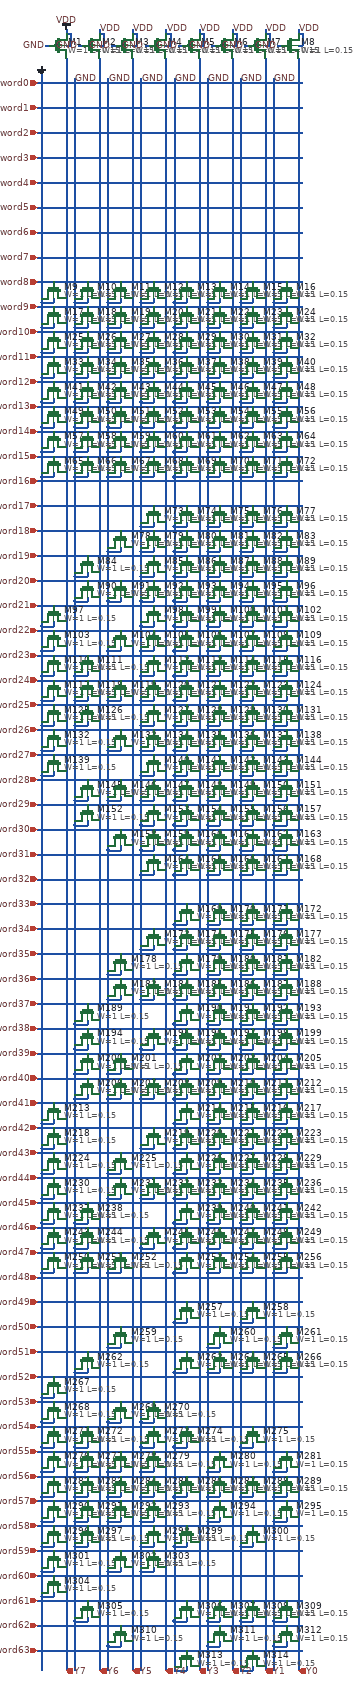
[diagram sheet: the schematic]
v {xschem version=3.4.5 file_version=1.2
}
G {}
K {}
V {}
S {}
E {}
N 10 -30 10 0 {
lab=GND}
N 20 -80 30 -80 {
lab=GND}
N 70 -120 70 -110 {
lab=VDD}
N 70 -80 80 -80 {
lab=VDD}
N 80 -110 80 -80 {
lab=VDD}
N 70 -110 80 -110 {
lab=VDD}
N 150 -80 160 -80 {
lab=VDD}
N 160 -110 160 -80 {
lab=VDD}
N 150 -110 160 -110 {
lab=VDD}
N 150 -120 150 -110 {
lab=VDD}
N 230 -120 230 -110 {
lab=VDD}
N 230 -110 240 -110 {
lab=VDD}
N 240 -110 240 -80 {
lab=VDD}
N 230 -80 240 -80 {
lab=VDD}
N 310 -120 310 -110 {
lab=VDD}
N 310 -110 320 -110 {
lab=VDD}
N 320 -110 320 -80 {
lab=VDD}
N 310 -80 320 -80 {
lab=VDD}
N 390 -120 390 -110 {
lab=VDD}
N 390 -110 400 -110 {
lab=VDD}
N 400 -110 400 -80 {
lab=VDD}
N 390 -80 400 -80 {
lab=VDD}
N 470 -80 480 -80 {
lab=VDD}
N 480 -110 480 -80 {
lab=VDD}
N 470 -110 480 -110 {
lab=VDD}
N 470 -120 470 -110 {
lab=VDD}
N 550 -80 560 -80 {
lab=VDD}
N 560 -110 560 -80 {
lab=VDD}
N 550 -110 560 -110 {
lab=VDD}
N 550 -120 550 -110 {
lab=VDD}
N 630 -80 640 -80 {
lab=VDD}
N 640 -110 640 -80 {
lab=VDD}
N 630 -110 640 -110 {
lab=VDD}
N 630 -120 630 -110 {
lab=VDD}
N 70 -50 70 0 {
lab=Y7}
N 150 -50 150 0 {
lab=Y6}
N 230 -50 230 0 {
lab=Y5}
N 310 -50 310 0 {
lab=Y4}
N 390 -50 390 0 {
lab=Y3}
N 470 -50 470 0 {
lab=Y2}
N 550 -50 550 0 {
lab=Y1}
N 630 -50 630 0 {
lab=Y0}
N 100 -80 110 -80 {
lab=GND}
N 180 -80 190 -80 {
lab=GND}
N 260 -80 270 -80 {
lab=GND}
N 340 -80 350 -80 {
lab=GND}
N 420 -80 430 -80 {
lab=GND}
N 500 -80 510 -80 {
lab=GND}
N 580 -80 590 -80 {
lab=GND}
N 0 10 40 10 {
lab=word0}
N 40 10 80 10 {
lab=word0}
N 10 0 10 50 {
lab=GND}
N 10 50 10 60 {
lab=GND}
N 70 0 70 50 {
lab=Y0}
N 70 50 70 60 {
lab=Y0}
N 80 10 120 10 {
lab=word0}
N 120 10 160 10 {
lab=word0}
N 90 0 90 50 {
lab=GND}
N 90 50 90 60 {
lab=GND}
N 150 0 150 50 {
lab=Y1}
N 150 50 150 60 {
lab=Y1}
N 160 10 200 10 {
lab=word0}
N 200 10 240 10 {
lab=word0}
N 170 0 170 50 {
lab=GND}
N 170 50 170 60 {
lab=GND}
N 230 0 230 50 {
lab=Y2}
N 230 50 230 60 {
lab=Y2}
N 240 10 280 10 {
lab=word0}
N 280 10 320 10 {
lab=word0}
N 250 0 250 50 {
lab=GND}
N 250 50 250 60 {
lab=GND}
N 310 0 310 50 {
lab=Y3}
N 310 50 310 60 {
lab=Y3}
N 320 10 360 10 {
lab=word0}
N 360 10 400 10 {
lab=word0}
N 330 0 330 50 {
lab=GND}
N 330 50 330 60 {
lab=GND}
N 390 0 390 50 {
lab=Y4}
N 390 50 390 60 {
lab=Y4}
N 400 10 440 10 {
lab=word0}
N 440 10 480 10 {
lab=word0}
N 410 0 410 50 {
lab=GND}
N 410 50 410 60 {
lab=GND}
N 470 0 470 50 {
lab=Y5}
N 470 50 470 60 {
lab=Y5}
N 480 10 520 10 {
lab=word0}
N 520 10 560 10 {
lab=word0}
N 490 0 490 50 {
lab=GND}
N 490 50 490 60 {
lab=GND}
N 550 0 550 50 {
lab=Y6}
N 550 50 550 60 {
lab=Y6}
N 560 10 600 10 {
lab=word0}
N 600 10 640 10 {
lab=word0}
N 570 0 570 50 {
lab=GND}
N 570 50 570 60 {
lab=GND}
N 630 0 630 50 {
lab=Y7}
N 630 50 630 60 {
lab=Y7}
N 0 70 40 70 {
lab=word1}
N 40 70 80 70 {
lab=word1}
N 10 60 10 110 {
lab=GND}
N 10 110 10 120 {
lab=GND}
N 70 60 70 110 {
lab=Y0}
N 70 110 70 120 {
lab=Y0}
N 80 70 120 70 {
lab=word1}
N 120 70 160 70 {
lab=word1}
N 90 60 90 110 {
lab=GND}
N 90 110 90 120 {
lab=GND}
N 150 60 150 110 {
lab=Y1}
N 150 110 150 120 {
lab=Y1}
N 160 70 200 70 {
lab=word1}
N 200 70 240 70 {
lab=word1}
N 170 60 170 110 {
lab=GND}
N 170 110 170 120 {
lab=GND}
N 230 60 230 110 {
lab=Y2}
N 230 110 230 120 {
lab=Y2}
N 240 70 280 70 {
lab=word1}
N 280 70 320 70 {
lab=word1}
N 250 60 250 110 {
lab=GND}
N 250 110 250 120 {
lab=GND}
N 310 60 310 110 {
lab=Y3}
N 310 110 310 120 {
lab=Y3}
N 320 70 360 70 {
lab=word1}
N 360 70 400 70 {
lab=word1}
N 330 60 330 110 {
lab=GND}
N 330 110 330 120 {
lab=GND}
N 390 60 390 110 {
lab=Y4}
N 390 110 390 120 {
lab=Y4}
N 400 70 440 70 {
lab=word1}
N 440 70 480 70 {
lab=word1}
N 410 60 410 110 {
lab=GND}
N 410 110 410 120 {
lab=GND}
N 470 60 470 110 {
lab=Y5}
N 470 110 470 120 {
lab=Y5}
N 480 70 520 70 {
lab=word1}
N 520 70 560 70 {
lab=word1}
N 490 60 490 110 {
lab=GND}
N 490 110 490 120 {
lab=GND}
N 550 60 550 110 {
lab=Y6}
N 550 110 550 120 {
lab=Y6}
N 560 70 600 70 {
lab=word1}
N 600 70 640 70 {
lab=word1}
N 570 60 570 110 {
lab=GND}
N 570 110 570 120 {
lab=GND}
N 630 60 630 110 {
lab=Y7}
N 630 110 630 120 {
lab=Y7}
N 0 130 40 130 {
lab=word2}
N 40 130 80 130 {
lab=word2}
N 10 120 10 170 {
lab=GND}
N 10 170 10 180 {
lab=GND}
N 70 120 70 170 {
lab=Y0}
N 70 170 70 180 {
lab=Y0}
N 80 130 120 130 {
lab=word2}
N 120 130 160 130 {
lab=word2}
N 90 120 90 170 {
lab=GND}
N 90 170 90 180 {
lab=GND}
N 150 120 150 170 {
lab=Y1}
N 150 170 150 180 {
lab=Y1}
N 160 130 200 130 {
lab=word2}
N 200 130 240 130 {
lab=word2}
N 170 120 170 170 {
lab=GND}
N 170 170 170 180 {
lab=GND}
N 230 120 230 170 {
lab=Y2}
N 230 170 230 180 {
lab=Y2}
N 240 130 280 130 {
lab=word2}
N 280 130 320 130 {
lab=word2}
N 250 120 250 170 {
lab=GND}
N 250 170 250 180 {
lab=GND}
N 310 120 310 170 {
lab=Y3}
N 310 170 310 180 {
lab=Y3}
N 320 130 360 130 {
lab=word2}
N 360 130 400 130 {
lab=word2}
N 330 120 330 170 {
lab=GND}
N 330 170 330 180 {
lab=GND}
N 390 120 390 170 {
lab=Y4}
N 390 170 390 180 {
lab=Y4}
N 400 130 440 130 {
lab=word2}
N 440 130 480 130 {
lab=word2}
N 410 120 410 170 {
lab=GND}
N 410 170 410 180 {
lab=GND}
N 470 120 470 170 {
lab=Y5}
N 470 170 470 180 {
lab=Y5}
N 480 130 520 130 {
lab=word2}
N 520 130 560 130 {
lab=word2}
N 490 120 490 170 {
lab=GND}
N 490 170 490 180 {
lab=GND}
N 550 120 550 170 {
lab=Y6}
N 550 170 550 180 {
lab=Y6}
N 560 130 600 130 {
lab=word2}
N 600 130 640 130 {
lab=word2}
N 570 120 570 170 {
lab=GND}
N 570 170 570 180 {
lab=GND}
N 630 120 630 170 {
lab=Y7}
N 630 170 630 180 {
lab=Y7}
N 0 190 40 190 {
lab=word3}
N 40 190 80 190 {
lab=word3}
N 10 180 10 230 {
lab=GND}
N 10 230 10 240 {
lab=GND}
N 70 180 70 230 {
lab=Y0}
N 70 230 70 240 {
lab=Y0}
N 80 190 120 190 {
lab=word3}
N 120 190 160 190 {
lab=word3}
N 90 180 90 230 {
lab=GND}
N 90 230 90 240 {
lab=GND}
N 150 180 150 230 {
lab=Y1}
N 150 230 150 240 {
lab=Y1}
N 160 190 200 190 {
lab=word3}
N 200 190 240 190 {
lab=word3}
N 170 180 170 230 {
lab=GND}
N 170 230 170 240 {
lab=GND}
N 230 180 230 230 {
lab=Y2}
N 230 230 230 240 {
lab=Y2}
N 240 190 280 190 {
lab=word3}
N 280 190 320 190 {
lab=word3}
N 250 180 250 230 {
lab=GND}
N 250 230 250 240 {
lab=GND}
N 310 180 310 230 {
lab=Y3}
N 310 230 310 240 {
lab=Y3}
N 320 190 360 190 {
lab=word3}
N 360 190 400 190 {
lab=word3}
N 330 180 330 230 {
lab=GND}
N 330 230 330 240 {
lab=GND}
N 390 180 390 230 {
lab=Y4}
N 390 230 390 240 {
lab=Y4}
N 400 190 440 190 {
lab=word3}
N 440 190 480 190 {
lab=word3}
N 410 180 410 230 {
lab=GND}
N 410 230 410 240 {
lab=GND}
N 470 180 470 230 {
lab=Y5}
N 470 230 470 240 {
lab=Y5}
N 480 190 520 190 {
lab=word3}
N 520 190 560 190 {
lab=word3}
N 490 180 490 230 {
lab=GND}
N 490 230 490 240 {
lab=GND}
N 550 180 550 230 {
lab=Y6}
N 550 230 550 240 {
lab=Y6}
N 560 190 600 190 {
lab=word3}
N 600 190 640 190 {
lab=word3}
N 570 180 570 230 {
lab=GND}
N 570 230 570 240 {
lab=GND}
N 630 180 630 230 {
lab=Y7}
N 630 230 630 240 {
lab=Y7}
N 0 250 40 250 {
lab=word4}
N 40 250 80 250 {
lab=word4}
N 10 240 10 290 {
lab=GND}
N 10 290 10 300 {
lab=GND}
N 70 240 70 290 {
lab=Y0}
N 70 290 70 300 {
lab=Y0}
N 80 250 120 250 {
lab=word4}
N 120 250 160 250 {
lab=word4}
N 90 240 90 290 {
lab=GND}
N 90 290 90 300 {
lab=GND}
N 150 240 150 290 {
lab=Y1}
N 150 290 150 300 {
lab=Y1}
N 160 250 200 250 {
lab=word4}
N 200 250 240 250 {
lab=word4}
N 170 240 170 290 {
lab=GND}
N 170 290 170 300 {
lab=GND}
N 230 240 230 290 {
lab=Y2}
N 230 290 230 300 {
lab=Y2}
N 240 250 280 250 {
lab=word4}
N 280 250 320 250 {
lab=word4}
N 250 240 250 290 {
lab=GND}
N 250 290 250 300 {
lab=GND}
N 310 240 310 290 {
lab=Y3}
N 310 290 310 300 {
lab=Y3}
N 320 250 360 250 {
lab=word4}
N 360 250 400 250 {
lab=word4}
N 330 240 330 290 {
lab=GND}
N 330 290 330 300 {
lab=GND}
N 390 240 390 290 {
lab=Y4}
N 390 290 390 300 {
lab=Y4}
N 400 250 440 250 {
lab=word4}
N 440 250 480 250 {
lab=word4}
N 410 240 410 290 {
lab=GND}
N 410 290 410 300 {
lab=GND}
N 470 240 470 290 {
lab=Y5}
N 470 290 470 300 {
lab=Y5}
N 480 250 520 250 {
lab=word4}
N 520 250 560 250 {
lab=word4}
N 490 240 490 290 {
lab=GND}
N 490 290 490 300 {
lab=GND}
N 550 240 550 290 {
lab=Y6}
N 550 290 550 300 {
lab=Y6}
N 560 250 600 250 {
lab=word4}
N 600 250 640 250 {
lab=word4}
N 570 240 570 290 {
lab=GND}
N 570 290 570 300 {
lab=GND}
N 630 240 630 290 {
lab=Y7}
N 630 290 630 300 {
lab=Y7}
N 0 310 40 310 {
lab=word5}
N 40 310 80 310 {
lab=word5}
N 10 300 10 350 {
lab=GND}
N 10 350 10 360 {
lab=GND}
N 70 300 70 350 {
lab=Y0}
N 70 350 70 360 {
lab=Y0}
N 80 310 120 310 {
lab=word5}
N 120 310 160 310 {
lab=word5}
N 90 300 90 350 {
lab=GND}
N 90 350 90 360 {
lab=GND}
N 150 300 150 350 {
lab=Y1}
N 150 350 150 360 {
lab=Y1}
N 160 310 200 310 {
lab=word5}
N 200 310 240 310 {
lab=word5}
N 170 300 170 350 {
lab=GND}
N 170 350 170 360 {
lab=GND}
N 230 300 230 350 {
lab=Y2}
N 230 350 230 360 {
lab=Y2}
N 240 310 280 310 {
lab=word5}
N 280 310 320 310 {
lab=word5}
N 250 300 250 350 {
lab=GND}
N 250 350 250 360 {
lab=GND}
N 310 300 310 350 {
lab=Y3}
N 310 350 310 360 {
lab=Y3}
N 320 310 360 310 {
lab=word5}
N 360 310 400 310 {
lab=word5}
N 330 300 330 350 {
lab=GND}
N 330 350 330 360 {
lab=GND}
N 390 300 390 350 {
lab=Y4}
N 390 350 390 360 {
lab=Y4}
N 400 310 440 310 {
lab=word5}
N 440 310 480 310 {
lab=word5}
N 410 300 410 350 {
lab=GND}
N 410 350 410 360 {
lab=GND}
N 470 300 470 350 {
lab=Y5}
N 470 350 470 360 {
lab=Y5}
N 480 310 520 310 {
lab=word5}
N 520 310 560 310 {
lab=word5}
N 490 300 490 350 {
lab=GND}
N 490 350 490 360 {
lab=GND}
N 550 300 550 350 {
lab=Y6}
N 550 350 550 360 {
lab=Y6}
N 560 310 600 310 {
lab=word5}
N 600 310 640 310 {
lab=word5}
N 570 300 570 350 {
lab=GND}
N 570 350 570 360 {
lab=GND}
N 630 300 630 350 {
lab=Y7}
N 630 350 630 360 {
lab=Y7}
N 0 370 40 370 {
lab=word6}
N 40 370 80 370 {
lab=word6}
N 10 360 10 410 {
lab=GND}
N 10 410 10 420 {
lab=GND}
N 70 360 70 410 {
lab=Y0}
N 70 410 70 420 {
lab=Y0}
N 80 370 120 370 {
lab=word6}
N 120 370 160 370 {
lab=word6}
N 90 360 90 410 {
lab=GND}
N 90 410 90 420 {
lab=GND}
N 150 360 150 410 {
lab=Y1}
N 150 410 150 420 {
lab=Y1}
N 160 370 200 370 {
lab=word6}
N 200 370 240 370 {
lab=word6}
N 170 360 170 410 {
lab=GND}
N 170 410 170 420 {
lab=GND}
N 230 360 230 410 {
lab=Y2}
N 230 410 230 420 {
lab=Y2}
N 240 370 280 370 {
lab=word6}
N 280 370 320 370 {
lab=word6}
N 250 360 250 410 {
lab=GND}
N 250 410 250 420 {
lab=GND}
N 310 360 310 410 {
lab=Y3}
N 310 410 310 420 {
lab=Y3}
N 320 370 360 370 {
lab=word6}
N 360 370 400 370 {
lab=word6}
N 330 360 330 410 {
lab=GND}
N 330 410 330 420 {
lab=GND}
N 390 360 390 410 {
lab=Y4}
N 390 410 390 420 {
lab=Y4}
N 400 370 440 370 {
lab=word6}
N 440 370 480 370 {
lab=word6}
N 410 360 410 410 {
lab=GND}
N 410 410 410 420 {
lab=GND}
N 470 360 470 410 {
lab=Y5}
N 470 410 470 420 {
lab=Y5}
N 480 370 520 370 {
lab=word6}
N 520 370 560 370 {
lab=word6}
N 490 360 490 410 {
lab=GND}
N 490 410 490 420 {
lab=GND}
N 550 360 550 410 {
lab=Y6}
N 550 410 550 420 {
lab=Y6}
N 560 370 600 370 {
lab=word6}
N 600 370 640 370 {
lab=word6}
N 570 360 570 410 {
lab=GND}
N 570 410 570 420 {
lab=GND}
N 630 360 630 410 {
lab=Y7}
N 630 410 630 420 {
lab=Y7}
N 0 430 40 430 {
lab=word7}
N 40 430 80 430 {
lab=word7}
N 10 420 10 470 {
lab=GND}
N 10 470 10 480 {
lab=GND}
N 70 420 70 470 {
lab=Y0}
N 70 470 70 480 {
lab=Y0}
N 80 430 120 430 {
lab=word7}
N 120 430 160 430 {
lab=word7}
N 90 420 90 470 {
lab=GND}
N 90 470 90 480 {
lab=GND}
N 150 420 150 470 {
lab=Y1}
N 150 470 150 480 {
lab=Y1}
N 160 430 200 430 {
lab=word7}
N 200 430 240 430 {
lab=word7}
N 170 420 170 470 {
lab=GND}
N 170 470 170 480 {
lab=GND}
N 230 420 230 470 {
lab=Y2}
N 230 470 230 480 {
lab=Y2}
N 240 430 280 430 {
lab=word7}
N 280 430 320 430 {
lab=word7}
N 250 420 250 470 {
lab=GND}
N 250 470 250 480 {
lab=GND}
N 310 420 310 470 {
lab=Y3}
N 310 470 310 480 {
lab=Y3}
N 320 430 360 430 {
lab=word7}
N 360 430 400 430 {
lab=word7}
N 330 420 330 470 {
lab=GND}
N 330 470 330 480 {
lab=GND}
N 390 420 390 470 {
lab=Y4}
N 390 470 390 480 {
lab=Y4}
N 400 430 440 430 {
lab=word7}
N 440 430 480 430 {
lab=word7}
N 410 420 410 470 {
lab=GND}
N 410 470 410 480 {
lab=GND}
N 470 420 470 470 {
lab=Y5}
N 470 470 470 480 {
lab=Y5}
N 480 430 520 430 {
lab=word7}
N 520 430 560 430 {
lab=word7}
N 490 420 490 470 {
lab=GND}
N 490 470 490 480 {
lab=GND}
N 550 420 550 470 {
lab=Y6}
N 550 470 550 480 {
lab=Y6}
N 560 430 600 430 {
lab=word7}
N 600 430 640 430 {
lab=word7}
N 570 420 570 470 {
lab=GND}
N 570 470 570 480 {
lab=GND}
N 630 420 630 470 {
lab=Y7}
N 630 470 630 480 {
lab=Y7}
N 10 540 40 540 {
lab=GND}
N 40 530 40 540 {
lab=GND}
N 0 490 40 490 {
lab=word8}
N 40 490 80 490 {
lab=word8}
N 10 480 10 530 {
lab=GND}
N 10 530 10 540 {
lab=GND}
N 70 480 70 530 {
lab=Y0}
N 70 530 70 540 {
lab=Y0}
N 90 540 120 540 {
lab=GND}
N 120 530 120 540 {
lab=GND}
N 80 490 120 490 {
lab=word8}
N 120 490 160 490 {
lab=word8}
N 90 480 90 530 {
lab=GND}
N 90 530 90 540 {
lab=GND}
N 150 480 150 530 {
lab=Y1}
N 150 530 150 540 {
lab=Y1}
N 170 540 200 540 {
lab=GND}
N 200 530 200 540 {
lab=GND}
N 160 490 200 490 {
lab=word8}
N 200 490 240 490 {
lab=word8}
N 170 480 170 530 {
lab=GND}
N 170 530 170 540 {
lab=GND}
N 230 480 230 530 {
lab=Y2}
N 230 530 230 540 {
lab=Y2}
N 250 540 280 540 {
lab=GND}
N 280 530 280 540 {
lab=GND}
N 240 490 280 490 {
lab=word8}
N 280 490 320 490 {
lab=word8}
N 250 480 250 530 {
lab=GND}
N 250 530 250 540 {
lab=GND}
N 310 480 310 530 {
lab=Y3}
N 310 530 310 540 {
lab=Y3}
N 330 540 360 540 {
lab=GND}
N 360 530 360 540 {
lab=GND}
N 320 490 360 490 {
lab=word8}
N 360 490 400 490 {
lab=word8}
N 330 480 330 530 {
lab=GND}
N 330 530 330 540 {
lab=GND}
N 390 480 390 530 {
lab=Y4}
N 390 530 390 540 {
lab=Y4}
N 410 540 440 540 {
lab=GND}
N 440 530 440 540 {
lab=GND}
N 400 490 440 490 {
lab=word8}
N 440 490 480 490 {
lab=word8}
N 410 480 410 530 {
lab=GND}
N 410 530 410 540 {
lab=GND}
N 470 480 470 530 {
lab=Y5}
N 470 530 470 540 {
lab=Y5}
N 490 540 520 540 {
lab=GND}
N 520 530 520 540 {
lab=GND}
N 480 490 520 490 {
lab=word8}
N 520 490 560 490 {
lab=word8}
N 490 480 490 530 {
lab=GND}
N 490 530 490 540 {
lab=GND}
N 550 480 550 530 {
lab=Y6}
N 550 530 550 540 {
lab=Y6}
N 570 540 600 540 {
lab=GND}
N 600 530 600 540 {
lab=GND}
N 560 490 600 490 {
lab=word8}
N 600 490 640 490 {
lab=word8}
N 570 480 570 530 {
lab=GND}
N 570 530 570 540 {
lab=GND}
N 630 480 630 530 {
lab=Y7}
N 630 530 630 540 {
lab=Y7}
N 10 600 40 600 {
lab=GND}
N 40 590 40 600 {
lab=GND}
N 0 550 40 550 {
lab=word9}
N 40 550 80 550 {
lab=word9}
N 10 540 10 590 {
lab=GND}
N 10 590 10 600 {
lab=GND}
N 70 540 70 590 {
lab=Y0}
N 70 590 70 600 {
lab=Y0}
N 90 600 120 600 {
lab=GND}
N 120 590 120 600 {
lab=GND}
N 80 550 120 550 {
lab=word9}
N 120 550 160 550 {
lab=word9}
N 90 540 90 590 {
lab=GND}
N 90 590 90 600 {
lab=GND}
N 150 540 150 590 {
lab=Y1}
N 150 590 150 600 {
lab=Y1}
N 170 600 200 600 {
lab=GND}
N 200 590 200 600 {
lab=GND}
N 160 550 200 550 {
lab=word9}
N 200 550 240 550 {
lab=word9}
N 170 540 170 590 {
lab=GND}
N 170 590 170 600 {
lab=GND}
N 230 540 230 590 {
lab=Y2}
N 230 590 230 600 {
lab=Y2}
N 250 600 280 600 {
lab=GND}
N 280 590 280 600 {
lab=GND}
N 240 550 280 550 {
lab=word9}
N 280 550 320 550 {
lab=word9}
N 250 540 250 590 {
lab=GND}
N 250 590 250 600 {
lab=GND}
N 310 540 310 590 {
lab=Y3}
N 310 590 310 600 {
lab=Y3}
N 330 600 360 600 {
lab=GND}
N 360 590 360 600 {
lab=GND}
N 320 550 360 550 {
lab=word9}
N 360 550 400 550 {
lab=word9}
N 330 540 330 590 {
lab=GND}
N 330 590 330 600 {
lab=GND}
N 390 540 390 590 {
lab=Y4}
N 390 590 390 600 {
lab=Y4}
N 410 600 440 600 {
lab=GND}
N 440 590 440 600 {
lab=GND}
N 400 550 440 550 {
lab=word9}
N 440 550 480 550 {
lab=word9}
N 410 540 410 590 {
lab=GND}
N 410 590 410 600 {
lab=GND}
N 470 540 470 590 {
lab=Y5}
N 470 590 470 600 {
lab=Y5}
N 490 600 520 600 {
lab=GND}
N 520 590 520 600 {
lab=GND}
N 480 550 520 550 {
lab=word9}
N 520 550 560 550 {
lab=word9}
N 490 540 490 590 {
lab=GND}
N 490 590 490 600 {
lab=GND}
N 550 540 550 590 {
lab=Y6}
N 550 590 550 600 {
lab=Y6}
N 570 600 600 600 {
lab=GND}
N 600 590 600 600 {
lab=GND}
N 560 550 600 550 {
lab=word9}
N 600 550 640 550 {
lab=word9}
N 570 540 570 590 {
lab=GND}
N 570 590 570 600 {
lab=GND}
N 630 540 630 590 {
lab=Y7}
N 630 590 630 600 {
lab=Y7}
N 10 660 40 660 {
lab=GND}
N 40 650 40 660 {
lab=GND}
N 0 610 40 610 {
lab=word10}
N 40 610 80 610 {
lab=word10}
N 10 600 10 650 {
lab=GND}
N 10 650 10 660 {
lab=GND}
N 70 600 70 650 {
lab=Y0}
N 70 650 70 660 {
lab=Y0}
N 90 660 120 660 {
lab=GND}
N 120 650 120 660 {
lab=GND}
N 80 610 120 610 {
lab=word10}
N 120 610 160 610 {
lab=word10}
N 90 600 90 650 {
lab=GND}
N 90 650 90 660 {
lab=GND}
N 150 600 150 650 {
lab=Y1}
N 150 650 150 660 {
lab=Y1}
N 170 660 200 660 {
lab=GND}
N 200 650 200 660 {
lab=GND}
N 160 610 200 610 {
lab=word10}
N 200 610 240 610 {
lab=word10}
N 170 600 170 650 {
lab=GND}
N 170 650 170 660 {
lab=GND}
N 230 600 230 650 {
lab=Y2}
N 230 650 230 660 {
lab=Y2}
N 250 660 280 660 {
lab=GND}
N 280 650 280 660 {
lab=GND}
N 240 610 280 610 {
lab=word10}
N 280 610 320 610 {
lab=word10}
N 250 600 250 650 {
lab=GND}
N 250 650 250 660 {
lab=GND}
N 310 600 310 650 {
lab=Y3}
N 310 650 310 660 {
lab=Y3}
N 330 660 360 660 {
lab=GND}
N 360 650 360 660 {
lab=GND}
N 320 610 360 610 {
lab=word10}
N 360 610 400 610 {
lab=word10}
N 330 600 330 650 {
lab=GND}
N 330 650 330 660 {
lab=GND}
N 390 600 390 650 {
lab=Y4}
N 390 650 390 660 {
lab=Y4}
N 410 660 440 660 {
lab=GND}
N 440 650 440 660 {
lab=GND}
N 400 610 440 610 {
lab=word10}
N 440 610 480 610 {
lab=word10}
N 410 600 410 650 {
lab=GND}
N 410 650 410 660 {
lab=GND}
N 470 600 470 650 {
lab=Y5}
N 470 650 470 660 {
lab=Y5}
N 490 660 520 660 {
lab=GND}
N 520 650 520 660 {
lab=GND}
N 480 610 520 610 {
lab=word10}
N 520 610 560 610 {
lab=word10}
N 490 600 490 650 {
lab=GND}
N 490 650 490 660 {
lab=GND}
N 550 600 550 650 {
lab=Y6}
N 550 650 550 660 {
lab=Y6}
N 570 660 600 660 {
lab=GND}
N 600 650 600 660 {
lab=GND}
N 560 610 600 610 {
lab=word10}
N 600 610 640 610 {
lab=word10}
N 570 600 570 650 {
lab=GND}
N 570 650 570 660 {
lab=GND}
N 630 600 630 650 {
lab=Y7}
N 630 650 630 660 {
lab=Y7}
N 10 720 40 720 {
lab=GND}
N 40 710 40 720 {
lab=GND}
N 0 670 40 670 {
lab=word11}
N 40 670 80 670 {
lab=word11}
N 10 660 10 710 {
lab=GND}
N 10 710 10 720 {
lab=GND}
N 70 660 70 710 {
lab=Y0}
N 70 710 70 720 {
lab=Y0}
N 90 720 120 720 {
lab=GND}
N 120 710 120 720 {
lab=GND}
N 80 670 120 670 {
lab=word11}
N 120 670 160 670 {
lab=word11}
N 90 660 90 710 {
lab=GND}
N 90 710 90 720 {
lab=GND}
N 150 660 150 710 {
lab=Y1}
N 150 710 150 720 {
lab=Y1}
N 170 720 200 720 {
lab=GND}
N 200 710 200 720 {
lab=GND}
N 160 670 200 670 {
lab=word11}
N 200 670 240 670 {
lab=word11}
N 170 660 170 710 {
lab=GND}
N 170 710 170 720 {
lab=GND}
N 230 660 230 710 {
lab=Y2}
N 230 710 230 720 {
lab=Y2}
N 250 720 280 720 {
lab=GND}
N 280 710 280 720 {
lab=GND}
N 240 670 280 670 {
lab=word11}
N 280 670 320 670 {
lab=word11}
N 250 660 250 710 {
lab=GND}
N 250 710 250 720 {
lab=GND}
N 310 660 310 710 {
lab=Y3}
N 310 710 310 720 {
lab=Y3}
N 330 720 360 720 {
lab=GND}
N 360 710 360 720 {
lab=GND}
N 320 670 360 670 {
lab=word11}
N 360 670 400 670 {
lab=word11}
N 330 660 330 710 {
lab=GND}
N 330 710 330 720 {
lab=GND}
N 390 660 390 710 {
lab=Y4}
N 390 710 390 720 {
lab=Y4}
N 410 720 440 720 {
lab=GND}
N 440 710 440 720 {
lab=GND}
N 400 670 440 670 {
lab=word11}
N 440 670 480 670 {
lab=word11}
N 410 660 410 710 {
lab=GND}
N 410 710 410 720 {
lab=GND}
N 470 660 470 710 {
lab=Y5}
N 470 710 470 720 {
lab=Y5}
N 490 720 520 720 {
lab=GND}
N 520 710 520 720 {
lab=GND}
N 480 670 520 670 {
lab=word11}
N 520 670 560 670 {
lab=word11}
N 490 660 490 710 {
lab=GND}
N 490 710 490 720 {
lab=GND}
N 550 660 550 710 {
lab=Y6}
N 550 710 550 720 {
lab=Y6}
N 570 720 600 720 {
lab=GND}
N 600 710 600 720 {
lab=GND}
N 560 670 600 670 {
lab=word11}
N 600 670 640 670 {
lab=word11}
N 570 660 570 710 {
lab=GND}
N 570 710 570 720 {
lab=GND}
N 630 660 630 710 {
lab=Y7}
N 630 710 630 720 {
lab=Y7}
N 10 780 40 780 {
lab=GND}
N 40 770 40 780 {
lab=GND}
N 0 730 40 730 {
lab=word12}
N 40 730 80 730 {
lab=word12}
N 10 720 10 770 {
lab=GND}
N 10 770 10 780 {
lab=GND}
N 70 720 70 770 {
lab=Y0}
N 70 770 70 780 {
lab=Y0}
N 90 780 120 780 {
lab=GND}
N 120 770 120 780 {
lab=GND}
N 80 730 120 730 {
lab=word12}
N 120 730 160 730 {
lab=word12}
N 90 720 90 770 {
lab=GND}
N 90 770 90 780 {
lab=GND}
N 150 720 150 770 {
lab=Y1}
N 150 770 150 780 {
lab=Y1}
N 170 780 200 780 {
lab=GND}
N 200 770 200 780 {
lab=GND}
N 160 730 200 730 {
lab=word12}
N 200 730 240 730 {
lab=word12}
N 170 720 170 770 {
lab=GND}
N 170 770 170 780 {
lab=GND}
N 230 720 230 770 {
lab=Y2}
N 230 770 230 780 {
lab=Y2}
N 250 780 280 780 {
lab=GND}
N 280 770 280 780 {
lab=GND}
N 240 730 280 730 {
lab=word12}
N 280 730 320 730 {
lab=word12}
N 250 720 250 770 {
lab=GND}
N 250 770 250 780 {
lab=GND}
N 310 720 310 770 {
lab=Y3}
N 310 770 310 780 {
lab=Y3}
N 330 780 360 780 {
lab=GND}
N 360 770 360 780 {
lab=GND}
N 320 730 360 730 {
lab=word12}
N 360 730 400 730 {
lab=word12}
N 330 720 330 770 {
lab=GND}
N 330 770 330 780 {
lab=GND}
N 390 720 390 770 {
lab=Y4}
N 390 770 390 780 {
lab=Y4}
N 410 780 440 780 {
lab=GND}
N 440 770 440 780 {
lab=GND}
N 400 730 440 730 {
lab=word12}
N 440 730 480 730 {
lab=word12}
N 410 720 410 770 {
lab=GND}
N 410 770 410 780 {
lab=GND}
N 470 720 470 770 {
lab=Y5}
N 470 770 470 780 {
lab=Y5}
N 490 780 520 780 {
lab=GND}
N 520 770 520 780 {
lab=GND}
N 480 730 520 730 {
lab=word12}
N 520 730 560 730 {
lab=word12}
N 490 720 490 770 {
lab=GND}
N 490 770 490 780 {
lab=GND}
N 550 720 550 770 {
lab=Y6}
N 550 770 550 780 {
lab=Y6}
N 570 780 600 780 {
lab=GND}
N 600 770 600 780 {
lab=GND}
N 560 730 600 730 {
lab=word12}
N 600 730 640 730 {
lab=word12}
N 570 720 570 770 {
lab=GND}
N 570 770 570 780 {
lab=GND}
N 630 720 630 770 {
lab=Y7}
N 630 770 630 780 {
lab=Y7}
N 10 840 40 840 {
lab=GND}
N 40 830 40 840 {
lab=GND}
N 0 790 40 790 {
lab=word13}
N 40 790 80 790 {
lab=word13}
N 10 780 10 830 {
lab=GND}
N 10 830 10 840 {
lab=GND}
N 70 780 70 830 {
lab=Y0}
N 70 830 70 840 {
lab=Y0}
N 90 840 120 840 {
lab=GND}
N 120 830 120 840 {
lab=GND}
N 80 790 120 790 {
lab=word13}
N 120 790 160 790 {
lab=word13}
N 90 780 90 830 {
lab=GND}
N 90 830 90 840 {
lab=GND}
N 150 780 150 830 {
lab=Y1}
N 150 830 150 840 {
lab=Y1}
N 170 840 200 840 {
lab=GND}
N 200 830 200 840 {
lab=GND}
N 160 790 200 790 {
lab=word13}
N 200 790 240 790 {
lab=word13}
N 170 780 170 830 {
lab=GND}
N 170 830 170 840 {
lab=GND}
N 230 780 230 830 {
lab=Y2}
N 230 830 230 840 {
lab=Y2}
N 250 840 280 840 {
lab=GND}
N 280 830 280 840 {
lab=GND}
N 240 790 280 790 {
lab=word13}
N 280 790 320 790 {
lab=word13}
N 250 780 250 830 {
lab=GND}
N 250 830 250 840 {
lab=GND}
N 310 780 310 830 {
lab=Y3}
N 310 830 310 840 {
lab=Y3}
N 330 840 360 840 {
lab=GND}
N 360 830 360 840 {
lab=GND}
N 320 790 360 790 {
lab=word13}
N 360 790 400 790 {
lab=word13}
N 330 780 330 830 {
lab=GND}
N 330 830 330 840 {
lab=GND}
N 390 780 390 830 {
lab=Y4}
N 390 830 390 840 {
lab=Y4}
N 410 840 440 840 {
lab=GND}
N 440 830 440 840 {
lab=GND}
N 400 790 440 790 {
lab=word13}
N 440 790 480 790 {
lab=word13}
N 410 780 410 830 {
lab=GND}
N 410 830 410 840 {
lab=GND}
N 470 780 470 830 {
lab=Y5}
N 470 830 470 840 {
lab=Y5}
N 490 840 520 840 {
lab=GND}
N 520 830 520 840 {
lab=GND}
N 480 790 520 790 {
lab=word13}
N 520 790 560 790 {
lab=word13}
N 490 780 490 830 {
lab=GND}
N 490 830 490 840 {
lab=GND}
N 550 780 550 830 {
lab=Y6}
N 550 830 550 840 {
lab=Y6}
N 570 840 600 840 {
lab=GND}
N 600 830 600 840 {
lab=GND}
N 560 790 600 790 {
lab=word13}
N 600 790 640 790 {
lab=word13}
N 570 780 570 830 {
lab=GND}
N 570 830 570 840 {
lab=GND}
N 630 780 630 830 {
lab=Y7}
N 630 830 630 840 {
lab=Y7}
N 10 900 40 900 {
lab=GND}
N 40 890 40 900 {
lab=GND}
N 0 850 40 850 {
lab=word14}
N 40 850 80 850 {
lab=word14}
N 10 840 10 890 {
lab=GND}
N 10 890 10 900 {
lab=GND}
N 70 840 70 890 {
lab=Y0}
N 70 890 70 900 {
lab=Y0}
N 90 900 120 900 {
lab=GND}
N 120 890 120 900 {
lab=GND}
N 80 850 120 850 {
lab=word14}
N 120 850 160 850 {
lab=word14}
N 90 840 90 890 {
lab=GND}
N 90 890 90 900 {
lab=GND}
N 150 840 150 890 {
lab=Y1}
N 150 890 150 900 {
lab=Y1}
N 170 900 200 900 {
lab=GND}
N 200 890 200 900 {
lab=GND}
N 160 850 200 850 {
lab=word14}
N 200 850 240 850 {
lab=word14}
N 170 840 170 890 {
lab=GND}
N 170 890 170 900 {
lab=GND}
N 230 840 230 890 {
lab=Y2}
N 230 890 230 900 {
lab=Y2}
N 250 900 280 900 {
lab=GND}
N 280 890 280 900 {
lab=GND}
N 240 850 280 850 {
lab=word14}
N 280 850 320 850 {
lab=word14}
N 250 840 250 890 {
lab=GND}
N 250 890 250 900 {
lab=GND}
N 310 840 310 890 {
lab=Y3}
N 310 890 310 900 {
lab=Y3}
N 330 900 360 900 {
lab=GND}
N 360 890 360 900 {
lab=GND}
N 320 850 360 850 {
lab=word14}
N 360 850 400 850 {
lab=word14}
N 330 840 330 890 {
lab=GND}
N 330 890 330 900 {
lab=GND}
N 390 840 390 890 {
lab=Y4}
N 390 890 390 900 {
lab=Y4}
N 410 900 440 900 {
lab=GND}
N 440 890 440 900 {
lab=GND}
N 400 850 440 850 {
lab=word14}
N 440 850 480 850 {
lab=word14}
N 410 840 410 890 {
lab=GND}
N 410 890 410 900 {
lab=GND}
N 470 840 470 890 {
lab=Y5}
N 470 890 470 900 {
lab=Y5}
N 490 900 520 900 {
lab=GND}
N 520 890 520 900 {
lab=GND}
N 480 850 520 850 {
lab=word14}
N 520 850 560 850 {
lab=word14}
N 490 840 490 890 {
lab=GND}
N 490 890 490 900 {
lab=GND}
N 550 840 550 890 {
lab=Y6}
N 550 890 550 900 {
lab=Y6}
N 570 900 600 900 {
lab=GND}
N 600 890 600 900 {
lab=GND}
N 560 850 600 850 {
lab=word14}
N 600 850 640 850 {
lab=word14}
N 570 840 570 890 {
lab=GND}
N 570 890 570 900 {
lab=GND}
N 630 840 630 890 {
lab=Y7}
N 630 890 630 900 {
lab=Y7}
N 10 960 40 960 {
lab=GND}
N 40 950 40 960 {
lab=GND}
N 0 910 40 910 {
lab=word15}
N 40 910 80 910 {
lab=word15}
N 10 900 10 950 {
lab=GND}
N 10 950 10 960 {
lab=GND}
N 70 900 70 950 {
lab=Y0}
N 70 950 70 960 {
lab=Y0}
N 90 960 120 960 {
lab=GND}
N 120 950 120 960 {
lab=GND}
N 80 910 120 910 {
lab=word15}
N 120 910 160 910 {
lab=word15}
N 90 900 90 950 {
lab=GND}
N 90 950 90 960 {
lab=GND}
N 150 900 150 950 {
lab=Y1}
N 150 950 150 960 {
lab=Y1}
N 170 960 200 960 {
lab=GND}
N 200 950 200 960 {
lab=GND}
N 160 910 200 910 {
lab=word15}
N 200 910 240 910 {
lab=word15}
N 170 900 170 950 {
lab=GND}
N 170 950 170 960 {
lab=GND}
N 230 900 230 950 {
lab=Y2}
N 230 950 230 960 {
lab=Y2}
N 250 960 280 960 {
lab=GND}
N 280 950 280 960 {
lab=GND}
N 240 910 280 910 {
lab=word15}
N 280 910 320 910 {
lab=word15}
N 250 900 250 950 {
lab=GND}
N 250 950 250 960 {
lab=GND}
N 310 900 310 950 {
lab=Y3}
N 310 950 310 960 {
lab=Y3}
N 330 960 360 960 {
lab=GND}
N 360 950 360 960 {
lab=GND}
N 320 910 360 910 {
lab=word15}
N 360 910 400 910 {
lab=word15}
N 330 900 330 950 {
lab=GND}
N 330 950 330 960 {
lab=GND}
N 390 900 390 950 {
lab=Y4}
N 390 950 390 960 {
lab=Y4}
N 410 960 440 960 {
lab=GND}
N 440 950 440 960 {
lab=GND}
N 400 910 440 910 {
lab=word15}
N 440 910 480 910 {
lab=word15}
N 410 900 410 950 {
lab=GND}
N 410 950 410 960 {
lab=GND}
N 470 900 470 950 {
lab=Y5}
N 470 950 470 960 {
lab=Y5}
N 490 960 520 960 {
lab=GND}
N 520 950 520 960 {
lab=GND}
N 480 910 520 910 {
lab=word15}
N 520 910 560 910 {
lab=word15}
N 490 900 490 950 {
lab=GND}
N 490 950 490 960 {
lab=GND}
N 550 900 550 950 {
lab=Y6}
N 550 950 550 960 {
lab=Y6}
N 570 960 600 960 {
lab=GND}
N 600 950 600 960 {
lab=GND}
N 560 910 600 910 {
lab=word15}
N 600 910 640 910 {
lab=word15}
N 570 900 570 950 {
lab=GND}
N 570 950 570 960 {
lab=GND}
N 630 900 630 950 {
lab=Y7}
N 630 950 630 960 {
lab=Y7}
N 0 970 40 970 {
lab=word16}
N 40 970 80 970 {
lab=word16}
N 10 960 10 1010 {
lab=GND}
N 10 1010 10 1020 {
lab=GND}
N 70 960 70 1010 {
lab=Y0}
N 70 1010 70 1020 {
lab=Y0}
N 80 970 120 970 {
lab=word16}
N 120 970 160 970 {
lab=word16}
N 90 960 90 1010 {
lab=GND}
N 90 1010 90 1020 {
lab=GND}
N 150 960 150 1010 {
lab=Y1}
N 150 1010 150 1020 {
lab=Y1}
N 160 970 200 970 {
lab=word16}
N 200 970 240 970 {
lab=word16}
N 170 960 170 1010 {
lab=GND}
N 170 1010 170 1020 {
lab=GND}
N 230 960 230 1010 {
lab=Y2}
N 230 1010 230 1020 {
lab=Y2}
N 240 970 280 970 {
lab=word16}
N 280 970 320 970 {
lab=word16}
N 250 960 250 1010 {
lab=GND}
N 250 1010 250 1020 {
lab=GND}
N 310 960 310 1010 {
lab=Y3}
N 310 1010 310 1020 {
lab=Y3}
N 320 970 360 970 {
lab=word16}
N 360 970 400 970 {
lab=word16}
N 330 960 330 1010 {
lab=GND}
N 330 1010 330 1020 {
lab=GND}
N 390 960 390 1010 {
lab=Y4}
N 390 1010 390 1020 {
lab=Y4}
N 400 970 440 970 {
lab=word16}
N 440 970 480 970 {
lab=word16}
N 410 960 410 1010 {
lab=GND}
N 410 1010 410 1020 {
lab=GND}
N 470 960 470 1010 {
lab=Y5}
N 470 1010 470 1020 {
lab=Y5}
N 480 970 520 970 {
lab=word16}
N 520 970 560 970 {
lab=word16}
N 490 960 490 1010 {
lab=GND}
N 490 1010 490 1020 {
lab=GND}
N 550 960 550 1010 {
lab=Y6}
N 550 1010 550 1020 {
lab=Y6}
N 560 970 600 970 {
lab=word16}
N 600 970 640 970 {
lab=word16}
N 570 960 570 1010 {
lab=GND}
N 570 1010 570 1020 {
lab=GND}
N 630 960 630 1010 {
lab=Y7}
N 630 1010 630 1020 {
lab=Y7}
N 0 1030 40 1030 {
lab=word17}
N 40 1030 80 1030 {
lab=word17}
N 10 1020 10 1070 {
lab=GND}
N 10 1070 10 1080 {
lab=GND}
N 70 1020 70 1070 {
lab=Y0}
N 70 1070 70 1080 {
lab=Y0}
N 80 1030 120 1030 {
lab=word17}
N 120 1030 160 1030 {
lab=word17}
N 90 1020 90 1070 {
lab=GND}
N 90 1070 90 1080 {
lab=GND}
N 150 1020 150 1070 {
lab=Y1}
N 150 1070 150 1080 {
lab=Y1}
N 160 1030 200 1030 {
lab=word17}
N 200 1030 240 1030 {
lab=word17}
N 170 1020 170 1070 {
lab=GND}
N 170 1070 170 1080 {
lab=GND}
N 230 1020 230 1070 {
lab=Y2}
N 230 1070 230 1080 {
lab=Y2}
N 250 1080 280 1080 {
lab=GND}
N 280 1070 280 1080 {
lab=GND}
N 240 1030 280 1030 {
lab=word17}
N 280 1030 320 1030 {
lab=word17}
N 250 1020 250 1070 {
lab=GND}
N 250 1070 250 1080 {
lab=GND}
N 310 1020 310 1070 {
lab=Y3}
N 310 1070 310 1080 {
lab=Y3}
N 330 1080 360 1080 {
lab=GND}
N 360 1070 360 1080 {
lab=GND}
N 320 1030 360 1030 {
lab=word17}
N 360 1030 400 1030 {
lab=word17}
N 330 1020 330 1070 {
lab=GND}
N 330 1070 330 1080 {
lab=GND}
N 390 1020 390 1070 {
lab=Y4}
N 390 1070 390 1080 {
lab=Y4}
N 410 1080 440 1080 {
lab=GND}
N 440 1070 440 1080 {
lab=GND}
N 400 1030 440 1030 {
lab=word17}
N 440 1030 480 1030 {
lab=word17}
N 410 1020 410 1070 {
lab=GND}
N 410 1070 410 1080 {
lab=GND}
N 470 1020 470 1070 {
lab=Y5}
N 470 1070 470 1080 {
lab=Y5}
N 490 1080 520 1080 {
lab=GND}
N 520 1070 520 1080 {
lab=GND}
N 480 1030 520 1030 {
lab=word17}
N 520 1030 560 1030 {
lab=word17}
N 490 1020 490 1070 {
lab=GND}
N 490 1070 490 1080 {
lab=GND}
N 550 1020 550 1070 {
lab=Y6}
N 550 1070 550 1080 {
lab=Y6}
N 570 1080 600 1080 {
lab=GND}
N 600 1070 600 1080 {
lab=GND}
N 560 1030 600 1030 {
lab=word17}
N 600 1030 640 1030 {
lab=word17}
N 570 1020 570 1070 {
lab=GND}
N 570 1070 570 1080 {
lab=GND}
N 630 1020 630 1070 {
lab=Y7}
N 630 1070 630 1080 {
lab=Y7}
N 0 1090 40 1090 {
lab=word18}
N 40 1090 80 1090 {
lab=word18}
N 10 1080 10 1130 {
lab=GND}
N 10 1130 10 1140 {
lab=GND}
N 70 1080 70 1130 {
lab=Y0}
N 70 1130 70 1140 {
lab=Y0}
N 80 1090 120 1090 {
lab=word18}
N 120 1090 160 1090 {
lab=word18}
N 90 1080 90 1130 {
lab=GND}
N 90 1130 90 1140 {
lab=GND}
N 150 1080 150 1130 {
lab=Y1}
N 150 1130 150 1140 {
lab=Y1}
N 170 1140 200 1140 {
lab=GND}
N 200 1130 200 1140 {
lab=GND}
N 160 1090 200 1090 {
lab=word18}
N 200 1090 240 1090 {
lab=word18}
N 170 1080 170 1130 {
lab=GND}
N 170 1130 170 1140 {
lab=GND}
N 230 1080 230 1130 {
lab=Y2}
N 230 1130 230 1140 {
lab=Y2}
N 250 1140 280 1140 {
lab=GND}
N 280 1130 280 1140 {
lab=GND}
N 240 1090 280 1090 {
lab=word18}
N 280 1090 320 1090 {
lab=word18}
N 250 1080 250 1130 {
lab=GND}
N 250 1130 250 1140 {
lab=GND}
N 310 1080 310 1130 {
lab=Y3}
N 310 1130 310 1140 {
lab=Y3}
N 330 1140 360 1140 {
lab=GND}
N 360 1130 360 1140 {
lab=GND}
N 320 1090 360 1090 {
lab=word18}
N 360 1090 400 1090 {
lab=word18}
N 330 1080 330 1130 {
lab=GND}
N 330 1130 330 1140 {
lab=GND}
N 390 1080 390 1130 {
lab=Y4}
N 390 1130 390 1140 {
lab=Y4}
N 410 1140 440 1140 {
lab=GND}
N 440 1130 440 1140 {
lab=GND}
N 400 1090 440 1090 {
lab=word18}
N 440 1090 480 1090 {
lab=word18}
N 410 1080 410 1130 {
lab=GND}
N 410 1130 410 1140 {
lab=GND}
N 470 1080 470 1130 {
lab=Y5}
N 470 1130 470 1140 {
lab=Y5}
N 490 1140 520 1140 {
lab=GND}
N 520 1130 520 1140 {
lab=GND}
N 480 1090 520 1090 {
lab=word18}
N 520 1090 560 1090 {
lab=word18}
N 490 1080 490 1130 {
lab=GND}
N 490 1130 490 1140 {
lab=GND}
N 550 1080 550 1130 {
lab=Y6}
N 550 1130 550 1140 {
lab=Y6}
N 570 1140 600 1140 {
lab=GND}
N 600 1130 600 1140 {
lab=GND}
N 560 1090 600 1090 {
lab=word18}
N 600 1090 640 1090 {
lab=word18}
N 570 1080 570 1130 {
lab=GND}
N 570 1130 570 1140 {
lab=GND}
N 630 1080 630 1130 {
lab=Y7}
N 630 1130 630 1140 {
lab=Y7}
N 0 1150 40 1150 {
lab=word19}
N 40 1150 80 1150 {
lab=word19}
N 10 1140 10 1190 {
lab=GND}
N 10 1190 10 1200 {
lab=GND}
N 70 1140 70 1190 {
lab=Y0}
N 70 1190 70 1200 {
lab=Y0}
N 90 1200 120 1200 {
lab=GND}
N 120 1190 120 1200 {
lab=GND}
N 80 1150 120 1150 {
lab=word19}
N 120 1150 160 1150 {
lab=word19}
N 90 1140 90 1190 {
lab=GND}
N 90 1190 90 1200 {
lab=GND}
N 150 1140 150 1190 {
lab=Y1}
N 150 1190 150 1200 {
lab=Y1}
N 160 1150 200 1150 {
lab=word19}
N 200 1150 240 1150 {
lab=word19}
N 170 1140 170 1190 {
lab=GND}
N 170 1190 170 1200 {
lab=GND}
N 230 1140 230 1190 {
lab=Y2}
N 230 1190 230 1200 {
lab=Y2}
N 250 1200 280 1200 {
lab=GND}
N 280 1190 280 1200 {
lab=GND}
N 240 1150 280 1150 {
lab=word19}
N 280 1150 320 1150 {
lab=word19}
N 250 1140 250 1190 {
lab=GND}
N 250 1190 250 1200 {
lab=GND}
N 310 1140 310 1190 {
lab=Y3}
N 310 1190 310 1200 {
lab=Y3}
N 330 1200 360 1200 {
lab=GND}
N 360 1190 360 1200 {
lab=GND}
N 320 1150 360 1150 {
lab=word19}
N 360 1150 400 1150 {
lab=word19}
N 330 1140 330 1190 {
lab=GND}
N 330 1190 330 1200 {
lab=GND}
N 390 1140 390 1190 {
lab=Y4}
N 390 1190 390 1200 {
lab=Y4}
N 410 1200 440 1200 {
lab=GND}
N 440 1190 440 1200 {
lab=GND}
N 400 1150 440 1150 {
lab=word19}
N 440 1150 480 1150 {
lab=word19}
N 410 1140 410 1190 {
lab=GND}
N 410 1190 410 1200 {
lab=GND}
N 470 1140 470 1190 {
lab=Y5}
N 470 1190 470 1200 {
lab=Y5}
N 490 1200 520 1200 {
lab=GND}
N 520 1190 520 1200 {
lab=GND}
N 480 1150 520 1150 {
lab=word19}
N 520 1150 560 1150 {
lab=word19}
N 490 1140 490 1190 {
lab=GND}
N 490 1190 490 1200 {
lab=GND}
N 550 1140 550 1190 {
lab=Y6}
N 550 1190 550 1200 {
lab=Y6}
N 570 1200 600 1200 {
lab=GND}
N 600 1190 600 1200 {
lab=GND}
N 560 1150 600 1150 {
lab=word19}
N 600 1150 640 1150 {
lab=word19}
N 570 1140 570 1190 {
lab=GND}
N 570 1190 570 1200 {
lab=GND}
N 630 1140 630 1190 {
lab=Y7}
N 630 1190 630 1200 {
lab=Y7}
N 0 1210 40 1210 {
lab=word20}
N 40 1210 80 1210 {
lab=word20}
N 10 1200 10 1250 {
lab=GND}
N 10 1250 10 1260 {
lab=GND}
N 70 1200 70 1250 {
lab=Y0}
N 70 1250 70 1260 {
lab=Y0}
N 90 1260 120 1260 {
lab=GND}
N 120 1250 120 1260 {
lab=GND}
N 80 1210 120 1210 {
lab=word20}
N 120 1210 160 1210 {
lab=word20}
N 90 1200 90 1250 {
lab=GND}
N 90 1250 90 1260 {
lab=GND}
N 150 1200 150 1250 {
lab=Y1}
N 150 1250 150 1260 {
lab=Y1}
N 170 1260 200 1260 {
lab=GND}
N 200 1250 200 1260 {
lab=GND}
N 160 1210 200 1210 {
lab=word20}
N 200 1210 240 1210 {
lab=word20}
N 170 1200 170 1250 {
lab=GND}
N 170 1250 170 1260 {
lab=GND}
N 230 1200 230 1250 {
lab=Y2}
N 230 1250 230 1260 {
lab=Y2}
N 250 1260 280 1260 {
lab=GND}
N 280 1250 280 1260 {
lab=GND}
N 240 1210 280 1210 {
lab=word20}
N 280 1210 320 1210 {
lab=word20}
N 250 1200 250 1250 {
lab=GND}
N 250 1250 250 1260 {
lab=GND}
N 310 1200 310 1250 {
lab=Y3}
N 310 1250 310 1260 {
lab=Y3}
N 330 1260 360 1260 {
lab=GND}
N 360 1250 360 1260 {
lab=GND}
N 320 1210 360 1210 {
lab=word20}
N 360 1210 400 1210 {
lab=word20}
N 330 1200 330 1250 {
lab=GND}
N 330 1250 330 1260 {
lab=GND}
N 390 1200 390 1250 {
lab=Y4}
N 390 1250 390 1260 {
lab=Y4}
N 410 1260 440 1260 {
lab=GND}
N 440 1250 440 1260 {
lab=GND}
N 400 1210 440 1210 {
lab=word20}
N 440 1210 480 1210 {
lab=word20}
N 410 1200 410 1250 {
lab=GND}
N 410 1250 410 1260 {
lab=GND}
N 470 1200 470 1250 {
lab=Y5}
N 470 1250 470 1260 {
lab=Y5}
N 490 1260 520 1260 {
lab=GND}
N 520 1250 520 1260 {
lab=GND}
N 480 1210 520 1210 {
lab=word20}
N 520 1210 560 1210 {
lab=word20}
N 490 1200 490 1250 {
lab=GND}
N 490 1250 490 1260 {
lab=GND}
N 550 1200 550 1250 {
lab=Y6}
N 550 1250 550 1260 {
lab=Y6}
N 570 1260 600 1260 {
lab=GND}
N 600 1250 600 1260 {
lab=GND}
N 560 1210 600 1210 {
lab=word20}
N 600 1210 640 1210 {
lab=word20}
N 570 1200 570 1250 {
lab=GND}
N 570 1250 570 1260 {
lab=GND}
N 630 1200 630 1250 {
lab=Y7}
N 630 1250 630 1260 {
lab=Y7}
N 10 1320 40 1320 {
lab=GND}
N 40 1310 40 1320 {
lab=GND}
N 0 1270 40 1270 {
lab=word21}
N 40 1270 80 1270 {
lab=word21}
N 10 1260 10 1310 {
lab=GND}
N 10 1310 10 1320 {
lab=GND}
N 70 1260 70 1310 {
lab=Y0}
N 70 1310 70 1320 {
lab=Y0}
N 80 1270 120 1270 {
lab=word21}
N 120 1270 160 1270 {
lab=word21}
N 90 1260 90 1310 {
lab=GND}
N 90 1310 90 1320 {
lab=GND}
N 150 1260 150 1310 {
lab=Y1}
N 150 1310 150 1320 {
lab=Y1}
N 160 1270 200 1270 {
lab=word21}
N 200 1270 240 1270 {
lab=word21}
N 170 1260 170 1310 {
lab=GND}
N 170 1310 170 1320 {
lab=GND}
N 230 1260 230 1310 {
lab=Y2}
N 230 1310 230 1320 {
lab=Y2}
N 250 1320 280 1320 {
lab=GND}
N 280 1310 280 1320 {
lab=GND}
N 240 1270 280 1270 {
lab=word21}
N 280 1270 320 1270 {
lab=word21}
N 250 1260 250 1310 {
lab=GND}
N 250 1310 250 1320 {
lab=GND}
N 310 1260 310 1310 {
lab=Y3}
N 310 1310 310 1320 {
lab=Y3}
N 330 1320 360 1320 {
lab=GND}
N 360 1310 360 1320 {
lab=GND}
N 320 1270 360 1270 {
lab=word21}
N 360 1270 400 1270 {
lab=word21}
N 330 1260 330 1310 {
lab=GND}
N 330 1310 330 1320 {
lab=GND}
N 390 1260 390 1310 {
lab=Y4}
N 390 1310 390 1320 {
lab=Y4}
N 410 1320 440 1320 {
lab=GND}
N 440 1310 440 1320 {
lab=GND}
N 400 1270 440 1270 {
lab=word21}
N 440 1270 480 1270 {
lab=word21}
N 410 1260 410 1310 {
lab=GND}
N 410 1310 410 1320 {
lab=GND}
N 470 1260 470 1310 {
lab=Y5}
N 470 1310 470 1320 {
lab=Y5}
N 490 1320 520 1320 {
lab=GND}
N 520 1310 520 1320 {
lab=GND}
N 480 1270 520 1270 {
lab=word21}
N 520 1270 560 1270 {
lab=word21}
N 490 1260 490 1310 {
lab=GND}
N 490 1310 490 1320 {
lab=GND}
N 550 1260 550 1310 {
lab=Y6}
N 550 1310 550 1320 {
lab=Y6}
N 570 1320 600 1320 {
lab=GND}
N 600 1310 600 1320 {
lab=GND}
N 560 1270 600 1270 {
lab=word21}
N 600 1270 640 1270 {
lab=word21}
N 570 1260 570 1310 {
lab=GND}
N 570 1310 570 1320 {
lab=GND}
N 630 1260 630 1310 {
lab=Y7}
N 630 1310 630 1320 {
lab=Y7}
N 10 1380 40 1380 {
lab=GND}
N 40 1370 40 1380 {
lab=GND}
N 0 1330 40 1330 {
lab=word22}
N 40 1330 80 1330 {
lab=word22}
N 10 1320 10 1370 {
lab=GND}
N 10 1370 10 1380 {
lab=GND}
N 70 1320 70 1370 {
lab=Y0}
N 70 1370 70 1380 {
lab=Y0}
N 80 1330 120 1330 {
lab=word22}
N 120 1330 160 1330 {
lab=word22}
N 90 1320 90 1370 {
lab=GND}
N 90 1370 90 1380 {
lab=GND}
N 150 1320 150 1370 {
lab=Y1}
N 150 1370 150 1380 {
lab=Y1}
N 170 1380 200 1380 {
lab=GND}
N 200 1370 200 1380 {
lab=GND}
N 160 1330 200 1330 {
lab=word22}
N 200 1330 240 1330 {
lab=word22}
N 170 1320 170 1370 {
lab=GND}
N 170 1370 170 1380 {
lab=GND}
N 230 1320 230 1370 {
lab=Y2}
N 230 1370 230 1380 {
lab=Y2}
N 250 1380 280 1380 {
lab=GND}
N 280 1370 280 1380 {
lab=GND}
N 240 1330 280 1330 {
lab=word22}
N 280 1330 320 1330 {
lab=word22}
N 250 1320 250 1370 {
lab=GND}
N 250 1370 250 1380 {
lab=GND}
N 310 1320 310 1370 {
lab=Y3}
N 310 1370 310 1380 {
lab=Y3}
N 330 1380 360 1380 {
lab=GND}
N 360 1370 360 1380 {
lab=GND}
N 320 1330 360 1330 {
lab=word22}
N 360 1330 400 1330 {
lab=word22}
N 330 1320 330 1370 {
lab=GND}
N 330 1370 330 1380 {
lab=GND}
N 390 1320 390 1370 {
lab=Y4}
N 390 1370 390 1380 {
lab=Y4}
N 410 1380 440 1380 {
lab=GND}
N 440 1370 440 1380 {
lab=GND}
N 400 1330 440 1330 {
lab=word22}
N 440 1330 480 1330 {
lab=word22}
N 410 1320 410 1370 {
lab=GND}
N 410 1370 410 1380 {
lab=GND}
N 470 1320 470 1370 {
lab=Y5}
N 470 1370 470 1380 {
lab=Y5}
N 490 1380 520 1380 {
lab=GND}
N 520 1370 520 1380 {
lab=GND}
N 480 1330 520 1330 {
lab=word22}
N 520 1330 560 1330 {
lab=word22}
N 490 1320 490 1370 {
lab=GND}
N 490 1370 490 1380 {
lab=GND}
N 550 1320 550 1370 {
lab=Y6}
N 550 1370 550 1380 {
lab=Y6}
N 570 1380 600 1380 {
lab=GND}
N 600 1370 600 1380 {
lab=GND}
N 560 1330 600 1330 {
lab=word22}
N 600 1330 640 1330 {
lab=word22}
N 570 1320 570 1370 {
lab=GND}
N 570 1370 570 1380 {
lab=GND}
N 630 1320 630 1370 {
lab=Y7}
N 630 1370 630 1380 {
lab=Y7}
N 10 1440 40 1440 {
lab=GND}
N 40 1430 40 1440 {
lab=GND}
N 0 1390 40 1390 {
lab=word23}
N 40 1390 80 1390 {
lab=word23}
N 10 1380 10 1430 {
lab=GND}
N 10 1430 10 1440 {
lab=GND}
N 70 1380 70 1430 {
lab=Y0}
N 70 1430 70 1440 {
lab=Y0}
N 90 1440 120 1440 {
lab=GND}
N 120 1430 120 1440 {
lab=GND}
N 80 1390 120 1390 {
lab=word23}
N 120 1390 160 1390 {
lab=word23}
N 90 1380 90 1430 {
lab=GND}
N 90 1430 90 1440 {
lab=GND}
N 150 1380 150 1430 {
lab=Y1}
N 150 1430 150 1440 {
lab=Y1}
N 160 1390 200 1390 {
lab=word23}
N 200 1390 240 1390 {
lab=word23}
N 170 1380 170 1430 {
lab=GND}
N 170 1430 170 1440 {
lab=GND}
N 230 1380 230 1430 {
lab=Y2}
N 230 1430 230 1440 {
lab=Y2}
N 250 1440 280 1440 {
lab=GND}
N 280 1430 280 1440 {
lab=GND}
N 240 1390 280 1390 {
lab=word23}
N 280 1390 320 1390 {
lab=word23}
N 250 1380 250 1430 {
lab=GND}
N 250 1430 250 1440 {
lab=GND}
N 310 1380 310 1430 {
lab=Y3}
N 310 1430 310 1440 {
lab=Y3}
N 330 1440 360 1440 {
lab=GND}
N 360 1430 360 1440 {
lab=GND}
N 320 1390 360 1390 {
lab=word23}
N 360 1390 400 1390 {
lab=word23}
N 330 1380 330 1430 {
lab=GND}
N 330 1430 330 1440 {
lab=GND}
N 390 1380 390 1430 {
lab=Y4}
N 390 1430 390 1440 {
lab=Y4}
N 410 1440 440 1440 {
lab=GND}
N 440 1430 440 1440 {
lab=GND}
N 400 1390 440 1390 {
lab=word23}
N 440 1390 480 1390 {
lab=word23}
N 410 1380 410 1430 {
lab=GND}
N 410 1430 410 1440 {
lab=GND}
N 470 1380 470 1430 {
lab=Y5}
N 470 1430 470 1440 {
lab=Y5}
N 490 1440 520 1440 {
lab=GND}
N 520 1430 520 1440 {
lab=GND}
N 480 1390 520 1390 {
lab=word23}
N 520 1390 560 1390 {
lab=word23}
N 490 1380 490 1430 {
lab=GND}
N 490 1430 490 1440 {
lab=GND}
N 550 1380 550 1430 {
lab=Y6}
N 550 1430 550 1440 {
lab=Y6}
N 570 1440 600 1440 {
lab=GND}
N 600 1430 600 1440 {
lab=GND}
N 560 1390 600 1390 {
lab=word23}
N 600 1390 640 1390 {
lab=word23}
N 570 1380 570 1430 {
lab=GND}
N 570 1430 570 1440 {
lab=GND}
N 630 1380 630 1430 {
lab=Y7}
N 630 1430 630 1440 {
lab=Y7}
N 10 1500 40 1500 {
lab=GND}
N 40 1490 40 1500 {
lab=GND}
N 0 1450 40 1450 {
lab=word24}
N 40 1450 80 1450 {
lab=word24}
N 10 1440 10 1490 {
lab=GND}
N 10 1490 10 1500 {
lab=GND}
N 70 1440 70 1490 {
lab=Y0}
N 70 1490 70 1500 {
lab=Y0}
N 90 1500 120 1500 {
lab=GND}
N 120 1490 120 1500 {
lab=GND}
N 80 1450 120 1450 {
lab=word24}
N 120 1450 160 1450 {
lab=word24}
N 90 1440 90 1490 {
lab=GND}
N 90 1490 90 1500 {
lab=GND}
N 150 1440 150 1490 {
lab=Y1}
N 150 1490 150 1500 {
lab=Y1}
N 170 1500 200 1500 {
lab=GND}
N 200 1490 200 1500 {
lab=GND}
N 160 1450 200 1450 {
lab=word24}
N 200 1450 240 1450 {
lab=word24}
N 170 1440 170 1490 {
lab=GND}
N 170 1490 170 1500 {
lab=GND}
N 230 1440 230 1490 {
lab=Y2}
N 230 1490 230 1500 {
lab=Y2}
N 250 1500 280 1500 {
lab=GND}
N 280 1490 280 1500 {
lab=GND}
N 240 1450 280 1450 {
lab=word24}
N 280 1450 320 1450 {
lab=word24}
N 250 1440 250 1490 {
lab=GND}
N 250 1490 250 1500 {
lab=GND}
N 310 1440 310 1490 {
lab=Y3}
N 310 1490 310 1500 {
lab=Y3}
N 330 1500 360 1500 {
lab=GND}
N 360 1490 360 1500 {
lab=GND}
N 320 1450 360 1450 {
lab=word24}
N 360 1450 400 1450 {
lab=word24}
N 330 1440 330 1490 {
lab=GND}
N 330 1490 330 1500 {
lab=GND}
N 390 1440 390 1490 {
lab=Y4}
N 390 1490 390 1500 {
lab=Y4}
N 410 1500 440 1500 {
lab=GND}
N 440 1490 440 1500 {
lab=GND}
N 400 1450 440 1450 {
lab=word24}
N 440 1450 480 1450 {
lab=word24}
N 410 1440 410 1490 {
lab=GND}
N 410 1490 410 1500 {
lab=GND}
N 470 1440 470 1490 {
lab=Y5}
N 470 1490 470 1500 {
lab=Y5}
N 490 1500 520 1500 {
lab=GND}
N 520 1490 520 1500 {
lab=GND}
N 480 1450 520 1450 {
lab=word24}
N 520 1450 560 1450 {
lab=word24}
N 490 1440 490 1490 {
lab=GND}
N 490 1490 490 1500 {
lab=GND}
N 550 1440 550 1490 {
lab=Y6}
N 550 1490 550 1500 {
lab=Y6}
N 570 1500 600 1500 {
lab=GND}
N 600 1490 600 1500 {
lab=GND}
N 560 1450 600 1450 {
lab=word24}
N 600 1450 640 1450 {
lab=word24}
N 570 1440 570 1490 {
lab=GND}
N 570 1490 570 1500 {
lab=GND}
N 630 1440 630 1490 {
lab=Y7}
N 630 1490 630 1500 {
lab=Y7}
N 10 1560 40 1560 {
lab=GND}
N 40 1550 40 1560 {
lab=GND}
N 0 1510 40 1510 {
lab=word25}
N 40 1510 80 1510 {
lab=word25}
N 10 1500 10 1550 {
lab=GND}
N 10 1550 10 1560 {
lab=GND}
N 70 1500 70 1550 {
lab=Y0}
N 70 1550 70 1560 {
lab=Y0}
N 90 1560 120 1560 {
lab=GND}
N 120 1550 120 1560 {
lab=GND}
N 80 1510 120 1510 {
lab=word25}
N 120 1510 160 1510 {
lab=word25}
N 90 1500 90 1550 {
lab=GND}
N 90 1550 90 1560 {
lab=GND}
N 150 1500 150 1550 {
lab=Y1}
N 150 1550 150 1560 {
lab=Y1}
N 160 1510 200 1510 {
lab=word25}
N 200 1510 240 1510 {
lab=word25}
N 170 1500 170 1550 {
lab=GND}
N 170 1550 170 1560 {
lab=GND}
N 230 1500 230 1550 {
lab=Y2}
N 230 1550 230 1560 {
lab=Y2}
N 250 1560 280 1560 {
lab=GND}
N 280 1550 280 1560 {
lab=GND}
N 240 1510 280 1510 {
lab=word25}
N 280 1510 320 1510 {
lab=word25}
N 250 1500 250 1550 {
lab=GND}
N 250 1550 250 1560 {
lab=GND}
N 310 1500 310 1550 {
lab=Y3}
N 310 1550 310 1560 {
lab=Y3}
N 330 1560 360 1560 {
lab=GND}
N 360 1550 360 1560 {
lab=GND}
N 320 1510 360 1510 {
lab=word25}
N 360 1510 400 1510 {
lab=word25}
N 330 1500 330 1550 {
lab=GND}
N 330 1550 330 1560 {
lab=GND}
N 390 1500 390 1550 {
lab=Y4}
N 390 1550 390 1560 {
lab=Y4}
N 410 1560 440 1560 {
lab=GND}
N 440 1550 440 1560 {
lab=GND}
N 400 1510 440 1510 {
lab=word25}
N 440 1510 480 1510 {
lab=word25}
N 410 1500 410 1550 {
lab=GND}
N 410 1550 410 1560 {
lab=GND}
N 470 1500 470 1550 {
lab=Y5}
N 470 1550 470 1560 {
lab=Y5}
N 490 1560 520 1560 {
lab=GND}
N 520 1550 520 1560 {
lab=GND}
N 480 1510 520 1510 {
lab=word25}
N 520 1510 560 1510 {
lab=word25}
N 490 1500 490 1550 {
lab=GND}
N 490 1550 490 1560 {
lab=GND}
N 550 1500 550 1550 {
lab=Y6}
N 550 1550 550 1560 {
lab=Y6}
N 570 1560 600 1560 {
lab=GND}
N 600 1550 600 1560 {
lab=GND}
N 560 1510 600 1510 {
lab=word25}
N 600 1510 640 1510 {
lab=word25}
N 570 1500 570 1550 {
lab=GND}
N 570 1550 570 1560 {
lab=GND}
N 630 1500 630 1550 {
lab=Y7}
N 630 1550 630 1560 {
lab=Y7}
N 10 1620 40 1620 {
lab=GND}
N 40 1610 40 1620 {
lab=GND}
N 0 1570 40 1570 {
lab=word26}
N 40 1570 80 1570 {
lab=word26}
N 10 1560 10 1610 {
lab=GND}
N 10 1610 10 1620 {
lab=GND}
N 70 1560 70 1610 {
lab=Y0}
N 70 1610 70 1620 {
lab=Y0}
N 80 1570 120 1570 {
lab=word26}
N 120 1570 160 1570 {
lab=word26}
N 90 1560 90 1610 {
lab=GND}
N 90 1610 90 1620 {
lab=GND}
N 150 1560 150 1610 {
lab=Y1}
N 150 1610 150 1620 {
lab=Y1}
N 170 1620 200 1620 {
lab=GND}
N 200 1610 200 1620 {
lab=GND}
N 160 1570 200 1570 {
lab=word26}
N 200 1570 240 1570 {
lab=word26}
N 170 1560 170 1610 {
lab=GND}
N 170 1610 170 1620 {
lab=GND}
N 230 1560 230 1610 {
lab=Y2}
N 230 1610 230 1620 {
lab=Y2}
N 250 1620 280 1620 {
lab=GND}
N 280 1610 280 1620 {
lab=GND}
N 240 1570 280 1570 {
lab=word26}
N 280 1570 320 1570 {
lab=word26}
N 250 1560 250 1610 {
lab=GND}
N 250 1610 250 1620 {
lab=GND}
N 310 1560 310 1610 {
lab=Y3}
N 310 1610 310 1620 {
lab=Y3}
N 330 1620 360 1620 {
lab=GND}
N 360 1610 360 1620 {
lab=GND}
N 320 1570 360 1570 {
lab=word26}
N 360 1570 400 1570 {
lab=word26}
N 330 1560 330 1610 {
lab=GND}
N 330 1610 330 1620 {
lab=GND}
N 390 1560 390 1610 {
lab=Y4}
N 390 1610 390 1620 {
lab=Y4}
N 410 1620 440 1620 {
lab=GND}
N 440 1610 440 1620 {
lab=GND}
N 400 1570 440 1570 {
lab=word26}
N 440 1570 480 1570 {
lab=word26}
N 410 1560 410 1610 {
lab=GND}
N 410 1610 410 1620 {
lab=GND}
N 470 1560 470 1610 {
lab=Y5}
N 470 1610 470 1620 {
lab=Y5}
N 490 1620 520 1620 {
lab=GND}
N 520 1610 520 1620 {
lab=GND}
N 480 1570 520 1570 {
lab=word26}
N 520 1570 560 1570 {
lab=word26}
N 490 1560 490 1610 {
lab=GND}
N 490 1610 490 1620 {
lab=GND}
N 550 1560 550 1610 {
lab=Y6}
N 550 1610 550 1620 {
lab=Y6}
N 570 1620 600 1620 {
lab=GND}
N 600 1610 600 1620 {
lab=GND}
N 560 1570 600 1570 {
lab=word26}
N 600 1570 640 1570 {
lab=word26}
N 570 1560 570 1610 {
lab=GND}
N 570 1610 570 1620 {
lab=GND}
N 630 1560 630 1610 {
lab=Y7}
N 630 1610 630 1620 {
lab=Y7}
N 10 1680 40 1680 {
lab=GND}
N 40 1670 40 1680 {
lab=GND}
N 0 1630 40 1630 {
lab=word27}
N 40 1630 80 1630 {
lab=word27}
N 10 1620 10 1670 {
lab=GND}
N 10 1670 10 1680 {
lab=GND}
N 70 1620 70 1670 {
lab=Y0}
N 70 1670 70 1680 {
lab=Y0}
N 80 1630 120 1630 {
lab=word27}
N 120 1630 160 1630 {
lab=word27}
N 90 1620 90 1670 {
lab=GND}
N 90 1670 90 1680 {
lab=GND}
N 150 1620 150 1670 {
lab=Y1}
N 150 1670 150 1680 {
lab=Y1}
N 160 1630 200 1630 {
lab=word27}
N 200 1630 240 1630 {
lab=word27}
N 170 1620 170 1670 {
lab=GND}
N 170 1670 170 1680 {
lab=GND}
N 230 1620 230 1670 {
lab=Y2}
N 230 1670 230 1680 {
lab=Y2}
N 250 1680 280 1680 {
lab=GND}
N 280 1670 280 1680 {
lab=GND}
N 240 1630 280 1630 {
lab=word27}
N 280 1630 320 1630 {
lab=word27}
N 250 1620 250 1670 {
lab=GND}
N 250 1670 250 1680 {
lab=GND}
N 310 1620 310 1670 {
lab=Y3}
N 310 1670 310 1680 {
lab=Y3}
N 330 1680 360 1680 {
lab=GND}
N 360 1670 360 1680 {
lab=GND}
N 320 1630 360 1630 {
lab=word27}
N 360 1630 400 1630 {
lab=word27}
N 330 1620 330 1670 {
lab=GND}
N 330 1670 330 1680 {
lab=GND}
N 390 1620 390 1670 {
lab=Y4}
N 390 1670 390 1680 {
lab=Y4}
N 410 1680 440 1680 {
lab=GND}
N 440 1670 440 1680 {
lab=GND}
N 400 1630 440 1630 {
lab=word27}
N 440 1630 480 1630 {
lab=word27}
N 410 1620 410 1670 {
lab=GND}
N 410 1670 410 1680 {
lab=GND}
N 470 1620 470 1670 {
lab=Y5}
N 470 1670 470 1680 {
lab=Y5}
N 490 1680 520 1680 {
lab=GND}
N 520 1670 520 1680 {
lab=GND}
N 480 1630 520 1630 {
lab=word27}
N 520 1630 560 1630 {
lab=word27}
N 490 1620 490 1670 {
lab=GND}
N 490 1670 490 1680 {
lab=GND}
N 550 1620 550 1670 {
lab=Y6}
N 550 1670 550 1680 {
lab=Y6}
N 570 1680 600 1680 {
lab=GND}
N 600 1670 600 1680 {
lab=GND}
N 560 1630 600 1630 {
lab=word27}
N 600 1630 640 1630 {
lab=word27}
N 570 1620 570 1670 {
lab=GND}
N 570 1670 570 1680 {
lab=GND}
N 630 1620 630 1670 {
lab=Y7}
N 630 1670 630 1680 {
lab=Y7}
N 0 1690 40 1690 {
lab=word28}
N 40 1690 80 1690 {
lab=word28}
N 10 1680 10 1730 {
lab=GND}
N 10 1730 10 1740 {
lab=GND}
N 70 1680 70 1730 {
lab=Y0}
N 70 1730 70 1740 {
lab=Y0}
N 90 1740 120 1740 {
lab=GND}
N 120 1730 120 1740 {
lab=GND}
N 80 1690 120 1690 {
lab=word28}
N 120 1690 160 1690 {
lab=word28}
N 90 1680 90 1730 {
lab=GND}
N 90 1730 90 1740 {
lab=GND}
N 150 1680 150 1730 {
lab=Y1}
N 150 1730 150 1740 {
lab=Y1}
N 170 1740 200 1740 {
lab=GND}
N 200 1730 200 1740 {
lab=GND}
N 160 1690 200 1690 {
lab=word28}
N 200 1690 240 1690 {
lab=word28}
N 170 1680 170 1730 {
lab=GND}
N 170 1730 170 1740 {
lab=GND}
N 230 1680 230 1730 {
lab=Y2}
N 230 1730 230 1740 {
lab=Y2}
N 250 1740 280 1740 {
lab=GND}
N 280 1730 280 1740 {
lab=GND}
N 240 1690 280 1690 {
lab=word28}
N 280 1690 320 1690 {
lab=word28}
N 250 1680 250 1730 {
lab=GND}
N 250 1730 250 1740 {
lab=GND}
N 310 1680 310 1730 {
lab=Y3}
N 310 1730 310 1740 {
lab=Y3}
N 330 1740 360 1740 {
lab=GND}
N 360 1730 360 1740 {
lab=GND}
N 320 1690 360 1690 {
lab=word28}
N 360 1690 400 1690 {
lab=word28}
N 330 1680 330 1730 {
lab=GND}
N 330 1730 330 1740 {
lab=GND}
N 390 1680 390 1730 {
lab=Y4}
N 390 1730 390 1740 {
lab=Y4}
N 410 1740 440 1740 {
lab=GND}
N 440 1730 440 1740 {
lab=GND}
N 400 1690 440 1690 {
lab=word28}
N 440 1690 480 1690 {
lab=word28}
N 410 1680 410 1730 {
lab=GND}
N 410 1730 410 1740 {
lab=GND}
N 470 1680 470 1730 {
lab=Y5}
N 470 1730 470 1740 {
lab=Y5}
N 490 1740 520 1740 {
lab=GND}
N 520 1730 520 1740 {
lab=GND}
N 480 1690 520 1690 {
lab=word28}
N 520 1690 560 1690 {
lab=word28}
N 490 1680 490 1730 {
lab=GND}
N 490 1730 490 1740 {
lab=GND}
N 550 1680 550 1730 {
lab=Y6}
N 550 1730 550 1740 {
lab=Y6}
N 570 1740 600 1740 {
lab=GND}
N 600 1730 600 1740 {
lab=GND}
N 560 1690 600 1690 {
lab=word28}
N 600 1690 640 1690 {
lab=word28}
N 570 1680 570 1730 {
lab=GND}
N 570 1730 570 1740 {
lab=GND}
N 630 1680 630 1730 {
lab=Y7}
N 630 1730 630 1740 {
lab=Y7}
N 0 1750 40 1750 {
lab=word29}
N 40 1750 80 1750 {
lab=word29}
N 10 1740 10 1790 {
lab=GND}
N 10 1790 10 1800 {
lab=GND}
N 70 1740 70 1790 {
lab=Y0}
N 70 1790 70 1800 {
lab=Y0}
N 90 1800 120 1800 {
lab=GND}
N 120 1790 120 1800 {
lab=GND}
N 80 1750 120 1750 {
lab=word29}
N 120 1750 160 1750 {
lab=word29}
N 90 1740 90 1790 {
lab=GND}
N 90 1790 90 1800 {
lab=GND}
N 150 1740 150 1790 {
lab=Y1}
N 150 1790 150 1800 {
lab=Y1}
N 160 1750 200 1750 {
lab=word29}
N 200 1750 240 1750 {
lab=word29}
N 170 1740 170 1790 {
lab=GND}
N 170 1790 170 1800 {
lab=GND}
N 230 1740 230 1790 {
lab=Y2}
N 230 1790 230 1800 {
lab=Y2}
N 250 1800 280 1800 {
lab=GND}
N 280 1790 280 1800 {
lab=GND}
N 240 1750 280 1750 {
lab=word29}
N 280 1750 320 1750 {
lab=word29}
N 250 1740 250 1790 {
lab=GND}
N 250 1790 250 1800 {
lab=GND}
N 310 1740 310 1790 {
lab=Y3}
N 310 1790 310 1800 {
lab=Y3}
N 330 1800 360 1800 {
lab=GND}
N 360 1790 360 1800 {
lab=GND}
N 320 1750 360 1750 {
lab=word29}
N 360 1750 400 1750 {
lab=word29}
N 330 1740 330 1790 {
lab=GND}
N 330 1790 330 1800 {
lab=GND}
N 390 1740 390 1790 {
lab=Y4}
N 390 1790 390 1800 {
lab=Y4}
N 410 1800 440 1800 {
lab=GND}
N 440 1790 440 1800 {
lab=GND}
N 400 1750 440 1750 {
lab=word29}
N 440 1750 480 1750 {
lab=word29}
N 410 1740 410 1790 {
lab=GND}
N 410 1790 410 1800 {
lab=GND}
N 470 1740 470 1790 {
lab=Y5}
N 470 1790 470 1800 {
lab=Y5}
N 490 1800 520 1800 {
lab=GND}
N 520 1790 520 1800 {
lab=GND}
N 480 1750 520 1750 {
lab=word29}
N 520 1750 560 1750 {
lab=word29}
N 490 1740 490 1790 {
lab=GND}
N 490 1790 490 1800 {
lab=GND}
N 550 1740 550 1790 {
lab=Y6}
N 550 1790 550 1800 {
lab=Y6}
N 570 1800 600 1800 {
lab=GND}
N 600 1790 600 1800 {
lab=GND}
N 560 1750 600 1750 {
lab=word29}
N 600 1750 640 1750 {
lab=word29}
N 570 1740 570 1790 {
lab=GND}
N 570 1790 570 1800 {
lab=GND}
N 630 1740 630 1790 {
lab=Y7}
N 630 1790 630 1800 {
lab=Y7}
N 0 1810 40 1810 {
lab=word30}
N 40 1810 80 1810 {
lab=word30}
N 10 1800 10 1850 {
lab=GND}
N 10 1850 10 1860 {
lab=GND}
N 70 1800 70 1850 {
lab=Y0}
N 70 1850 70 1860 {
lab=Y0}
N 80 1810 120 1810 {
lab=word30}
N 120 1810 160 1810 {
lab=word30}
N 90 1800 90 1850 {
lab=GND}
N 90 1850 90 1860 {
lab=GND}
N 150 1800 150 1850 {
lab=Y1}
N 150 1850 150 1860 {
lab=Y1}
N 170 1860 200 1860 {
lab=GND}
N 200 1850 200 1860 {
lab=GND}
N 160 1810 200 1810 {
lab=word30}
N 200 1810 240 1810 {
lab=word30}
N 170 1800 170 1850 {
lab=GND}
N 170 1850 170 1860 {
lab=GND}
N 230 1800 230 1850 {
lab=Y2}
N 230 1850 230 1860 {
lab=Y2}
N 250 1860 280 1860 {
lab=GND}
N 280 1850 280 1860 {
lab=GND}
N 240 1810 280 1810 {
lab=word30}
N 280 1810 320 1810 {
lab=word30}
N 250 1800 250 1850 {
lab=GND}
N 250 1850 250 1860 {
lab=GND}
N 310 1800 310 1850 {
lab=Y3}
N 310 1850 310 1860 {
lab=Y3}
N 330 1860 360 1860 {
lab=GND}
N 360 1850 360 1860 {
lab=GND}
N 320 1810 360 1810 {
lab=word30}
N 360 1810 400 1810 {
lab=word30}
N 330 1800 330 1850 {
lab=GND}
N 330 1850 330 1860 {
lab=GND}
N 390 1800 390 1850 {
lab=Y4}
N 390 1850 390 1860 {
lab=Y4}
N 410 1860 440 1860 {
lab=GND}
N 440 1850 440 1860 {
lab=GND}
N 400 1810 440 1810 {
lab=word30}
N 440 1810 480 1810 {
lab=word30}
N 410 1800 410 1850 {
lab=GND}
N 410 1850 410 1860 {
lab=GND}
N 470 1800 470 1850 {
lab=Y5}
N 470 1850 470 1860 {
lab=Y5}
N 490 1860 520 1860 {
lab=GND}
N 520 1850 520 1860 {
lab=GND}
N 480 1810 520 1810 {
lab=word30}
N 520 1810 560 1810 {
lab=word30}
N 490 1800 490 1850 {
lab=GND}
N 490 1850 490 1860 {
lab=GND}
N 550 1800 550 1850 {
lab=Y6}
N 550 1850 550 1860 {
lab=Y6}
N 570 1860 600 1860 {
lab=GND}
N 600 1850 600 1860 {
lab=GND}
N 560 1810 600 1810 {
lab=word30}
N 600 1810 640 1810 {
lab=word30}
N 570 1800 570 1850 {
lab=GND}
N 570 1850 570 1860 {
lab=GND}
N 630 1800 630 1850 {
lab=Y7}
N 630 1850 630 1860 {
lab=Y7}
N 0 1870 40 1870 {
lab=word31}
N 40 1870 80 1870 {
lab=word31}
N 10 1860 10 1910 {
lab=GND}
N 10 1910 10 1920 {
lab=GND}
N 70 1860 70 1910 {
lab=Y0}
N 70 1910 70 1920 {
lab=Y0}
N 80 1870 120 1870 {
lab=word31}
N 120 1870 160 1870 {
lab=word31}
N 90 1860 90 1910 {
lab=GND}
N 90 1910 90 1920 {
lab=GND}
N 150 1860 150 1910 {
lab=Y1}
N 150 1910 150 1920 {
lab=Y1}
N 160 1870 200 1870 {
lab=word31}
N 200 1870 240 1870 {
lab=word31}
N 170 1860 170 1910 {
lab=GND}
N 170 1910 170 1920 {
lab=GND}
N 230 1860 230 1910 {
lab=Y2}
N 230 1910 230 1920 {
lab=Y2}
N 250 1920 280 1920 {
lab=GND}
N 280 1910 280 1920 {
lab=GND}
N 240 1870 280 1870 {
lab=word31}
N 280 1870 320 1870 {
lab=word31}
N 250 1860 250 1910 {
lab=GND}
N 250 1910 250 1920 {
lab=GND}
N 310 1860 310 1910 {
lab=Y3}
N 310 1910 310 1920 {
lab=Y3}
N 330 1920 360 1920 {
lab=GND}
N 360 1910 360 1920 {
lab=GND}
N 320 1870 360 1870 {
lab=word31}
N 360 1870 400 1870 {
lab=word31}
N 330 1860 330 1910 {
lab=GND}
N 330 1910 330 1920 {
lab=GND}
N 390 1860 390 1910 {
lab=Y4}
N 390 1910 390 1920 {
lab=Y4}
N 410 1920 440 1920 {
lab=GND}
N 440 1910 440 1920 {
lab=GND}
N 400 1870 440 1870 {
lab=word31}
N 440 1870 480 1870 {
lab=word31}
N 410 1860 410 1910 {
lab=GND}
N 410 1910 410 1920 {
lab=GND}
N 470 1860 470 1910 {
lab=Y5}
N 470 1910 470 1920 {
lab=Y5}
N 490 1920 520 1920 {
lab=GND}
N 520 1910 520 1920 {
lab=GND}
N 480 1870 520 1870 {
lab=word31}
N 520 1870 560 1870 {
lab=word31}
N 490 1860 490 1910 {
lab=GND}
N 490 1910 490 1920 {
lab=GND}
N 550 1860 550 1910 {
lab=Y6}
N 550 1910 550 1920 {
lab=Y6}
N 570 1920 600 1920 {
lab=GND}
N 600 1910 600 1920 {
lab=GND}
N 560 1870 600 1870 {
lab=word31}
N 600 1870 640 1870 {
lab=word31}
N 570 1860 570 1910 {
lab=GND}
N 570 1910 570 1920 {
lab=GND}
N 630 1860 630 1910 {
lab=Y7}
N 630 1910 630 1920 {
lab=Y7}
N 0 1930 40 1930 {
lab=word32}
N 40 1930 80 1930 {
lab=word32}
N 10 1920 10 1970 {
lab=GND}
N 10 1970 10 1980 {
lab=GND}
N 70 1920 70 1970 {
lab=Y0}
N 70 1970 70 1980 {
lab=Y0}
N 80 1930 120 1930 {
lab=word32}
N 120 1930 160 1930 {
lab=word32}
N 90 1920 90 1970 {
lab=GND}
N 90 1970 90 1980 {
lab=GND}
N 150 1920 150 1970 {
lab=Y1}
N 150 1970 150 1980 {
lab=Y1}
N 160 1930 200 1930 {
lab=word32}
N 200 1930 240 1930 {
lab=word32}
N 170 1920 170 1970 {
lab=GND}
N 170 1970 170 1980 {
lab=GND}
N 230 1920 230 1970 {
lab=Y2}
N 230 1970 230 1980 {
lab=Y2}
N 240 1930 280 1930 {
lab=word32}
N 280 1930 320 1930 {
lab=word32}
N 250 1920 250 1970 {
lab=GND}
N 250 1970 250 1980 {
lab=GND}
N 310 1920 310 1970 {
lab=Y3}
N 310 1970 310 1980 {
lab=Y3}
N 320 1930 360 1930 {
lab=word32}
N 360 1930 400 1930 {
lab=word32}
N 330 1920 330 1970 {
lab=GND}
N 330 1970 330 1980 {
lab=GND}
N 390 1920 390 1970 {
lab=Y4}
N 390 1970 390 1980 {
lab=Y4}
N 400 1930 440 1930 {
lab=word32}
N 440 1930 480 1930 {
lab=word32}
N 410 1920 410 1970 {
lab=GND}
N 410 1970 410 1980 {
lab=GND}
N 470 1920 470 1970 {
lab=Y5}
N 470 1970 470 1980 {
lab=Y5}
N 480 1930 520 1930 {
lab=word32}
N 520 1930 560 1930 {
lab=word32}
N 490 1920 490 1970 {
lab=GND}
N 490 1970 490 1980 {
lab=GND}
N 550 1920 550 1970 {
lab=Y6}
N 550 1970 550 1980 {
lab=Y6}
N 560 1930 600 1930 {
lab=word32}
N 600 1930 640 1930 {
lab=word32}
N 570 1920 570 1970 {
lab=GND}
N 570 1970 570 1980 {
lab=GND}
N 630 1920 630 1970 {
lab=Y7}
N 630 1970 630 1980 {
lab=Y7}
N 0 1990 40 1990 {
lab=word33}
N 40 1990 80 1990 {
lab=word33}
N 10 1980 10 2030 {
lab=GND}
N 10 2030 10 2040 {
lab=GND}
N 70 1980 70 2030 {
lab=Y0}
N 70 2030 70 2040 {
lab=Y0}
N 80 1990 120 1990 {
lab=word33}
N 120 1990 160 1990 {
lab=word33}
N 90 1980 90 2030 {
lab=GND}
N 90 2030 90 2040 {
lab=GND}
N 150 1980 150 2030 {
lab=Y1}
N 150 2030 150 2040 {
lab=Y1}
N 160 1990 200 1990 {
lab=word33}
N 200 1990 240 1990 {
lab=word33}
N 170 1980 170 2030 {
lab=GND}
N 170 2030 170 2040 {
lab=GND}
N 230 1980 230 2030 {
lab=Y2}
N 230 2030 230 2040 {
lab=Y2}
N 240 1990 280 1990 {
lab=word33}
N 280 1990 320 1990 {
lab=word33}
N 250 1980 250 2030 {
lab=GND}
N 250 2030 250 2040 {
lab=GND}
N 310 1980 310 2030 {
lab=Y3}
N 310 2030 310 2040 {
lab=Y3}
N 330 2040 360 2040 {
lab=GND}
N 360 2030 360 2040 {
lab=GND}
N 320 1990 360 1990 {
lab=word33}
N 360 1990 400 1990 {
lab=word33}
N 330 1980 330 2030 {
lab=GND}
N 330 2030 330 2040 {
lab=GND}
N 390 1980 390 2030 {
lab=Y4}
N 390 2030 390 2040 {
lab=Y4}
N 410 2040 440 2040 {
lab=GND}
N 440 2030 440 2040 {
lab=GND}
N 400 1990 440 1990 {
lab=word33}
N 440 1990 480 1990 {
lab=word33}
N 410 1980 410 2030 {
lab=GND}
N 410 2030 410 2040 {
lab=GND}
N 470 1980 470 2030 {
lab=Y5}
N 470 2030 470 2040 {
lab=Y5}
N 490 2040 520 2040 {
lab=GND}
N 520 2030 520 2040 {
lab=GND}
N 480 1990 520 1990 {
lab=word33}
N 520 1990 560 1990 {
lab=word33}
N 490 1980 490 2030 {
lab=GND}
N 490 2030 490 2040 {
lab=GND}
N 550 1980 550 2030 {
lab=Y6}
N 550 2030 550 2040 {
lab=Y6}
N 570 2040 600 2040 {
lab=GND}
N 600 2030 600 2040 {
lab=GND}
N 560 1990 600 1990 {
lab=word33}
N 600 1990 640 1990 {
lab=word33}
N 570 1980 570 2030 {
lab=GND}
N 570 2030 570 2040 {
lab=GND}
N 630 1980 630 2030 {
lab=Y7}
N 630 2030 630 2040 {
lab=Y7}
N 0 2050 40 2050 {
lab=word34}
N 40 2050 80 2050 {
lab=word34}
N 10 2040 10 2090 {
lab=GND}
N 10 2090 10 2100 {
lab=GND}
N 70 2040 70 2090 {
lab=Y0}
N 70 2090 70 2100 {
lab=Y0}
N 80 2050 120 2050 {
lab=word34}
N 120 2050 160 2050 {
lab=word34}
N 90 2040 90 2090 {
lab=GND}
N 90 2090 90 2100 {
lab=GND}
N 150 2040 150 2090 {
lab=Y1}
N 150 2090 150 2100 {
lab=Y1}
N 160 2050 200 2050 {
lab=word34}
N 200 2050 240 2050 {
lab=word34}
N 170 2040 170 2090 {
lab=GND}
N 170 2090 170 2100 {
lab=GND}
N 230 2040 230 2090 {
lab=Y2}
N 230 2090 230 2100 {
lab=Y2}
N 250 2100 280 2100 {
lab=GND}
N 280 2090 280 2100 {
lab=GND}
N 240 2050 280 2050 {
lab=word34}
N 280 2050 320 2050 {
lab=word34}
N 250 2040 250 2090 {
lab=GND}
N 250 2090 250 2100 {
lab=GND}
N 310 2040 310 2090 {
lab=Y3}
N 310 2090 310 2100 {
lab=Y3}
N 330 2100 360 2100 {
lab=GND}
N 360 2090 360 2100 {
lab=GND}
N 320 2050 360 2050 {
lab=word34}
N 360 2050 400 2050 {
lab=word34}
N 330 2040 330 2090 {
lab=GND}
N 330 2090 330 2100 {
lab=GND}
N 390 2040 390 2090 {
lab=Y4}
N 390 2090 390 2100 {
lab=Y4}
N 410 2100 440 2100 {
lab=GND}
N 440 2090 440 2100 {
lab=GND}
N 400 2050 440 2050 {
lab=word34}
N 440 2050 480 2050 {
lab=word34}
N 410 2040 410 2090 {
lab=GND}
N 410 2090 410 2100 {
lab=GND}
N 470 2040 470 2090 {
lab=Y5}
N 470 2090 470 2100 {
lab=Y5}
N 490 2100 520 2100 {
lab=GND}
N 520 2090 520 2100 {
lab=GND}
N 480 2050 520 2050 {
lab=word34}
N 520 2050 560 2050 {
lab=word34}
N 490 2040 490 2090 {
lab=GND}
N 490 2090 490 2100 {
lab=GND}
N 550 2040 550 2090 {
lab=Y6}
N 550 2090 550 2100 {
lab=Y6}
N 570 2100 600 2100 {
lab=GND}
N 600 2090 600 2100 {
lab=GND}
N 560 2050 600 2050 {
lab=word34}
N 600 2050 640 2050 {
lab=word34}
N 570 2040 570 2090 {
lab=GND}
N 570 2090 570 2100 {
lab=GND}
N 630 2040 630 2090 {
lab=Y7}
N 630 2090 630 2100 {
lab=Y7}
N 0 2110 40 2110 {
lab=word35}
N 40 2110 80 2110 {
lab=word35}
N 10 2100 10 2150 {
lab=GND}
N 10 2150 10 2160 {
lab=GND}
N 70 2100 70 2150 {
lab=Y0}
N 70 2150 70 2160 {
lab=Y0}
N 80 2110 120 2110 {
lab=word35}
N 120 2110 160 2110 {
lab=word35}
N 90 2100 90 2150 {
lab=GND}
N 90 2150 90 2160 {
lab=GND}
N 150 2100 150 2150 {
lab=Y1}
N 150 2150 150 2160 {
lab=Y1}
N 170 2160 200 2160 {
lab=GND}
N 200 2150 200 2160 {
lab=GND}
N 160 2110 200 2110 {
lab=word35}
N 200 2110 240 2110 {
lab=word35}
N 170 2100 170 2150 {
lab=GND}
N 170 2150 170 2160 {
lab=GND}
N 230 2100 230 2150 {
lab=Y2}
N 230 2150 230 2160 {
lab=Y2}
N 240 2110 280 2110 {
lab=word35}
N 280 2110 320 2110 {
lab=word35}
N 250 2100 250 2150 {
lab=GND}
N 250 2150 250 2160 {
lab=GND}
N 310 2100 310 2150 {
lab=Y3}
N 310 2150 310 2160 {
lab=Y3}
N 330 2160 360 2160 {
lab=GND}
N 360 2150 360 2160 {
lab=GND}
N 320 2110 360 2110 {
lab=word35}
N 360 2110 400 2110 {
lab=word35}
N 330 2100 330 2150 {
lab=GND}
N 330 2150 330 2160 {
lab=GND}
N 390 2100 390 2150 {
lab=Y4}
N 390 2150 390 2160 {
lab=Y4}
N 410 2160 440 2160 {
lab=GND}
N 440 2150 440 2160 {
lab=GND}
N 400 2110 440 2110 {
lab=word35}
N 440 2110 480 2110 {
lab=word35}
N 410 2100 410 2150 {
lab=GND}
N 410 2150 410 2160 {
lab=GND}
N 470 2100 470 2150 {
lab=Y5}
N 470 2150 470 2160 {
lab=Y5}
N 490 2160 520 2160 {
lab=GND}
N 520 2150 520 2160 {
lab=GND}
N 480 2110 520 2110 {
lab=word35}
N 520 2110 560 2110 {
lab=word35}
N 490 2100 490 2150 {
lab=GND}
N 490 2150 490 2160 {
lab=GND}
N 550 2100 550 2150 {
lab=Y6}
N 550 2150 550 2160 {
lab=Y6}
N 570 2160 600 2160 {
lab=GND}
N 600 2150 600 2160 {
lab=GND}
N 560 2110 600 2110 {
lab=word35}
N 600 2110 640 2110 {
lab=word35}
N 570 2100 570 2150 {
lab=GND}
N 570 2150 570 2160 {
lab=GND}
N 630 2100 630 2150 {
lab=Y7}
N 630 2150 630 2160 {
lab=Y7}
N 0 2170 40 2170 {
lab=word36}
N 40 2170 80 2170 {
lab=word36}
N 10 2160 10 2210 {
lab=GND}
N 10 2210 10 2220 {
lab=GND}
N 70 2160 70 2210 {
lab=Y0}
N 70 2210 70 2220 {
lab=Y0}
N 80 2170 120 2170 {
lab=word36}
N 120 2170 160 2170 {
lab=word36}
N 90 2160 90 2210 {
lab=GND}
N 90 2210 90 2220 {
lab=GND}
N 150 2160 150 2210 {
lab=Y1}
N 150 2210 150 2220 {
lab=Y1}
N 170 2220 200 2220 {
lab=GND}
N 200 2210 200 2220 {
lab=GND}
N 160 2170 200 2170 {
lab=word36}
N 200 2170 240 2170 {
lab=word36}
N 170 2160 170 2210 {
lab=GND}
N 170 2210 170 2220 {
lab=GND}
N 230 2160 230 2210 {
lab=Y2}
N 230 2210 230 2220 {
lab=Y2}
N 250 2220 280 2220 {
lab=GND}
N 280 2210 280 2220 {
lab=GND}
N 240 2170 280 2170 {
lab=word36}
N 280 2170 320 2170 {
lab=word36}
N 250 2160 250 2210 {
lab=GND}
N 250 2210 250 2220 {
lab=GND}
N 310 2160 310 2210 {
lab=Y3}
N 310 2210 310 2220 {
lab=Y3}
N 330 2220 360 2220 {
lab=GND}
N 360 2210 360 2220 {
lab=GND}
N 320 2170 360 2170 {
lab=word36}
N 360 2170 400 2170 {
lab=word36}
N 330 2160 330 2210 {
lab=GND}
N 330 2210 330 2220 {
lab=GND}
N 390 2160 390 2210 {
lab=Y4}
N 390 2210 390 2220 {
lab=Y4}
N 410 2220 440 2220 {
lab=GND}
N 440 2210 440 2220 {
lab=GND}
N 400 2170 440 2170 {
lab=word36}
N 440 2170 480 2170 {
lab=word36}
N 410 2160 410 2210 {
lab=GND}
N 410 2210 410 2220 {
lab=GND}
N 470 2160 470 2210 {
lab=Y5}
N 470 2210 470 2220 {
lab=Y5}
N 490 2220 520 2220 {
lab=GND}
N 520 2210 520 2220 {
lab=GND}
N 480 2170 520 2170 {
lab=word36}
N 520 2170 560 2170 {
lab=word36}
N 490 2160 490 2210 {
lab=GND}
N 490 2210 490 2220 {
lab=GND}
N 550 2160 550 2210 {
lab=Y6}
N 550 2210 550 2220 {
lab=Y6}
N 570 2220 600 2220 {
lab=GND}
N 600 2210 600 2220 {
lab=GND}
N 560 2170 600 2170 {
lab=word36}
N 600 2170 640 2170 {
lab=word36}
N 570 2160 570 2210 {
lab=GND}
N 570 2210 570 2220 {
lab=GND}
N 630 2160 630 2210 {
lab=Y7}
N 630 2210 630 2220 {
lab=Y7}
N 0 2230 40 2230 {
lab=word37}
N 40 2230 80 2230 {
lab=word37}
N 10 2220 10 2270 {
lab=GND}
N 10 2270 10 2280 {
lab=GND}
N 70 2220 70 2270 {
lab=Y0}
N 70 2270 70 2280 {
lab=Y0}
N 90 2280 120 2280 {
lab=GND}
N 120 2270 120 2280 {
lab=GND}
N 80 2230 120 2230 {
lab=word37}
N 120 2230 160 2230 {
lab=word37}
N 90 2220 90 2270 {
lab=GND}
N 90 2270 90 2280 {
lab=GND}
N 150 2220 150 2270 {
lab=Y1}
N 150 2270 150 2280 {
lab=Y1}
N 160 2230 200 2230 {
lab=word37}
N 200 2230 240 2230 {
lab=word37}
N 170 2220 170 2270 {
lab=GND}
N 170 2270 170 2280 {
lab=GND}
N 230 2220 230 2270 {
lab=Y2}
N 230 2270 230 2280 {
lab=Y2}
N 240 2230 280 2230 {
lab=word37}
N 280 2230 320 2230 {
lab=word37}
N 250 2220 250 2270 {
lab=GND}
N 250 2270 250 2280 {
lab=GND}
N 310 2220 310 2270 {
lab=Y3}
N 310 2270 310 2280 {
lab=Y3}
N 330 2280 360 2280 {
lab=GND}
N 360 2270 360 2280 {
lab=GND}
N 320 2230 360 2230 {
lab=word37}
N 360 2230 400 2230 {
lab=word37}
N 330 2220 330 2270 {
lab=GND}
N 330 2270 330 2280 {
lab=GND}
N 390 2220 390 2270 {
lab=Y4}
N 390 2270 390 2280 {
lab=Y4}
N 410 2280 440 2280 {
lab=GND}
N 440 2270 440 2280 {
lab=GND}
N 400 2230 440 2230 {
lab=word37}
N 440 2230 480 2230 {
lab=word37}
N 410 2220 410 2270 {
lab=GND}
N 410 2270 410 2280 {
lab=GND}
N 470 2220 470 2270 {
lab=Y5}
N 470 2270 470 2280 {
lab=Y5}
N 490 2280 520 2280 {
lab=GND}
N 520 2270 520 2280 {
lab=GND}
N 480 2230 520 2230 {
lab=word37}
N 520 2230 560 2230 {
lab=word37}
N 490 2220 490 2270 {
lab=GND}
N 490 2270 490 2280 {
lab=GND}
N 550 2220 550 2270 {
lab=Y6}
N 550 2270 550 2280 {
lab=Y6}
N 570 2280 600 2280 {
lab=GND}
N 600 2270 600 2280 {
lab=GND}
N 560 2230 600 2230 {
lab=word37}
N 600 2230 640 2230 {
lab=word37}
N 570 2220 570 2270 {
lab=GND}
N 570 2270 570 2280 {
lab=GND}
N 630 2220 630 2270 {
lab=Y7}
N 630 2270 630 2280 {
lab=Y7}
N 0 2290 40 2290 {
lab=word38}
N 40 2290 80 2290 {
lab=word38}
N 10 2280 10 2330 {
lab=GND}
N 10 2330 10 2340 {
lab=GND}
N 70 2280 70 2330 {
lab=Y0}
N 70 2330 70 2340 {
lab=Y0}
N 90 2340 120 2340 {
lab=GND}
N 120 2330 120 2340 {
lab=GND}
N 80 2290 120 2290 {
lab=word38}
N 120 2290 160 2290 {
lab=word38}
N 90 2280 90 2330 {
lab=GND}
N 90 2330 90 2340 {
lab=GND}
N 150 2280 150 2330 {
lab=Y1}
N 150 2330 150 2340 {
lab=Y1}
N 160 2290 200 2290 {
lab=word38}
N 200 2290 240 2290 {
lab=word38}
N 170 2280 170 2330 {
lab=GND}
N 170 2330 170 2340 {
lab=GND}
N 230 2280 230 2330 {
lab=Y2}
N 230 2330 230 2340 {
lab=Y2}
N 250 2340 280 2340 {
lab=GND}
N 280 2330 280 2340 {
lab=GND}
N 240 2290 280 2290 {
lab=word38}
N 280 2290 320 2290 {
lab=word38}
N 250 2280 250 2330 {
lab=GND}
N 250 2330 250 2340 {
lab=GND}
N 310 2280 310 2330 {
lab=Y3}
N 310 2330 310 2340 {
lab=Y3}
N 330 2340 360 2340 {
lab=GND}
N 360 2330 360 2340 {
lab=GND}
N 320 2290 360 2290 {
lab=word38}
N 360 2290 400 2290 {
lab=word38}
N 330 2280 330 2330 {
lab=GND}
N 330 2330 330 2340 {
lab=GND}
N 390 2280 390 2330 {
lab=Y4}
N 390 2330 390 2340 {
lab=Y4}
N 410 2340 440 2340 {
lab=GND}
N 440 2330 440 2340 {
lab=GND}
N 400 2290 440 2290 {
lab=word38}
N 440 2290 480 2290 {
lab=word38}
N 410 2280 410 2330 {
lab=GND}
N 410 2330 410 2340 {
lab=GND}
N 470 2280 470 2330 {
lab=Y5}
N 470 2330 470 2340 {
lab=Y5}
N 490 2340 520 2340 {
lab=GND}
N 520 2330 520 2340 {
lab=GND}
N 480 2290 520 2290 {
lab=word38}
N 520 2290 560 2290 {
lab=word38}
N 490 2280 490 2330 {
lab=GND}
N 490 2330 490 2340 {
lab=GND}
N 550 2280 550 2330 {
lab=Y6}
N 550 2330 550 2340 {
lab=Y6}
N 570 2340 600 2340 {
lab=GND}
N 600 2330 600 2340 {
lab=GND}
N 560 2290 600 2290 {
lab=word38}
N 600 2290 640 2290 {
lab=word38}
N 570 2280 570 2330 {
lab=GND}
N 570 2330 570 2340 {
lab=GND}
N 630 2280 630 2330 {
lab=Y7}
N 630 2330 630 2340 {
lab=Y7}
N 0 2350 40 2350 {
lab=word39}
N 40 2350 80 2350 {
lab=word39}
N 10 2340 10 2390 {
lab=GND}
N 10 2390 10 2400 {
lab=GND}
N 70 2340 70 2390 {
lab=Y0}
N 70 2390 70 2400 {
lab=Y0}
N 90 2400 120 2400 {
lab=GND}
N 120 2390 120 2400 {
lab=GND}
N 80 2350 120 2350 {
lab=word39}
N 120 2350 160 2350 {
lab=word39}
N 90 2340 90 2390 {
lab=GND}
N 90 2390 90 2400 {
lab=GND}
N 150 2340 150 2390 {
lab=Y1}
N 150 2390 150 2400 {
lab=Y1}
N 170 2400 200 2400 {
lab=GND}
N 200 2390 200 2400 {
lab=GND}
N 160 2350 200 2350 {
lab=word39}
N 200 2350 240 2350 {
lab=word39}
N 170 2340 170 2390 {
lab=GND}
N 170 2390 170 2400 {
lab=GND}
N 230 2340 230 2390 {
lab=Y2}
N 230 2390 230 2400 {
lab=Y2}
N 240 2350 280 2350 {
lab=word39}
N 280 2350 320 2350 {
lab=word39}
N 250 2340 250 2390 {
lab=GND}
N 250 2390 250 2400 {
lab=GND}
N 310 2340 310 2390 {
lab=Y3}
N 310 2390 310 2400 {
lab=Y3}
N 330 2400 360 2400 {
lab=GND}
N 360 2390 360 2400 {
lab=GND}
N 320 2350 360 2350 {
lab=word39}
N 360 2350 400 2350 {
lab=word39}
N 330 2340 330 2390 {
lab=GND}
N 330 2390 330 2400 {
lab=GND}
N 390 2340 390 2390 {
lab=Y4}
N 390 2390 390 2400 {
lab=Y4}
N 410 2400 440 2400 {
lab=GND}
N 440 2390 440 2400 {
lab=GND}
N 400 2350 440 2350 {
lab=word39}
N 440 2350 480 2350 {
lab=word39}
N 410 2340 410 2390 {
lab=GND}
N 410 2390 410 2400 {
lab=GND}
N 470 2340 470 2390 {
lab=Y5}
N 470 2390 470 2400 {
lab=Y5}
N 490 2400 520 2400 {
lab=GND}
N 520 2390 520 2400 {
lab=GND}
N 480 2350 520 2350 {
lab=word39}
N 520 2350 560 2350 {
lab=word39}
N 490 2340 490 2390 {
lab=GND}
N 490 2390 490 2400 {
lab=GND}
N 550 2340 550 2390 {
lab=Y6}
N 550 2390 550 2400 {
lab=Y6}
N 570 2400 600 2400 {
lab=GND}
N 600 2390 600 2400 {
lab=GND}
N 560 2350 600 2350 {
lab=word39}
N 600 2350 640 2350 {
lab=word39}
N 570 2340 570 2390 {
lab=GND}
N 570 2390 570 2400 {
lab=GND}
N 630 2340 630 2390 {
lab=Y7}
N 630 2390 630 2400 {
lab=Y7}
N 0 2410 40 2410 {
lab=word40}
N 40 2410 80 2410 {
lab=word40}
N 10 2400 10 2450 {
lab=GND}
N 10 2450 10 2460 {
lab=GND}
N 70 2400 70 2450 {
lab=Y0}
N 70 2450 70 2460 {
lab=Y0}
N 90 2460 120 2460 {
lab=GND}
N 120 2450 120 2460 {
lab=GND}
N 80 2410 120 2410 {
lab=word40}
N 120 2410 160 2410 {
lab=word40}
N 90 2400 90 2450 {
lab=GND}
N 90 2450 90 2460 {
lab=GND}
N 150 2400 150 2450 {
lab=Y1}
N 150 2450 150 2460 {
lab=Y1}
N 170 2460 200 2460 {
lab=GND}
N 200 2450 200 2460 {
lab=GND}
N 160 2410 200 2410 {
lab=word40}
N 200 2410 240 2410 {
lab=word40}
N 170 2400 170 2450 {
lab=GND}
N 170 2450 170 2460 {
lab=GND}
N 230 2400 230 2450 {
lab=Y2}
N 230 2450 230 2460 {
lab=Y2}
N 250 2460 280 2460 {
lab=GND}
N 280 2450 280 2460 {
lab=GND}
N 240 2410 280 2410 {
lab=word40}
N 280 2410 320 2410 {
lab=word40}
N 250 2400 250 2450 {
lab=GND}
N 250 2450 250 2460 {
lab=GND}
N 310 2400 310 2450 {
lab=Y3}
N 310 2450 310 2460 {
lab=Y3}
N 330 2460 360 2460 {
lab=GND}
N 360 2450 360 2460 {
lab=GND}
N 320 2410 360 2410 {
lab=word40}
N 360 2410 400 2410 {
lab=word40}
N 330 2400 330 2450 {
lab=GND}
N 330 2450 330 2460 {
lab=GND}
N 390 2400 390 2450 {
lab=Y4}
N 390 2450 390 2460 {
lab=Y4}
N 410 2460 440 2460 {
lab=GND}
N 440 2450 440 2460 {
lab=GND}
N 400 2410 440 2410 {
lab=word40}
N 440 2410 480 2410 {
lab=word40}
N 410 2400 410 2450 {
lab=GND}
N 410 2450 410 2460 {
lab=GND}
N 470 2400 470 2450 {
lab=Y5}
N 470 2450 470 2460 {
lab=Y5}
N 490 2460 520 2460 {
lab=GND}
N 520 2450 520 2460 {
lab=GND}
N 480 2410 520 2410 {
lab=word40}
N 520 2410 560 2410 {
lab=word40}
N 490 2400 490 2450 {
lab=GND}
N 490 2450 490 2460 {
lab=GND}
N 550 2400 550 2450 {
lab=Y6}
N 550 2450 550 2460 {
lab=Y6}
N 570 2460 600 2460 {
lab=GND}
N 600 2450 600 2460 {
lab=GND}
N 560 2410 600 2410 {
lab=word40}
N 600 2410 640 2410 {
lab=word40}
N 570 2400 570 2450 {
lab=GND}
N 570 2450 570 2460 {
lab=GND}
N 630 2400 630 2450 {
lab=Y7}
N 630 2450 630 2460 {
lab=Y7}
N 10 2520 40 2520 {
lab=GND}
N 40 2510 40 2520 {
lab=GND}
N 0 2470 40 2470 {
lab=word41}
N 40 2470 80 2470 {
lab=word41}
N 10 2460 10 2510 {
lab=GND}
N 10 2510 10 2520 {
lab=GND}
N 70 2460 70 2510 {
lab=Y0}
N 70 2510 70 2520 {
lab=Y0}
N 80 2470 120 2470 {
lab=word41}
N 120 2470 160 2470 {
lab=word41}
N 90 2460 90 2510 {
lab=GND}
N 90 2510 90 2520 {
lab=GND}
N 150 2460 150 2510 {
lab=Y1}
N 150 2510 150 2520 {
lab=Y1}
N 160 2470 200 2470 {
lab=word41}
N 200 2470 240 2470 {
lab=word41}
N 170 2460 170 2510 {
lab=GND}
N 170 2510 170 2520 {
lab=GND}
N 230 2460 230 2510 {
lab=Y2}
N 230 2510 230 2520 {
lab=Y2}
N 240 2470 280 2470 {
lab=word41}
N 280 2470 320 2470 {
lab=word41}
N 250 2460 250 2510 {
lab=GND}
N 250 2510 250 2520 {
lab=GND}
N 310 2460 310 2510 {
lab=Y3}
N 310 2510 310 2520 {
lab=Y3}
N 330 2520 360 2520 {
lab=GND}
N 360 2510 360 2520 {
lab=GND}
N 320 2470 360 2470 {
lab=word41}
N 360 2470 400 2470 {
lab=word41}
N 330 2460 330 2510 {
lab=GND}
N 330 2510 330 2520 {
lab=GND}
N 390 2460 390 2510 {
lab=Y4}
N 390 2510 390 2520 {
lab=Y4}
N 410 2520 440 2520 {
lab=GND}
N 440 2510 440 2520 {
lab=GND}
N 400 2470 440 2470 {
lab=word41}
N 440 2470 480 2470 {
lab=word41}
N 410 2460 410 2510 {
lab=GND}
N 410 2510 410 2520 {
lab=GND}
N 470 2460 470 2510 {
lab=Y5}
N 470 2510 470 2520 {
lab=Y5}
N 490 2520 520 2520 {
lab=GND}
N 520 2510 520 2520 {
lab=GND}
N 480 2470 520 2470 {
lab=word41}
N 520 2470 560 2470 {
lab=word41}
N 490 2460 490 2510 {
lab=GND}
N 490 2510 490 2520 {
lab=GND}
N 550 2460 550 2510 {
lab=Y6}
N 550 2510 550 2520 {
lab=Y6}
N 570 2520 600 2520 {
lab=GND}
N 600 2510 600 2520 {
lab=GND}
N 560 2470 600 2470 {
lab=word41}
N 600 2470 640 2470 {
lab=word41}
N 570 2460 570 2510 {
lab=GND}
N 570 2510 570 2520 {
lab=GND}
N 630 2460 630 2510 {
lab=Y7}
N 630 2510 630 2520 {
lab=Y7}
N 10 2580 40 2580 {
lab=GND}
N 40 2570 40 2580 {
lab=GND}
N 0 2530 40 2530 {
lab=word42}
N 40 2530 80 2530 {
lab=word42}
N 10 2520 10 2570 {
lab=GND}
N 10 2570 10 2580 {
lab=GND}
N 70 2520 70 2570 {
lab=Y0}
N 70 2570 70 2580 {
lab=Y0}
N 80 2530 120 2530 {
lab=word42}
N 120 2530 160 2530 {
lab=word42}
N 90 2520 90 2570 {
lab=GND}
N 90 2570 90 2580 {
lab=GND}
N 150 2520 150 2570 {
lab=Y1}
N 150 2570 150 2580 {
lab=Y1}
N 160 2530 200 2530 {
lab=word42}
N 200 2530 240 2530 {
lab=word42}
N 170 2520 170 2570 {
lab=GND}
N 170 2570 170 2580 {
lab=GND}
N 230 2520 230 2570 {
lab=Y2}
N 230 2570 230 2580 {
lab=Y2}
N 250 2580 280 2580 {
lab=GND}
N 280 2570 280 2580 {
lab=GND}
N 240 2530 280 2530 {
lab=word42}
N 280 2530 320 2530 {
lab=word42}
N 250 2520 250 2570 {
lab=GND}
N 250 2570 250 2580 {
lab=GND}
N 310 2520 310 2570 {
lab=Y3}
N 310 2570 310 2580 {
lab=Y3}
N 330 2580 360 2580 {
lab=GND}
N 360 2570 360 2580 {
lab=GND}
N 320 2530 360 2530 {
lab=word42}
N 360 2530 400 2530 {
lab=word42}
N 330 2520 330 2570 {
lab=GND}
N 330 2570 330 2580 {
lab=GND}
N 390 2520 390 2570 {
lab=Y4}
N 390 2570 390 2580 {
lab=Y4}
N 410 2580 440 2580 {
lab=GND}
N 440 2570 440 2580 {
lab=GND}
N 400 2530 440 2530 {
lab=word42}
N 440 2530 480 2530 {
lab=word42}
N 410 2520 410 2570 {
lab=GND}
N 410 2570 410 2580 {
lab=GND}
N 470 2520 470 2570 {
lab=Y5}
N 470 2570 470 2580 {
lab=Y5}
N 490 2580 520 2580 {
lab=GND}
N 520 2570 520 2580 {
lab=GND}
N 480 2530 520 2530 {
lab=word42}
N 520 2530 560 2530 {
lab=word42}
N 490 2520 490 2570 {
lab=GND}
N 490 2570 490 2580 {
lab=GND}
N 550 2520 550 2570 {
lab=Y6}
N 550 2570 550 2580 {
lab=Y6}
N 570 2580 600 2580 {
lab=GND}
N 600 2570 600 2580 {
lab=GND}
N 560 2530 600 2530 {
lab=word42}
N 600 2530 640 2530 {
lab=word42}
N 570 2520 570 2570 {
lab=GND}
N 570 2570 570 2580 {
lab=GND}
N 630 2520 630 2570 {
lab=Y7}
N 630 2570 630 2580 {
lab=Y7}
N 10 2640 40 2640 {
lab=GND}
N 40 2630 40 2640 {
lab=GND}
N 0 2590 40 2590 {
lab=word43}
N 40 2590 80 2590 {
lab=word43}
N 10 2580 10 2630 {
lab=GND}
N 10 2630 10 2640 {
lab=GND}
N 70 2580 70 2630 {
lab=Y0}
N 70 2630 70 2640 {
lab=Y0}
N 80 2590 120 2590 {
lab=word43}
N 120 2590 160 2590 {
lab=word43}
N 90 2580 90 2630 {
lab=GND}
N 90 2630 90 2640 {
lab=GND}
N 150 2580 150 2630 {
lab=Y1}
N 150 2630 150 2640 {
lab=Y1}
N 170 2640 200 2640 {
lab=GND}
N 200 2630 200 2640 {
lab=GND}
N 160 2590 200 2590 {
lab=word43}
N 200 2590 240 2590 {
lab=word43}
N 170 2580 170 2630 {
lab=GND}
N 170 2630 170 2640 {
lab=GND}
N 230 2580 230 2630 {
lab=Y2}
N 230 2630 230 2640 {
lab=Y2}
N 240 2590 280 2590 {
lab=word43}
N 280 2590 320 2590 {
lab=word43}
N 250 2580 250 2630 {
lab=GND}
N 250 2630 250 2640 {
lab=GND}
N 310 2580 310 2630 {
lab=Y3}
N 310 2630 310 2640 {
lab=Y3}
N 330 2640 360 2640 {
lab=GND}
N 360 2630 360 2640 {
lab=GND}
N 320 2590 360 2590 {
lab=word43}
N 360 2590 400 2590 {
lab=word43}
N 330 2580 330 2630 {
lab=GND}
N 330 2630 330 2640 {
lab=GND}
N 390 2580 390 2630 {
lab=Y4}
N 390 2630 390 2640 {
lab=Y4}
N 410 2640 440 2640 {
lab=GND}
N 440 2630 440 2640 {
lab=GND}
N 400 2590 440 2590 {
lab=word43}
N 440 2590 480 2590 {
lab=word43}
N 410 2580 410 2630 {
lab=GND}
N 410 2630 410 2640 {
lab=GND}
N 470 2580 470 2630 {
lab=Y5}
N 470 2630 470 2640 {
lab=Y5}
N 490 2640 520 2640 {
lab=GND}
N 520 2630 520 2640 {
lab=GND}
N 480 2590 520 2590 {
lab=word43}
N 520 2590 560 2590 {
lab=word43}
N 490 2580 490 2630 {
lab=GND}
N 490 2630 490 2640 {
lab=GND}
N 550 2580 550 2630 {
lab=Y6}
N 550 2630 550 2640 {
lab=Y6}
N 570 2640 600 2640 {
lab=GND}
N 600 2630 600 2640 {
lab=GND}
N 560 2590 600 2590 {
lab=word43}
N 600 2590 640 2590 {
lab=word43}
N 570 2580 570 2630 {
lab=GND}
N 570 2630 570 2640 {
lab=GND}
N 630 2580 630 2630 {
lab=Y7}
N 630 2630 630 2640 {
lab=Y7}
N 10 2700 40 2700 {
lab=GND}
N 40 2690 40 2700 {
lab=GND}
N 0 2650 40 2650 {
lab=word44}
N 40 2650 80 2650 {
lab=word44}
N 10 2640 10 2690 {
lab=GND}
N 10 2690 10 2700 {
lab=GND}
N 70 2640 70 2690 {
lab=Y0}
N 70 2690 70 2700 {
lab=Y0}
N 80 2650 120 2650 {
lab=word44}
N 120 2650 160 2650 {
lab=word44}
N 90 2640 90 2690 {
lab=GND}
N 90 2690 90 2700 {
lab=GND}
N 150 2640 150 2690 {
lab=Y1}
N 150 2690 150 2700 {
lab=Y1}
N 170 2700 200 2700 {
lab=GND}
N 200 2690 200 2700 {
lab=GND}
N 160 2650 200 2650 {
lab=word44}
N 200 2650 240 2650 {
lab=word44}
N 170 2640 170 2690 {
lab=GND}
N 170 2690 170 2700 {
lab=GND}
N 230 2640 230 2690 {
lab=Y2}
N 230 2690 230 2700 {
lab=Y2}
N 250 2700 280 2700 {
lab=GND}
N 280 2690 280 2700 {
lab=GND}
N 240 2650 280 2650 {
lab=word44}
N 280 2650 320 2650 {
lab=word44}
N 250 2640 250 2690 {
lab=GND}
N 250 2690 250 2700 {
lab=GND}
N 310 2640 310 2690 {
lab=Y3}
N 310 2690 310 2700 {
lab=Y3}
N 330 2700 360 2700 {
lab=GND}
N 360 2690 360 2700 {
lab=GND}
N 320 2650 360 2650 {
lab=word44}
N 360 2650 400 2650 {
lab=word44}
N 330 2640 330 2690 {
lab=GND}
N 330 2690 330 2700 {
lab=GND}
N 390 2640 390 2690 {
lab=Y4}
N 390 2690 390 2700 {
lab=Y4}
N 410 2700 440 2700 {
lab=GND}
N 440 2690 440 2700 {
lab=GND}
N 400 2650 440 2650 {
lab=word44}
N 440 2650 480 2650 {
lab=word44}
N 410 2640 410 2690 {
lab=GND}
N 410 2690 410 2700 {
lab=GND}
N 470 2640 470 2690 {
lab=Y5}
N 470 2690 470 2700 {
lab=Y5}
N 490 2700 520 2700 {
lab=GND}
N 520 2690 520 2700 {
lab=GND}
N 480 2650 520 2650 {
lab=word44}
N 520 2650 560 2650 {
lab=word44}
N 490 2640 490 2690 {
lab=GND}
N 490 2690 490 2700 {
lab=GND}
N 550 2640 550 2690 {
lab=Y6}
N 550 2690 550 2700 {
lab=Y6}
N 570 2700 600 2700 {
lab=GND}
N 600 2690 600 2700 {
lab=GND}
N 560 2650 600 2650 {
lab=word44}
N 600 2650 640 2650 {
lab=word44}
N 570 2640 570 2690 {
lab=GND}
N 570 2690 570 2700 {
lab=GND}
N 630 2640 630 2690 {
lab=Y7}
N 630 2690 630 2700 {
lab=Y7}
N 10 2760 40 2760 {
lab=GND}
N 40 2750 40 2760 {
lab=GND}
N 0 2710 40 2710 {
lab=word45}
N 40 2710 80 2710 {
lab=word45}
N 10 2700 10 2750 {
lab=GND}
N 10 2750 10 2760 {
lab=GND}
N 70 2700 70 2750 {
lab=Y0}
N 70 2750 70 2760 {
lab=Y0}
N 90 2760 120 2760 {
lab=GND}
N 120 2750 120 2760 {
lab=GND}
N 80 2710 120 2710 {
lab=word45}
N 120 2710 160 2710 {
lab=word45}
N 90 2700 90 2750 {
lab=GND}
N 90 2750 90 2760 {
lab=GND}
N 150 2700 150 2750 {
lab=Y1}
N 150 2750 150 2760 {
lab=Y1}
N 160 2710 200 2710 {
lab=word45}
N 200 2710 240 2710 {
lab=word45}
N 170 2700 170 2750 {
lab=GND}
N 170 2750 170 2760 {
lab=GND}
N 230 2700 230 2750 {
lab=Y2}
N 230 2750 230 2760 {
lab=Y2}
N 240 2710 280 2710 {
lab=word45}
N 280 2710 320 2710 {
lab=word45}
N 250 2700 250 2750 {
lab=GND}
N 250 2750 250 2760 {
lab=GND}
N 310 2700 310 2750 {
lab=Y3}
N 310 2750 310 2760 {
lab=Y3}
N 330 2760 360 2760 {
lab=GND}
N 360 2750 360 2760 {
lab=GND}
N 320 2710 360 2710 {
lab=word45}
N 360 2710 400 2710 {
lab=word45}
N 330 2700 330 2750 {
lab=GND}
N 330 2750 330 2760 {
lab=GND}
N 390 2700 390 2750 {
lab=Y4}
N 390 2750 390 2760 {
lab=Y4}
N 410 2760 440 2760 {
lab=GND}
N 440 2750 440 2760 {
lab=GND}
N 400 2710 440 2710 {
lab=word45}
N 440 2710 480 2710 {
lab=word45}
N 410 2700 410 2750 {
lab=GND}
N 410 2750 410 2760 {
lab=GND}
N 470 2700 470 2750 {
lab=Y5}
N 470 2750 470 2760 {
lab=Y5}
N 490 2760 520 2760 {
lab=GND}
N 520 2750 520 2760 {
lab=GND}
N 480 2710 520 2710 {
lab=word45}
N 520 2710 560 2710 {
lab=word45}
N 490 2700 490 2750 {
lab=GND}
N 490 2750 490 2760 {
lab=GND}
N 550 2700 550 2750 {
lab=Y6}
N 550 2750 550 2760 {
lab=Y6}
N 570 2760 600 2760 {
lab=GND}
N 600 2750 600 2760 {
lab=GND}
N 560 2710 600 2710 {
lab=word45}
N 600 2710 640 2710 {
lab=word45}
N 570 2700 570 2750 {
lab=GND}
N 570 2750 570 2760 {
lab=GND}
N 630 2700 630 2750 {
lab=Y7}
N 630 2750 630 2760 {
lab=Y7}
N 10 2820 40 2820 {
lab=GND}
N 40 2810 40 2820 {
lab=GND}
N 0 2770 40 2770 {
lab=word46}
N 40 2770 80 2770 {
lab=word46}
N 10 2760 10 2810 {
lab=GND}
N 10 2810 10 2820 {
lab=GND}
N 70 2760 70 2810 {
lab=Y0}
N 70 2810 70 2820 {
lab=Y0}
N 90 2820 120 2820 {
lab=GND}
N 120 2810 120 2820 {
lab=GND}
N 80 2770 120 2770 {
lab=word46}
N 120 2770 160 2770 {
lab=word46}
N 90 2760 90 2810 {
lab=GND}
N 90 2810 90 2820 {
lab=GND}
N 150 2760 150 2810 {
lab=Y1}
N 150 2810 150 2820 {
lab=Y1}
N 160 2770 200 2770 {
lab=word46}
N 200 2770 240 2770 {
lab=word46}
N 170 2760 170 2810 {
lab=GND}
N 170 2810 170 2820 {
lab=GND}
N 230 2760 230 2810 {
lab=Y2}
N 230 2810 230 2820 {
lab=Y2}
N 250 2820 280 2820 {
lab=GND}
N 280 2810 280 2820 {
lab=GND}
N 240 2770 280 2770 {
lab=word46}
N 280 2770 320 2770 {
lab=word46}
N 250 2760 250 2810 {
lab=GND}
N 250 2810 250 2820 {
lab=GND}
N 310 2760 310 2810 {
lab=Y3}
N 310 2810 310 2820 {
lab=Y3}
N 330 2820 360 2820 {
lab=GND}
N 360 2810 360 2820 {
lab=GND}
N 320 2770 360 2770 {
lab=word46}
N 360 2770 400 2770 {
lab=word46}
N 330 2760 330 2810 {
lab=GND}
N 330 2810 330 2820 {
lab=GND}
N 390 2760 390 2810 {
lab=Y4}
N 390 2810 390 2820 {
lab=Y4}
N 410 2820 440 2820 {
lab=GND}
N 440 2810 440 2820 {
lab=GND}
N 400 2770 440 2770 {
lab=word46}
N 440 2770 480 2770 {
lab=word46}
N 410 2760 410 2810 {
lab=GND}
N 410 2810 410 2820 {
lab=GND}
N 470 2760 470 2810 {
lab=Y5}
N 470 2810 470 2820 {
lab=Y5}
N 490 2820 520 2820 {
lab=GND}
N 520 2810 520 2820 {
lab=GND}
N 480 2770 520 2770 {
lab=word46}
N 520 2770 560 2770 {
lab=word46}
N 490 2760 490 2810 {
lab=GND}
N 490 2810 490 2820 {
lab=GND}
N 550 2760 550 2810 {
lab=Y6}
N 550 2810 550 2820 {
lab=Y6}
N 570 2820 600 2820 {
lab=GND}
N 600 2810 600 2820 {
lab=GND}
N 560 2770 600 2770 {
lab=word46}
N 600 2770 640 2770 {
lab=word46}
N 570 2760 570 2810 {
lab=GND}
N 570 2810 570 2820 {
lab=GND}
N 630 2760 630 2810 {
lab=Y7}
N 630 2810 630 2820 {
lab=Y7}
N 10 2880 40 2880 {
lab=GND}
N 40 2870 40 2880 {
lab=GND}
N 0 2830 40 2830 {
lab=word47}
N 40 2830 80 2830 {
lab=word47}
N 10 2820 10 2870 {
lab=GND}
N 10 2870 10 2880 {
lab=GND}
N 70 2820 70 2870 {
lab=Y0}
N 70 2870 70 2880 {
lab=Y0}
N 90 2880 120 2880 {
lab=GND}
N 120 2870 120 2880 {
lab=GND}
N 80 2830 120 2830 {
lab=word47}
N 120 2830 160 2830 {
lab=word47}
N 90 2820 90 2870 {
lab=GND}
N 90 2870 90 2880 {
lab=GND}
N 150 2820 150 2870 {
lab=Y1}
N 150 2870 150 2880 {
lab=Y1}
N 170 2880 200 2880 {
lab=GND}
N 200 2870 200 2880 {
lab=GND}
N 160 2830 200 2830 {
lab=word47}
N 200 2830 240 2830 {
lab=word47}
N 170 2820 170 2870 {
lab=GND}
N 170 2870 170 2880 {
lab=GND}
N 230 2820 230 2870 {
lab=Y2}
N 230 2870 230 2880 {
lab=Y2}
N 240 2830 280 2830 {
lab=word47}
N 280 2830 320 2830 {
lab=word47}
N 250 2820 250 2870 {
lab=GND}
N 250 2870 250 2880 {
lab=GND}
N 310 2820 310 2870 {
lab=Y3}
N 310 2870 310 2880 {
lab=Y3}
N 330 2880 360 2880 {
lab=GND}
N 360 2870 360 2880 {
lab=GND}
N 320 2830 360 2830 {
lab=word47}
N 360 2830 400 2830 {
lab=word47}
N 330 2820 330 2870 {
lab=GND}
N 330 2870 330 2880 {
lab=GND}
N 390 2820 390 2870 {
lab=Y4}
N 390 2870 390 2880 {
lab=Y4}
N 410 2880 440 2880 {
lab=GND}
N 440 2870 440 2880 {
lab=GND}
N 400 2830 440 2830 {
lab=word47}
N 440 2830 480 2830 {
lab=word47}
N 410 2820 410 2870 {
lab=GND}
N 410 2870 410 2880 {
lab=GND}
N 470 2820 470 2870 {
lab=Y5}
N 470 2870 470 2880 {
lab=Y5}
N 490 2880 520 2880 {
lab=GND}
N 520 2870 520 2880 {
lab=GND}
N 480 2830 520 2830 {
lab=word47}
N 520 2830 560 2830 {
lab=word47}
N 490 2820 490 2870 {
lab=GND}
N 490 2870 490 2880 {
lab=GND}
N 550 2820 550 2870 {
lab=Y6}
N 550 2870 550 2880 {
lab=Y6}
N 570 2880 600 2880 {
lab=GND}
N 600 2870 600 2880 {
lab=GND}
N 560 2830 600 2830 {
lab=word47}
N 600 2830 640 2830 {
lab=word47}
N 570 2820 570 2870 {
lab=GND}
N 570 2870 570 2880 {
lab=GND}
N 630 2820 630 2870 {
lab=Y7}
N 630 2870 630 2880 {
lab=Y7}
N 0 2890 40 2890 {
lab=word48}
N 40 2890 80 2890 {
lab=word48}
N 10 2880 10 2930 {
lab=GND}
N 10 2930 10 2940 {
lab=GND}
N 70 2880 70 2930 {
lab=Y0}
N 70 2930 70 2940 {
lab=Y0}
N 80 2890 120 2890 {
lab=word48}
N 120 2890 160 2890 {
lab=word48}
N 90 2880 90 2930 {
lab=GND}
N 90 2930 90 2940 {
lab=GND}
N 150 2880 150 2930 {
lab=Y1}
N 150 2930 150 2940 {
lab=Y1}
N 160 2890 200 2890 {
lab=word48}
N 200 2890 240 2890 {
lab=word48}
N 170 2880 170 2930 {
lab=GND}
N 170 2930 170 2940 {
lab=GND}
N 230 2880 230 2930 {
lab=Y2}
N 230 2930 230 2940 {
lab=Y2}
N 240 2890 280 2890 {
lab=word48}
N 280 2890 320 2890 {
lab=word48}
N 250 2880 250 2930 {
lab=GND}
N 250 2930 250 2940 {
lab=GND}
N 310 2880 310 2930 {
lab=Y3}
N 310 2930 310 2940 {
lab=Y3}
N 320 2890 360 2890 {
lab=word48}
N 360 2890 400 2890 {
lab=word48}
N 330 2880 330 2930 {
lab=GND}
N 330 2930 330 2940 {
lab=GND}
N 390 2880 390 2930 {
lab=Y4}
N 390 2930 390 2940 {
lab=Y4}
N 400 2890 440 2890 {
lab=word48}
N 440 2890 480 2890 {
lab=word48}
N 410 2880 410 2930 {
lab=GND}
N 410 2930 410 2940 {
lab=GND}
N 470 2880 470 2930 {
lab=Y5}
N 470 2930 470 2940 {
lab=Y5}
N 480 2890 520 2890 {
lab=word48}
N 520 2890 560 2890 {
lab=word48}
N 490 2880 490 2930 {
lab=GND}
N 490 2930 490 2940 {
lab=GND}
N 550 2880 550 2930 {
lab=Y6}
N 550 2930 550 2940 {
lab=Y6}
N 560 2890 600 2890 {
lab=word48}
N 600 2890 640 2890 {
lab=word48}
N 570 2880 570 2930 {
lab=GND}
N 570 2930 570 2940 {
lab=GND}
N 630 2880 630 2930 {
lab=Y7}
N 630 2930 630 2940 {
lab=Y7}
N 0 2950 40 2950 {
lab=word49}
N 40 2950 80 2950 {
lab=word49}
N 10 2940 10 2990 {
lab=GND}
N 10 2990 10 3000 {
lab=GND}
N 70 2940 70 2990 {
lab=Y0}
N 70 2990 70 3000 {
lab=Y0}
N 80 2950 120 2950 {
lab=word49}
N 120 2950 160 2950 {
lab=word49}
N 90 2940 90 2990 {
lab=GND}
N 90 2990 90 3000 {
lab=GND}
N 150 2940 150 2990 {
lab=Y1}
N 150 2990 150 3000 {
lab=Y1}
N 160 2950 200 2950 {
lab=word49}
N 200 2950 240 2950 {
lab=word49}
N 170 2940 170 2990 {
lab=GND}
N 170 2990 170 3000 {
lab=GND}
N 230 2940 230 2990 {
lab=Y2}
N 230 2990 230 3000 {
lab=Y2}
N 240 2950 280 2950 {
lab=word49}
N 280 2950 320 2950 {
lab=word49}
N 250 2940 250 2990 {
lab=GND}
N 250 2990 250 3000 {
lab=GND}
N 310 2940 310 2990 {
lab=Y3}
N 310 2990 310 3000 {
lab=Y3}
N 330 3000 360 3000 {
lab=GND}
N 360 2990 360 3000 {
lab=GND}
N 320 2950 360 2950 {
lab=word49}
N 360 2950 400 2950 {
lab=word49}
N 330 2940 330 2990 {
lab=GND}
N 330 2990 330 3000 {
lab=GND}
N 390 2940 390 2990 {
lab=Y4}
N 390 2990 390 3000 {
lab=Y4}
N 400 2950 440 2950 {
lab=word49}
N 440 2950 480 2950 {
lab=word49}
N 410 2940 410 2990 {
lab=GND}
N 410 2990 410 3000 {
lab=GND}
N 470 2940 470 2990 {
lab=Y5}
N 470 2990 470 3000 {
lab=Y5}
N 490 3000 520 3000 {
lab=GND}
N 520 2990 520 3000 {
lab=GND}
N 480 2950 520 2950 {
lab=word49}
N 520 2950 560 2950 {
lab=word49}
N 490 2940 490 2990 {
lab=GND}
N 490 2990 490 3000 {
lab=GND}
N 550 2940 550 2990 {
lab=Y6}
N 550 2990 550 3000 {
lab=Y6}
N 560 2950 600 2950 {
lab=word49}
N 600 2950 640 2950 {
lab=word49}
N 570 2940 570 2990 {
lab=GND}
N 570 2990 570 3000 {
lab=GND}
N 630 2940 630 2990 {
lab=Y7}
N 630 2990 630 3000 {
lab=Y7}
N 0 3010 40 3010 {
lab=word50}
N 40 3010 80 3010 {
lab=word50}
N 10 3000 10 3050 {
lab=GND}
N 10 3050 10 3060 {
lab=GND}
N 70 3000 70 3050 {
lab=Y0}
N 70 3050 70 3060 {
lab=Y0}
N 80 3010 120 3010 {
lab=word50}
N 120 3010 160 3010 {
lab=word50}
N 90 3000 90 3050 {
lab=GND}
N 90 3050 90 3060 {
lab=GND}
N 150 3000 150 3050 {
lab=Y1}
N 150 3050 150 3060 {
lab=Y1}
N 170 3060 200 3060 {
lab=GND}
N 200 3050 200 3060 {
lab=GND}
N 160 3010 200 3010 {
lab=word50}
N 200 3010 240 3010 {
lab=word50}
N 170 3000 170 3050 {
lab=GND}
N 170 3050 170 3060 {
lab=GND}
N 230 3000 230 3050 {
lab=Y2}
N 230 3050 230 3060 {
lab=Y2}
N 240 3010 280 3010 {
lab=word50}
N 280 3010 320 3010 {
lab=word50}
N 250 3000 250 3050 {
lab=GND}
N 250 3050 250 3060 {
lab=GND}
N 310 3000 310 3050 {
lab=Y3}
N 310 3050 310 3060 {
lab=Y3}
N 320 3010 360 3010 {
lab=word50}
N 360 3010 400 3010 {
lab=word50}
N 330 3000 330 3050 {
lab=GND}
N 330 3050 330 3060 {
lab=GND}
N 390 3000 390 3050 {
lab=Y4}
N 390 3050 390 3060 {
lab=Y4}
N 410 3060 440 3060 {
lab=GND}
N 440 3050 440 3060 {
lab=GND}
N 400 3010 440 3010 {
lab=word50}
N 440 3010 480 3010 {
lab=word50}
N 410 3000 410 3050 {
lab=GND}
N 410 3050 410 3060 {
lab=GND}
N 470 3000 470 3050 {
lab=Y5}
N 470 3050 470 3060 {
lab=Y5}
N 480 3010 520 3010 {
lab=word50}
N 520 3010 560 3010 {
lab=word50}
N 490 3000 490 3050 {
lab=GND}
N 490 3050 490 3060 {
lab=GND}
N 550 3000 550 3050 {
lab=Y6}
N 550 3050 550 3060 {
lab=Y6}
N 570 3060 600 3060 {
lab=GND}
N 600 3050 600 3060 {
lab=GND}
N 560 3010 600 3010 {
lab=word50}
N 600 3010 640 3010 {
lab=word50}
N 570 3000 570 3050 {
lab=GND}
N 570 3050 570 3060 {
lab=GND}
N 630 3000 630 3050 {
lab=Y7}
N 630 3050 630 3060 {
lab=Y7}
N 0 3070 40 3070 {
lab=word51}
N 40 3070 80 3070 {
lab=word51}
N 10 3060 10 3110 {
lab=GND}
N 10 3110 10 3120 {
lab=GND}
N 70 3060 70 3110 {
lab=Y0}
N 70 3110 70 3120 {
lab=Y0}
N 90 3120 120 3120 {
lab=GND}
N 120 3110 120 3120 {
lab=GND}
N 80 3070 120 3070 {
lab=word51}
N 120 3070 160 3070 {
lab=word51}
N 90 3060 90 3110 {
lab=GND}
N 90 3110 90 3120 {
lab=GND}
N 150 3060 150 3110 {
lab=Y1}
N 150 3110 150 3120 {
lab=Y1}
N 160 3070 200 3070 {
lab=word51}
N 200 3070 240 3070 {
lab=word51}
N 170 3060 170 3110 {
lab=GND}
N 170 3110 170 3120 {
lab=GND}
N 230 3060 230 3110 {
lab=Y2}
N 230 3110 230 3120 {
lab=Y2}
N 240 3070 280 3070 {
lab=word51}
N 280 3070 320 3070 {
lab=word51}
N 250 3060 250 3110 {
lab=GND}
N 250 3110 250 3120 {
lab=GND}
N 310 3060 310 3110 {
lab=Y3}
N 310 3110 310 3120 {
lab=Y3}
N 330 3120 360 3120 {
lab=GND}
N 360 3110 360 3120 {
lab=GND}
N 320 3070 360 3070 {
lab=word51}
N 360 3070 400 3070 {
lab=word51}
N 330 3060 330 3110 {
lab=GND}
N 330 3110 330 3120 {
lab=GND}
N 390 3060 390 3110 {
lab=Y4}
N 390 3110 390 3120 {
lab=Y4}
N 410 3120 440 3120 {
lab=GND}
N 440 3110 440 3120 {
lab=GND}
N 400 3070 440 3070 {
lab=word51}
N 440 3070 480 3070 {
lab=word51}
N 410 3060 410 3110 {
lab=GND}
N 410 3110 410 3120 {
lab=GND}
N 470 3060 470 3110 {
lab=Y5}
N 470 3110 470 3120 {
lab=Y5}
N 490 3120 520 3120 {
lab=GND}
N 520 3110 520 3120 {
lab=GND}
N 480 3070 520 3070 {
lab=word51}
N 520 3070 560 3070 {
lab=word51}
N 490 3060 490 3110 {
lab=GND}
N 490 3110 490 3120 {
lab=GND}
N 550 3060 550 3110 {
lab=Y6}
N 550 3110 550 3120 {
lab=Y6}
N 570 3120 600 3120 {
lab=GND}
N 600 3110 600 3120 {
lab=GND}
N 560 3070 600 3070 {
lab=word51}
N 600 3070 640 3070 {
lab=word51}
N 570 3060 570 3110 {
lab=GND}
N 570 3110 570 3120 {
lab=GND}
N 630 3060 630 3110 {
lab=Y7}
N 630 3110 630 3120 {
lab=Y7}
N 10 3180 40 3180 {
lab=GND}
N 40 3170 40 3180 {
lab=GND}
N 0 3130 40 3130 {
lab=word52}
N 40 3130 80 3130 {
lab=word52}
N 10 3120 10 3170 {
lab=GND}
N 10 3170 10 3180 {
lab=GND}
N 70 3120 70 3170 {
lab=Y0}
N 70 3170 70 3180 {
lab=Y0}
N 80 3130 120 3130 {
lab=word52}
N 120 3130 160 3130 {
lab=word52}
N 90 3120 90 3170 {
lab=GND}
N 90 3170 90 3180 {
lab=GND}
N 150 3120 150 3170 {
lab=Y1}
N 150 3170 150 3180 {
lab=Y1}
N 160 3130 200 3130 {
lab=word52}
N 200 3130 240 3130 {
lab=word52}
N 170 3120 170 3170 {
lab=GND}
N 170 3170 170 3180 {
lab=GND}
N 230 3120 230 3170 {
lab=Y2}
N 230 3170 230 3180 {
lab=Y2}
N 240 3130 280 3130 {
lab=word52}
N 280 3130 320 3130 {
lab=word52}
N 250 3120 250 3170 {
lab=GND}
N 250 3170 250 3180 {
lab=GND}
N 310 3120 310 3170 {
lab=Y3}
N 310 3170 310 3180 {
lab=Y3}
N 320 3130 360 3130 {
lab=word52}
N 360 3130 400 3130 {
lab=word52}
N 330 3120 330 3170 {
lab=GND}
N 330 3170 330 3180 {
lab=GND}
N 390 3120 390 3170 {
lab=Y4}
N 390 3170 390 3180 {
lab=Y4}
N 400 3130 440 3130 {
lab=word52}
N 440 3130 480 3130 {
lab=word52}
N 410 3120 410 3170 {
lab=GND}
N 410 3170 410 3180 {
lab=GND}
N 470 3120 470 3170 {
lab=Y5}
N 470 3170 470 3180 {
lab=Y5}
N 480 3130 520 3130 {
lab=word52}
N 520 3130 560 3130 {
lab=word52}
N 490 3120 490 3170 {
lab=GND}
N 490 3170 490 3180 {
lab=GND}
N 550 3120 550 3170 {
lab=Y6}
N 550 3170 550 3180 {
lab=Y6}
N 560 3130 600 3130 {
lab=word52}
N 600 3130 640 3130 {
lab=word52}
N 570 3120 570 3170 {
lab=GND}
N 570 3170 570 3180 {
lab=GND}
N 630 3120 630 3170 {
lab=Y7}
N 630 3170 630 3180 {
lab=Y7}
N 10 3240 40 3240 {
lab=GND}
N 40 3230 40 3240 {
lab=GND}
N 0 3190 40 3190 {
lab=word53}
N 40 3190 80 3190 {
lab=word53}
N 10 3180 10 3230 {
lab=GND}
N 10 3230 10 3240 {
lab=GND}
N 70 3180 70 3230 {
lab=Y0}
N 70 3230 70 3240 {
lab=Y0}
N 80 3190 120 3190 {
lab=word53}
N 120 3190 160 3190 {
lab=word53}
N 90 3180 90 3230 {
lab=GND}
N 90 3230 90 3240 {
lab=GND}
N 150 3180 150 3230 {
lab=Y1}
N 150 3230 150 3240 {
lab=Y1}
N 170 3240 200 3240 {
lab=GND}
N 200 3230 200 3240 {
lab=GND}
N 160 3190 200 3190 {
lab=word53}
N 200 3190 240 3190 {
lab=word53}
N 170 3180 170 3230 {
lab=GND}
N 170 3230 170 3240 {
lab=GND}
N 230 3180 230 3230 {
lab=Y2}
N 230 3230 230 3240 {
lab=Y2}
N 250 3240 280 3240 {
lab=GND}
N 280 3230 280 3240 {
lab=GND}
N 240 3190 280 3190 {
lab=word53}
N 280 3190 320 3190 {
lab=word53}
N 250 3180 250 3230 {
lab=GND}
N 250 3230 250 3240 {
lab=GND}
N 310 3180 310 3230 {
lab=Y3}
N 310 3230 310 3240 {
lab=Y3}
N 320 3190 360 3190 {
lab=word53}
N 360 3190 400 3190 {
lab=word53}
N 330 3180 330 3230 {
lab=GND}
N 330 3230 330 3240 {
lab=GND}
N 390 3180 390 3230 {
lab=Y4}
N 390 3230 390 3240 {
lab=Y4}
N 400 3190 440 3190 {
lab=word53}
N 440 3190 480 3190 {
lab=word53}
N 410 3180 410 3230 {
lab=GND}
N 410 3230 410 3240 {
lab=GND}
N 470 3180 470 3230 {
lab=Y5}
N 470 3230 470 3240 {
lab=Y5}
N 480 3190 520 3190 {
lab=word53}
N 520 3190 560 3190 {
lab=word53}
N 490 3180 490 3230 {
lab=GND}
N 490 3230 490 3240 {
lab=GND}
N 550 3180 550 3230 {
lab=Y6}
N 550 3230 550 3240 {
lab=Y6}
N 560 3190 600 3190 {
lab=word53}
N 600 3190 640 3190 {
lab=word53}
N 570 3180 570 3230 {
lab=GND}
N 570 3230 570 3240 {
lab=GND}
N 630 3180 630 3230 {
lab=Y7}
N 630 3230 630 3240 {
lab=Y7}
N 10 3300 40 3300 {
lab=GND}
N 40 3290 40 3300 {
lab=GND}
N 0 3250 40 3250 {
lab=word54}
N 40 3250 80 3250 {
lab=word54}
N 10 3240 10 3290 {
lab=GND}
N 10 3290 10 3300 {
lab=GND}
N 70 3240 70 3290 {
lab=Y0}
N 70 3290 70 3300 {
lab=Y0}
N 90 3300 120 3300 {
lab=GND}
N 120 3290 120 3300 {
lab=GND}
N 80 3250 120 3250 {
lab=word54}
N 120 3250 160 3250 {
lab=word54}
N 90 3240 90 3290 {
lab=GND}
N 90 3290 90 3300 {
lab=GND}
N 150 3240 150 3290 {
lab=Y1}
N 150 3290 150 3300 {
lab=Y1}
N 160 3250 200 3250 {
lab=word54}
N 200 3250 240 3250 {
lab=word54}
N 170 3240 170 3290 {
lab=GND}
N 170 3290 170 3300 {
lab=GND}
N 230 3240 230 3290 {
lab=Y2}
N 230 3290 230 3300 {
lab=Y2}
N 250 3300 280 3300 {
lab=GND}
N 280 3290 280 3300 {
lab=GND}
N 240 3250 280 3250 {
lab=word54}
N 280 3250 320 3250 {
lab=word54}
N 250 3240 250 3290 {
lab=GND}
N 250 3290 250 3300 {
lab=GND}
N 310 3240 310 3290 {
lab=Y3}
N 310 3290 310 3300 {
lab=Y3}
N 330 3300 360 3300 {
lab=GND}
N 360 3290 360 3300 {
lab=GND}
N 320 3250 360 3250 {
lab=word54}
N 360 3250 400 3250 {
lab=word54}
N 330 3240 330 3290 {
lab=GND}
N 330 3290 330 3300 {
lab=GND}
N 390 3240 390 3290 {
lab=Y4}
N 390 3290 390 3300 {
lab=Y4}
N 400 3250 440 3250 {
lab=word54}
N 440 3250 480 3250 {
lab=word54}
N 410 3240 410 3290 {
lab=GND}
N 410 3290 410 3300 {
lab=GND}
N 470 3240 470 3290 {
lab=Y5}
N 470 3290 470 3300 {
lab=Y5}
N 490 3300 520 3300 {
lab=GND}
N 520 3290 520 3300 {
lab=GND}
N 480 3250 520 3250 {
lab=word54}
N 520 3250 560 3250 {
lab=word54}
N 490 3240 490 3290 {
lab=GND}
N 490 3290 490 3300 {
lab=GND}
N 550 3240 550 3290 {
lab=Y6}
N 550 3290 550 3300 {
lab=Y6}
N 560 3250 600 3250 {
lab=word54}
N 600 3250 640 3250 {
lab=word54}
N 570 3240 570 3290 {
lab=GND}
N 570 3290 570 3300 {
lab=GND}
N 630 3240 630 3290 {
lab=Y7}
N 630 3290 630 3300 {
lab=Y7}
N 10 3360 40 3360 {
lab=GND}
N 40 3350 40 3360 {
lab=GND}
N 0 3310 40 3310 {
lab=word55}
N 40 3310 80 3310 {
lab=word55}
N 10 3300 10 3350 {
lab=GND}
N 10 3350 10 3360 {
lab=GND}
N 70 3300 70 3350 {
lab=Y0}
N 70 3350 70 3360 {
lab=Y0}
N 90 3360 120 3360 {
lab=GND}
N 120 3350 120 3360 {
lab=GND}
N 80 3310 120 3310 {
lab=word55}
N 120 3310 160 3310 {
lab=word55}
N 90 3300 90 3350 {
lab=GND}
N 90 3350 90 3360 {
lab=GND}
N 150 3300 150 3350 {
lab=Y1}
N 150 3350 150 3360 {
lab=Y1}
N 170 3360 200 3360 {
lab=GND}
N 200 3350 200 3360 {
lab=GND}
N 160 3310 200 3310 {
lab=word55}
N 200 3310 240 3310 {
lab=word55}
N 170 3300 170 3350 {
lab=GND}
N 170 3350 170 3360 {
lab=GND}
N 230 3300 230 3350 {
lab=Y2}
N 230 3350 230 3360 {
lab=Y2}
N 250 3360 280 3360 {
lab=GND}
N 280 3350 280 3360 {
lab=GND}
N 240 3310 280 3310 {
lab=word55}
N 280 3310 320 3310 {
lab=word55}
N 250 3300 250 3350 {
lab=GND}
N 250 3350 250 3360 {
lab=GND}
N 310 3300 310 3350 {
lab=Y3}
N 310 3350 310 3360 {
lab=Y3}
N 320 3310 360 3310 {
lab=word55}
N 360 3310 400 3310 {
lab=word55}
N 330 3300 330 3350 {
lab=GND}
N 330 3350 330 3360 {
lab=GND}
N 390 3300 390 3350 {
lab=Y4}
N 390 3350 390 3360 {
lab=Y4}
N 410 3360 440 3360 {
lab=GND}
N 440 3350 440 3360 {
lab=GND}
N 400 3310 440 3310 {
lab=word55}
N 440 3310 480 3310 {
lab=word55}
N 410 3300 410 3350 {
lab=GND}
N 410 3350 410 3360 {
lab=GND}
N 470 3300 470 3350 {
lab=Y5}
N 470 3350 470 3360 {
lab=Y5}
N 480 3310 520 3310 {
lab=word55}
N 520 3310 560 3310 {
lab=word55}
N 490 3300 490 3350 {
lab=GND}
N 490 3350 490 3360 {
lab=GND}
N 550 3300 550 3350 {
lab=Y6}
N 550 3350 550 3360 {
lab=Y6}
N 570 3360 600 3360 {
lab=GND}
N 600 3350 600 3360 {
lab=GND}
N 560 3310 600 3310 {
lab=word55}
N 600 3310 640 3310 {
lab=word55}
N 570 3300 570 3350 {
lab=GND}
N 570 3350 570 3360 {
lab=GND}
N 630 3300 630 3350 {
lab=Y7}
N 630 3350 630 3360 {
lab=Y7}
N 10 3420 40 3420 {
lab=GND}
N 40 3410 40 3420 {
lab=GND}
N 0 3370 40 3370 {
lab=word56}
N 40 3370 80 3370 {
lab=word56}
N 10 3360 10 3410 {
lab=GND}
N 10 3410 10 3420 {
lab=GND}
N 70 3360 70 3410 {
lab=Y0}
N 70 3410 70 3420 {
lab=Y0}
N 90 3420 120 3420 {
lab=GND}
N 120 3410 120 3420 {
lab=GND}
N 80 3370 120 3370 {
lab=word56}
N 120 3370 160 3370 {
lab=word56}
N 90 3360 90 3410 {
lab=GND}
N 90 3410 90 3420 {
lab=GND}
N 150 3360 150 3410 {
lab=Y1}
N 150 3410 150 3420 {
lab=Y1}
N 170 3420 200 3420 {
lab=GND}
N 200 3410 200 3420 {
lab=GND}
N 160 3370 200 3370 {
lab=word56}
N 200 3370 240 3370 {
lab=word56}
N 170 3360 170 3410 {
lab=GND}
N 170 3410 170 3420 {
lab=GND}
N 230 3360 230 3410 {
lab=Y2}
N 230 3410 230 3420 {
lab=Y2}
N 250 3420 280 3420 {
lab=GND}
N 280 3410 280 3420 {
lab=GND}
N 240 3370 280 3370 {
lab=word56}
N 280 3370 320 3370 {
lab=word56}
N 250 3360 250 3410 {
lab=GND}
N 250 3410 250 3420 {
lab=GND}
N 310 3360 310 3410 {
lab=Y3}
N 310 3410 310 3420 {
lab=Y3}
N 330 3420 360 3420 {
lab=GND}
N 360 3410 360 3420 {
lab=GND}
N 320 3370 360 3370 {
lab=word56}
N 360 3370 400 3370 {
lab=word56}
N 330 3360 330 3410 {
lab=GND}
N 330 3410 330 3420 {
lab=GND}
N 390 3360 390 3410 {
lab=Y4}
N 390 3410 390 3420 {
lab=Y4}
N 410 3420 440 3420 {
lab=GND}
N 440 3410 440 3420 {
lab=GND}
N 400 3370 440 3370 {
lab=word56}
N 440 3370 480 3370 {
lab=word56}
N 410 3360 410 3410 {
lab=GND}
N 410 3410 410 3420 {
lab=GND}
N 470 3360 470 3410 {
lab=Y5}
N 470 3410 470 3420 {
lab=Y5}
N 490 3420 520 3420 {
lab=GND}
N 520 3410 520 3420 {
lab=GND}
N 480 3370 520 3370 {
lab=word56}
N 520 3370 560 3370 {
lab=word56}
N 490 3360 490 3410 {
lab=GND}
N 490 3410 490 3420 {
lab=GND}
N 550 3360 550 3410 {
lab=Y6}
N 550 3410 550 3420 {
lab=Y6}
N 570 3420 600 3420 {
lab=GND}
N 600 3410 600 3420 {
lab=GND}
N 560 3370 600 3370 {
lab=word56}
N 600 3370 640 3370 {
lab=word56}
N 570 3360 570 3410 {
lab=GND}
N 570 3410 570 3420 {
lab=GND}
N 630 3360 630 3410 {
lab=Y7}
N 630 3410 630 3420 {
lab=Y7}
N 10 3480 40 3480 {
lab=GND}
N 40 3470 40 3480 {
lab=GND}
N 0 3430 40 3430 {
lab=word57}
N 40 3430 80 3430 {
lab=word57}
N 10 3420 10 3470 {
lab=GND}
N 10 3470 10 3480 {
lab=GND}
N 70 3420 70 3470 {
lab=Y0}
N 70 3470 70 3480 {
lab=Y0}
N 90 3480 120 3480 {
lab=GND}
N 120 3470 120 3480 {
lab=GND}
N 80 3430 120 3430 {
lab=word57}
N 120 3430 160 3430 {
lab=word57}
N 90 3420 90 3470 {
lab=GND}
N 90 3470 90 3480 {
lab=GND}
N 150 3420 150 3470 {
lab=Y1}
N 150 3470 150 3480 {
lab=Y1}
N 170 3480 200 3480 {
lab=GND}
N 200 3470 200 3480 {
lab=GND}
N 160 3430 200 3430 {
lab=word57}
N 200 3430 240 3430 {
lab=word57}
N 170 3420 170 3470 {
lab=GND}
N 170 3470 170 3480 {
lab=GND}
N 230 3420 230 3470 {
lab=Y2}
N 230 3470 230 3480 {
lab=Y2}
N 250 3480 280 3480 {
lab=GND}
N 280 3470 280 3480 {
lab=GND}
N 240 3430 280 3430 {
lab=word57}
N 280 3430 320 3430 {
lab=word57}
N 250 3420 250 3470 {
lab=GND}
N 250 3470 250 3480 {
lab=GND}
N 310 3420 310 3470 {
lab=Y3}
N 310 3470 310 3480 {
lab=Y3}
N 320 3430 360 3430 {
lab=word57}
N 360 3430 400 3430 {
lab=word57}
N 330 3420 330 3470 {
lab=GND}
N 330 3470 330 3480 {
lab=GND}
N 390 3420 390 3470 {
lab=Y4}
N 390 3470 390 3480 {
lab=Y4}
N 410 3480 440 3480 {
lab=GND}
N 440 3470 440 3480 {
lab=GND}
N 400 3430 440 3430 {
lab=word57}
N 440 3430 480 3430 {
lab=word57}
N 410 3420 410 3470 {
lab=GND}
N 410 3470 410 3480 {
lab=GND}
N 470 3420 470 3470 {
lab=Y5}
N 470 3470 470 3480 {
lab=Y5}
N 480 3430 520 3430 {
lab=word57}
N 520 3430 560 3430 {
lab=word57}
N 490 3420 490 3470 {
lab=GND}
N 490 3470 490 3480 {
lab=GND}
N 550 3420 550 3470 {
lab=Y6}
N 550 3470 550 3480 {
lab=Y6}
N 570 3480 600 3480 {
lab=GND}
N 600 3470 600 3480 {
lab=GND}
N 560 3430 600 3430 {
lab=word57}
N 600 3430 640 3430 {
lab=word57}
N 570 3420 570 3470 {
lab=GND}
N 570 3470 570 3480 {
lab=GND}
N 630 3420 630 3470 {
lab=Y7}
N 630 3470 630 3480 {
lab=Y7}
N 10 3540 40 3540 {
lab=GND}
N 40 3530 40 3540 {
lab=GND}
N 0 3490 40 3490 {
lab=word58}
N 40 3490 80 3490 {
lab=word58}
N 10 3480 10 3530 {
lab=GND}
N 10 3530 10 3540 {
lab=GND}
N 70 3480 70 3530 {
lab=Y0}
N 70 3530 70 3540 {
lab=Y0}
N 90 3540 120 3540 {
lab=GND}
N 120 3530 120 3540 {
lab=GND}
N 80 3490 120 3490 {
lab=word58}
N 120 3490 160 3490 {
lab=word58}
N 90 3480 90 3530 {
lab=GND}
N 90 3530 90 3540 {
lab=GND}
N 150 3480 150 3530 {
lab=Y1}
N 150 3530 150 3540 {
lab=Y1}
N 160 3490 200 3490 {
lab=word58}
N 200 3490 240 3490 {
lab=word58}
N 170 3480 170 3530 {
lab=GND}
N 170 3530 170 3540 {
lab=GND}
N 230 3480 230 3530 {
lab=Y2}
N 230 3530 230 3540 {
lab=Y2}
N 250 3540 280 3540 {
lab=GND}
N 280 3530 280 3540 {
lab=GND}
N 240 3490 280 3490 {
lab=word58}
N 280 3490 320 3490 {
lab=word58}
N 250 3480 250 3530 {
lab=GND}
N 250 3530 250 3540 {
lab=GND}
N 310 3480 310 3530 {
lab=Y3}
N 310 3530 310 3540 {
lab=Y3}
N 330 3540 360 3540 {
lab=GND}
N 360 3530 360 3540 {
lab=GND}
N 320 3490 360 3490 {
lab=word58}
N 360 3490 400 3490 {
lab=word58}
N 330 3480 330 3530 {
lab=GND}
N 330 3530 330 3540 {
lab=GND}
N 390 3480 390 3530 {
lab=Y4}
N 390 3530 390 3540 {
lab=Y4}
N 400 3490 440 3490 {
lab=word58}
N 440 3490 480 3490 {
lab=word58}
N 410 3480 410 3530 {
lab=GND}
N 410 3530 410 3540 {
lab=GND}
N 470 3480 470 3530 {
lab=Y5}
N 470 3530 470 3540 {
lab=Y5}
N 490 3540 520 3540 {
lab=GND}
N 520 3530 520 3540 {
lab=GND}
N 480 3490 520 3490 {
lab=word58}
N 520 3490 560 3490 {
lab=word58}
N 490 3480 490 3530 {
lab=GND}
N 490 3530 490 3540 {
lab=GND}
N 550 3480 550 3530 {
lab=Y6}
N 550 3530 550 3540 {
lab=Y6}
N 560 3490 600 3490 {
lab=word58}
N 600 3490 640 3490 {
lab=word58}
N 570 3480 570 3530 {
lab=GND}
N 570 3530 570 3540 {
lab=GND}
N 630 3480 630 3530 {
lab=Y7}
N 630 3530 630 3540 {
lab=Y7}
N 10 3600 40 3600 {
lab=GND}
N 40 3590 40 3600 {
lab=GND}
N 0 3550 40 3550 {
lab=word59}
N 40 3550 80 3550 {
lab=word59}
N 10 3540 10 3590 {
lab=GND}
N 10 3590 10 3600 {
lab=GND}
N 70 3540 70 3590 {
lab=Y0}
N 70 3590 70 3600 {
lab=Y0}
N 80 3550 120 3550 {
lab=word59}
N 120 3550 160 3550 {
lab=word59}
N 90 3540 90 3590 {
lab=GND}
N 90 3590 90 3600 {
lab=GND}
N 150 3540 150 3590 {
lab=Y1}
N 150 3590 150 3600 {
lab=Y1}
N 170 3600 200 3600 {
lab=GND}
N 200 3590 200 3600 {
lab=GND}
N 160 3550 200 3550 {
lab=word59}
N 200 3550 240 3550 {
lab=word59}
N 170 3540 170 3590 {
lab=GND}
N 170 3590 170 3600 {
lab=GND}
N 230 3540 230 3590 {
lab=Y2}
N 230 3590 230 3600 {
lab=Y2}
N 250 3600 280 3600 {
lab=GND}
N 280 3590 280 3600 {
lab=GND}
N 240 3550 280 3550 {
lab=word59}
N 280 3550 320 3550 {
lab=word59}
N 250 3540 250 3590 {
lab=GND}
N 250 3590 250 3600 {
lab=GND}
N 310 3540 310 3590 {
lab=Y3}
N 310 3590 310 3600 {
lab=Y3}
N 320 3550 360 3550 {
lab=word59}
N 360 3550 400 3550 {
lab=word59}
N 330 3540 330 3590 {
lab=GND}
N 330 3590 330 3600 {
lab=GND}
N 390 3540 390 3590 {
lab=Y4}
N 390 3590 390 3600 {
lab=Y4}
N 400 3550 440 3550 {
lab=word59}
N 440 3550 480 3550 {
lab=word59}
N 410 3540 410 3590 {
lab=GND}
N 410 3590 410 3600 {
lab=GND}
N 470 3540 470 3590 {
lab=Y5}
N 470 3590 470 3600 {
lab=Y5}
N 480 3550 520 3550 {
lab=word59}
N 520 3550 560 3550 {
lab=word59}
N 490 3540 490 3590 {
lab=GND}
N 490 3590 490 3600 {
lab=GND}
N 550 3540 550 3590 {
lab=Y6}
N 550 3590 550 3600 {
lab=Y6}
N 560 3550 600 3550 {
lab=word59}
N 600 3550 640 3550 {
lab=word59}
N 570 3540 570 3590 {
lab=GND}
N 570 3590 570 3600 {
lab=GND}
N 630 3540 630 3590 {
lab=Y7}
N 630 3590 630 3600 {
lab=Y7}
N 10 3660 40 3660 {
lab=GND}
N 40 3650 40 3660 {
lab=GND}
N 0 3610 40 3610 {
lab=word60}
N 40 3610 80 3610 {
lab=word60}
N 10 3600 10 3650 {
lab=GND}
N 10 3650 10 3660 {
lab=GND}
N 70 3600 70 3650 {
lab=Y0}
N 70 3650 70 3660 {
lab=Y0}
N 80 3610 120 3610 {
lab=word60}
N 120 3610 160 3610 {
lab=word60}
N 90 3600 90 3650 {
lab=GND}
N 90 3650 90 3660 {
lab=GND}
N 150 3600 150 3650 {
lab=Y1}
N 150 3650 150 3660 {
lab=Y1}
N 160 3610 200 3610 {
lab=word60}
N 200 3610 240 3610 {
lab=word60}
N 170 3600 170 3650 {
lab=GND}
N 170 3650 170 3660 {
lab=GND}
N 230 3600 230 3650 {
lab=Y2}
N 230 3650 230 3660 {
lab=Y2}
N 240 3610 280 3610 {
lab=word60}
N 280 3610 320 3610 {
lab=word60}
N 250 3600 250 3650 {
lab=GND}
N 250 3650 250 3660 {
lab=GND}
N 310 3600 310 3650 {
lab=Y3}
N 310 3650 310 3660 {
lab=Y3}
N 320 3610 360 3610 {
lab=word60}
N 360 3610 400 3610 {
lab=word60}
N 330 3600 330 3650 {
lab=GND}
N 330 3650 330 3660 {
lab=GND}
N 390 3600 390 3650 {
lab=Y4}
N 390 3650 390 3660 {
lab=Y4}
N 400 3610 440 3610 {
lab=word60}
N 440 3610 480 3610 {
lab=word60}
N 410 3600 410 3650 {
lab=GND}
N 410 3650 410 3660 {
lab=GND}
N 470 3600 470 3650 {
lab=Y5}
N 470 3650 470 3660 {
lab=Y5}
N 480 3610 520 3610 {
lab=word60}
N 520 3610 560 3610 {
lab=word60}
N 490 3600 490 3650 {
lab=GND}
N 490 3650 490 3660 {
lab=GND}
N 550 3600 550 3650 {
lab=Y6}
N 550 3650 550 3660 {
lab=Y6}
N 560 3610 600 3610 {
lab=word60}
N 600 3610 640 3610 {
lab=word60}
N 570 3600 570 3650 {
lab=GND}
N 570 3650 570 3660 {
lab=GND}
N 630 3600 630 3650 {
lab=Y7}
N 630 3650 630 3660 {
lab=Y7}
N 0 3670 40 3670 {
lab=word61}
N 40 3670 80 3670 {
lab=word61}
N 10 3660 10 3710 {
lab=GND}
N 10 3710 10 3720 {
lab=GND}
N 70 3660 70 3710 {
lab=Y0}
N 70 3710 70 3720 {
lab=Y0}
N 90 3720 120 3720 {
lab=GND}
N 120 3710 120 3720 {
lab=GND}
N 80 3670 120 3670 {
lab=word61}
N 120 3670 160 3670 {
lab=word61}
N 90 3660 90 3710 {
lab=GND}
N 90 3710 90 3720 {
lab=GND}
N 150 3660 150 3710 {
lab=Y1}
N 150 3710 150 3720 {
lab=Y1}
N 160 3670 200 3670 {
lab=word61}
N 200 3670 240 3670 {
lab=word61}
N 170 3660 170 3710 {
lab=GND}
N 170 3710 170 3720 {
lab=GND}
N 230 3660 230 3710 {
lab=Y2}
N 230 3710 230 3720 {
lab=Y2}
N 240 3670 280 3670 {
lab=word61}
N 280 3670 320 3670 {
lab=word61}
N 250 3660 250 3710 {
lab=GND}
N 250 3710 250 3720 {
lab=GND}
N 310 3660 310 3710 {
lab=Y3}
N 310 3710 310 3720 {
lab=Y3}
N 330 3720 360 3720 {
lab=GND}
N 360 3710 360 3720 {
lab=GND}
N 320 3670 360 3670 {
lab=word61}
N 360 3670 400 3670 {
lab=word61}
N 330 3660 330 3710 {
lab=GND}
N 330 3710 330 3720 {
lab=GND}
N 390 3660 390 3710 {
lab=Y4}
N 390 3710 390 3720 {
lab=Y4}
N 410 3720 440 3720 {
lab=GND}
N 440 3710 440 3720 {
lab=GND}
N 400 3670 440 3670 {
lab=word61}
N 440 3670 480 3670 {
lab=word61}
N 410 3660 410 3710 {
lab=GND}
N 410 3710 410 3720 {
lab=GND}
N 470 3660 470 3710 {
lab=Y5}
N 470 3710 470 3720 {
lab=Y5}
N 490 3720 520 3720 {
lab=GND}
N 520 3710 520 3720 {
lab=GND}
N 480 3670 520 3670 {
lab=word61}
N 520 3670 560 3670 {
lab=word61}
N 490 3660 490 3710 {
lab=GND}
N 490 3710 490 3720 {
lab=GND}
N 550 3660 550 3710 {
lab=Y6}
N 550 3710 550 3720 {
lab=Y6}
N 570 3720 600 3720 {
lab=GND}
N 600 3710 600 3720 {
lab=GND}
N 560 3670 600 3670 {
lab=word61}
N 600 3670 640 3670 {
lab=word61}
N 570 3660 570 3710 {
lab=GND}
N 570 3710 570 3720 {
lab=GND}
N 630 3660 630 3710 {
lab=Y7}
N 630 3710 630 3720 {
lab=Y7}
N 0 3730 40 3730 {
lab=word62}
N 40 3730 80 3730 {
lab=word62}
N 10 3720 10 3770 {
lab=GND}
N 10 3770 10 3780 {
lab=GND}
N 70 3720 70 3770 {
lab=Y0}
N 70 3770 70 3780 {
lab=Y0}
N 80 3730 120 3730 {
lab=word62}
N 120 3730 160 3730 {
lab=word62}
N 90 3720 90 3770 {
lab=GND}
N 90 3770 90 3780 {
lab=GND}
N 150 3720 150 3770 {
lab=Y1}
N 150 3770 150 3780 {
lab=Y1}
N 170 3780 200 3780 {
lab=GND}
N 200 3770 200 3780 {
lab=GND}
N 160 3730 200 3730 {
lab=word62}
N 200 3730 240 3730 {
lab=word62}
N 170 3720 170 3770 {
lab=GND}
N 170 3770 170 3780 {
lab=GND}
N 230 3720 230 3770 {
lab=Y2}
N 230 3770 230 3780 {
lab=Y2}
N 240 3730 280 3730 {
lab=word62}
N 280 3730 320 3730 {
lab=word62}
N 250 3720 250 3770 {
lab=GND}
N 250 3770 250 3780 {
lab=GND}
N 310 3720 310 3770 {
lab=Y3}
N 310 3770 310 3780 {
lab=Y3}
N 320 3730 360 3730 {
lab=word62}
N 360 3730 400 3730 {
lab=word62}
N 330 3720 330 3770 {
lab=GND}
N 330 3770 330 3780 {
lab=GND}
N 390 3720 390 3770 {
lab=Y4}
N 390 3770 390 3780 {
lab=Y4}
N 410 3780 440 3780 {
lab=GND}
N 440 3770 440 3780 {
lab=GND}
N 400 3730 440 3730 {
lab=word62}
N 440 3730 480 3730 {
lab=word62}
N 410 3720 410 3770 {
lab=GND}
N 410 3770 410 3780 {
lab=GND}
N 470 3720 470 3770 {
lab=Y5}
N 470 3770 470 3780 {
lab=Y5}
N 480 3730 520 3730 {
lab=word62}
N 520 3730 560 3730 {
lab=word62}
N 490 3720 490 3770 {
lab=GND}
N 490 3770 490 3780 {
lab=GND}
N 550 3720 550 3770 {
lab=Y6}
N 550 3770 550 3780 {
lab=Y6}
N 570 3780 600 3780 {
lab=GND}
N 600 3770 600 3780 {
lab=GND}
N 560 3730 600 3730 {
lab=word62}
N 600 3730 640 3730 {
lab=word62}
N 570 3720 570 3770 {
lab=GND}
N 570 3770 570 3780 {
lab=GND}
N 630 3720 630 3770 {
lab=Y7}
N 630 3770 630 3780 {
lab=Y7}
N 0 3790 40 3790 {
lab=word63}
N 40 3790 80 3790 {
lab=word63}
N 10 3780 10 3830 {
lab=GND}
N 10 3830 10 3840 {
lab=GND}
N 70 3780 70 3830 {
lab=Y0}
N 70 3830 70 3840 {
lab=Y0}
N 80 3790 120 3790 {
lab=word63}
N 120 3790 160 3790 {
lab=word63}
N 90 3780 90 3830 {
lab=GND}
N 90 3830 90 3840 {
lab=GND}
N 150 3780 150 3830 {
lab=Y1}
N 150 3830 150 3840 {
lab=Y1}
N 160 3790 200 3790 {
lab=word63}
N 200 3790 240 3790 {
lab=word63}
N 170 3780 170 3830 {
lab=GND}
N 170 3830 170 3840 {
lab=GND}
N 230 3780 230 3830 {
lab=Y2}
N 230 3830 230 3840 {
lab=Y2}
N 240 3790 280 3790 {
lab=word63}
N 280 3790 320 3790 {
lab=word63}
N 250 3780 250 3830 {
lab=GND}
N 250 3830 250 3840 {
lab=GND}
N 310 3780 310 3830 {
lab=Y3}
N 310 3830 310 3840 {
lab=Y3}
N 330 3840 360 3840 {
lab=GND}
N 360 3830 360 3840 {
lab=GND}
N 320 3790 360 3790 {
lab=word63}
N 360 3790 400 3790 {
lab=word63}
N 330 3780 330 3830 {
lab=GND}
N 330 3830 330 3840 {
lab=GND}
N 390 3780 390 3830 {
lab=Y4}
N 390 3830 390 3840 {
lab=Y4}
N 400 3790 440 3790 {
lab=word63}
N 440 3790 480 3790 {
lab=word63}
N 410 3780 410 3830 {
lab=GND}
N 410 3830 410 3840 {
lab=GND}
N 470 3780 470 3830 {
lab=Y5}
N 470 3830 470 3840 {
lab=Y5}
N 490 3840 520 3840 {
lab=GND}
N 520 3830 520 3840 {
lab=GND}
N 480 3790 520 3790 {
lab=word63}
N 520 3790 560 3790 {
lab=word63}
N 490 3780 490 3830 {
lab=GND}
N 490 3830 490 3840 {
lab=GND}
N 550 3780 550 3830 {
lab=Y6}
N 550 3830 550 3840 {
lab=Y6}
N 560 3790 600 3790 {
lab=word63}
N 600 3790 640 3790 {
lab=word63}
N 570 3780 570 3830 {
lab=GND}
N 570 3830 570 3840 {
lab=GND}
N 630 3780 630 3830 {
lab=Y7}
N 630 3830 630 3840 {
lab=Y7}
C {devices/gnd.sym} 10 -30 2 0 {name=l1 lab=GND}
C {devices/lab_wire.sym} 90 0 0 1 {name=p1 sig_type=std_logic lab=GND}
C {devices/lab_wire.sym} 170 0 0 1 {name=p2 sig_type=std_logic lab=GND}
C {devices/lab_wire.sym} 250 0 0 1 {name=p3 sig_type=std_logic lab=GND}
C {devices/lab_wire.sym} 330 0 0 1 {name=p4 sig_type=std_logic lab=GND}
C {devices/lab_wire.sym} 410 0 0 1 {name=p5 sig_type=std_logic lab=GND}
C {devices/lab_wire.sym} 490 0 0 1 {name=p6 sig_type=std_logic lab=GND}
C {devices/lab_wire.sym} 570 0 0 1 {name=p7 sig_type=std_logic lab=GND}
C {sky130_fd_pr/pfet_01v8.sym} 50 -80 0 0 {name=M1
L=0.15
W=1
nf=1
mult=1
ad="'int((nf+1)/2) * W/nf * 0.29'" 
pd="'2*int((nf+1)/2) * (W/nf + 0.29)'"
as="'int((nf+2)/2) * W/nf * 0.29'" 
ps="'2*int((nf+2)/2) * (W/nf + 0.29)'"
nrd="'0.29 / W'" nrs="'0.29 / W'"
sa=0 sb=0 sd=0
model=pfet_01v8
spiceprefix=X
}
C {devices/lab_wire.sym} 20 -80 0 0 {name=p8 sig_type=std_logic lab=GND}
C {devices/vdd.sym} 70 -120 0 0 {name=l2 lab=VDD}
C {sky130_fd_pr/pfet_01v8.sym} 130 -80 0 0 {name=M2
L=0.15
W=1
nf=1
mult=1
ad="'int((nf+1)/2) * W/nf * 0.29'" 
pd="'2*int((nf+1)/2) * (W/nf + 0.29)'"
as="'int((nf+2)/2) * W/nf * 0.29'" 
ps="'2*int((nf+2)/2) * (W/nf + 0.29)'"
nrd="'0.29 / W'" nrs="'0.29 / W'"
sa=0 sb=0 sd=0
model=pfet_01v8
spiceprefix=X
}
C {sky130_fd_pr/pfet_01v8.sym} 210 -80 0 0 {name=M3
L=0.15
W=1
nf=1
mult=1
ad="'int((nf+1)/2) * W/nf * 0.29'" 
pd="'2*int((nf+1)/2) * (W/nf + 0.29)'"
as="'int((nf+2)/2) * W/nf * 0.29'" 
ps="'2*int((nf+2)/2) * (W/nf + 0.29)'"
nrd="'0.29 / W'" nrs="'0.29 / W'"
sa=0 sb=0 sd=0
model=pfet_01v8
spiceprefix=X
}
C {sky130_fd_pr/pfet_01v8.sym} 290 -80 0 0 {name=M4
L=0.15
W=1
nf=1
mult=1
ad="'int((nf+1)/2) * W/nf * 0.29'" 
pd="'2*int((nf+1)/2) * (W/nf + 0.29)'"
as="'int((nf+2)/2) * W/nf * 0.29'" 
ps="'2*int((nf+2)/2) * (W/nf + 0.29)'"
nrd="'0.29 / W'" nrs="'0.29 / W'"
sa=0 sb=0 sd=0
model=pfet_01v8
spiceprefix=X
}
C {sky130_fd_pr/pfet_01v8.sym} 370 -80 0 0 {name=M5
L=0.15
W=1
nf=1
mult=1
ad="'int((nf+1)/2) * W/nf * 0.29'" 
pd="'2*int((nf+1)/2) * (W/nf + 0.29)'"
as="'int((nf+2)/2) * W/nf * 0.29'" 
ps="'2*int((nf+2)/2) * (W/nf + 0.29)'"
nrd="'0.29 / W'" nrs="'0.29 / W'"
sa=0 sb=0 sd=0
model=pfet_01v8
spiceprefix=X
}
C {sky130_fd_pr/pfet_01v8.sym} 450 -80 0 0 {name=M6
L=0.15
W=1
nf=1
mult=1
ad="'int((nf+1)/2) * W/nf * 0.29'" 
pd="'2*int((nf+1)/2) * (W/nf + 0.29)'"
as="'int((nf+2)/2) * W/nf * 0.29'" 
ps="'2*int((nf+2)/2) * (W/nf + 0.29)'"
nrd="'0.29 / W'" nrs="'0.29 / W'"
sa=0 sb=0 sd=0
model=pfet_01v8
spiceprefix=X
}
C {sky130_fd_pr/pfet_01v8.sym} 530 -80 0 0 {name=M7
L=0.15
W=1
nf=1
mult=1
ad="'int((nf+1)/2) * W/nf * 0.29'" 
pd="'2*int((nf+1)/2) * (W/nf + 0.29)'"
as="'int((nf+2)/2) * W/nf * 0.29'" 
ps="'2*int((nf+2)/2) * (W/nf + 0.29)'"
nrd="'0.29 / W'" nrs="'0.29 / W'"
sa=0 sb=0 sd=0
model=pfet_01v8
spiceprefix=X
}
C {sky130_fd_pr/pfet_01v8.sym} 610 -80 0 0 {name=M8
L=0.15
W=1
nf=1
mult=1
ad="'int((nf+1)/2) * W/nf * 0.29'" 
pd="'2*int((nf+1)/2) * (W/nf + 0.29)'"
as="'int((nf+2)/2) * W/nf * 0.29'" 
ps="'2*int((nf+2)/2) * (W/nf + 0.29)'"
nrd="'0.29 / W'" nrs="'0.29 / W'"
sa=0 sb=0 sd=0
model=pfet_01v8
spiceprefix=X
}
C {devices/lab_wire.sym} 150 -120 0 1 {name=p9 sig_type=std_logic lab=VDD
}
C {devices/lab_wire.sym} 470 -120 0 1 {name=p10 sig_type=std_logic lab=VDD
}
C {devices/lab_wire.sym} 550 -120 0 1 {name=p11 sig_type=std_logic lab=VDD
}
C {devices/lab_wire.sym} 630 -120 0 1 {name=p12 sig_type=std_logic lab=VDD
}
C {devices/lab_wire.sym} 230 -120 0 1 {name=p13 sig_type=std_logic lab=VDD
}
C {devices/lab_wire.sym} 310 -120 0 1 {name=p14 sig_type=std_logic lab=VDD
}
C {devices/lab_wire.sym} 390 -120 0 1 {name=p15 sig_type=std_logic lab=VDD
}
C {devices/lab_wire.sym} 100 -80 0 0 {name=p16 sig_type=std_logic lab=GND}
C {devices/lab_wire.sym} 180 -80 0 0 {name=p17 sig_type=std_logic lab=GND}
C {devices/lab_wire.sym} 260 -80 0 0 {name=p18 sig_type=std_logic lab=GND}
C {devices/lab_wire.sym} 340 -80 0 0 {name=p19 sig_type=std_logic lab=GND}
C {devices/lab_wire.sym} 420 -80 0 0 {name=p20 sig_type=std_logic lab=GND}
C {devices/lab_wire.sym} 500 -80 0 0 {name=p21 sig_type=std_logic lab=GND}
C {devices/lab_wire.sym} 580 -80 0 0 {name=p22 sig_type=std_logic lab=GND}
C {devices/ipin.sym} 0 10 0 0 {name=p23 lab=word0}
C {devices/ipin.sym} 0 70 0 0 {name=p24 lab=word1}
C {devices/ipin.sym} 0 130 0 0 {name=p25 lab=word2}
C {devices/ipin.sym} 0 190 0 0 {name=p26 lab=word3}
C {devices/ipin.sym} 0 250 0 0 {name=p27 lab=word4}
C {devices/ipin.sym} 0 310 0 0 {name=p28 lab=word5}
C {devices/ipin.sym} 0 370 0 0 {name=p29 lab=word6}
C {devices/ipin.sym} 0 430 0 0 {name=p30 lab=word7}
C {devices/ipin.sym} 0 490 0 0 {name=p31 lab=word8}
C {sky130_fd_pr/nfet_01v8.sym} 40 510 1 0 {name=M9
L=0.15
W=1
nf=1 
mult=1
ad="'int((nf+1)/2) * W/nf * 0.29'" 
pd="'2*int((nf+1)/2) * (W/nf + 0.29)'"
as="'int((nf+2)/2) * W/nf * 0.29'" 
ps="'2*int((nf+2)/2) * (W/nf + 0.29)'"
nrd="'0.29 / W'" nrs="'0.29 / W'"
sa=0 sb=0 sd=0
model=nfet_01v8
spiceprefix=X
}
C {sky130_fd_pr/nfet_01v8.sym} 120 510 1 0 {name=M10
L=0.15
W=1
nf=1 
mult=1
ad="'int((nf+1)/2) * W/nf * 0.29'" 
pd="'2*int((nf+1)/2) * (W/nf + 0.29)'"
as="'int((nf+2)/2) * W/nf * 0.29'" 
ps="'2*int((nf+2)/2) * (W/nf + 0.29)'"
nrd="'0.29 / W'" nrs="'0.29 / W'"
sa=0 sb=0 sd=0
model=nfet_01v8
spiceprefix=X
}
C {sky130_fd_pr/nfet_01v8.sym} 200 510 1 0 {name=M11
L=0.15
W=1
nf=1 
mult=1
ad="'int((nf+1)/2) * W/nf * 0.29'" 
pd="'2*int((nf+1)/2) * (W/nf + 0.29)'"
as="'int((nf+2)/2) * W/nf * 0.29'" 
ps="'2*int((nf+2)/2) * (W/nf + 0.29)'"
nrd="'0.29 / W'" nrs="'0.29 / W'"
sa=0 sb=0 sd=0
model=nfet_01v8
spiceprefix=X
}
C {sky130_fd_pr/nfet_01v8.sym} 280 510 1 0 {name=M12
L=0.15
W=1
nf=1 
mult=1
ad="'int((nf+1)/2) * W/nf * 0.29'" 
pd="'2*int((nf+1)/2) * (W/nf + 0.29)'"
as="'int((nf+2)/2) * W/nf * 0.29'" 
ps="'2*int((nf+2)/2) * (W/nf + 0.29)'"
nrd="'0.29 / W'" nrs="'0.29 / W'"
sa=0 sb=0 sd=0
model=nfet_01v8
spiceprefix=X
}
C {sky130_fd_pr/nfet_01v8.sym} 360 510 1 0 {name=M13
L=0.15
W=1
nf=1 
mult=1
ad="'int((nf+1)/2) * W/nf * 0.29'" 
pd="'2*int((nf+1)/2) * (W/nf + 0.29)'"
as="'int((nf+2)/2) * W/nf * 0.29'" 
ps="'2*int((nf+2)/2) * (W/nf + 0.29)'"
nrd="'0.29 / W'" nrs="'0.29 / W'"
sa=0 sb=0 sd=0
model=nfet_01v8
spiceprefix=X
}
C {sky130_fd_pr/nfet_01v8.sym} 440 510 1 0 {name=M14
L=0.15
W=1
nf=1 
mult=1
ad="'int((nf+1)/2) * W/nf * 0.29'" 
pd="'2*int((nf+1)/2) * (W/nf + 0.29)'"
as="'int((nf+2)/2) * W/nf * 0.29'" 
ps="'2*int((nf+2)/2) * (W/nf + 0.29)'"
nrd="'0.29 / W'" nrs="'0.29 / W'"
sa=0 sb=0 sd=0
model=nfet_01v8
spiceprefix=X
}
C {sky130_fd_pr/nfet_01v8.sym} 520 510 1 0 {name=M15
L=0.15
W=1
nf=1 
mult=1
ad="'int((nf+1)/2) * W/nf * 0.29'" 
pd="'2*int((nf+1)/2) * (W/nf + 0.29)'"
as="'int((nf+2)/2) * W/nf * 0.29'" 
ps="'2*int((nf+2)/2) * (W/nf + 0.29)'"
nrd="'0.29 / W'" nrs="'0.29 / W'"
sa=0 sb=0 sd=0
model=nfet_01v8
spiceprefix=X
}
C {sky130_fd_pr/nfet_01v8.sym} 600 510 1 0 {name=M16
L=0.15
W=1
nf=1 
mult=1
ad="'int((nf+1)/2) * W/nf * 0.29'" 
pd="'2*int((nf+1)/2) * (W/nf + 0.29)'"
as="'int((nf+2)/2) * W/nf * 0.29'" 
ps="'2*int((nf+2)/2) * (W/nf + 0.29)'"
nrd="'0.29 / W'" nrs="'0.29 / W'"
sa=0 sb=0 sd=0
model=nfet_01v8
spiceprefix=X
}
C {devices/ipin.sym} 0 550 0 0 {name=p32 lab=word9}
C {sky130_fd_pr/nfet_01v8.sym} 40 570 1 0 {name=M17
L=0.15
W=1
nf=1 
mult=1
ad="'int((nf+1)/2) * W/nf * 0.29'" 
pd="'2*int((nf+1)/2) * (W/nf + 0.29)'"
as="'int((nf+2)/2) * W/nf * 0.29'" 
ps="'2*int((nf+2)/2) * (W/nf + 0.29)'"
nrd="'0.29 / W'" nrs="'0.29 / W'"
sa=0 sb=0 sd=0
model=nfet_01v8
spiceprefix=X
}
C {sky130_fd_pr/nfet_01v8.sym} 120 570 1 0 {name=M18
L=0.15
W=1
nf=1 
mult=1
ad="'int((nf+1)/2) * W/nf * 0.29'" 
pd="'2*int((nf+1)/2) * (W/nf + 0.29)'"
as="'int((nf+2)/2) * W/nf * 0.29'" 
ps="'2*int((nf+2)/2) * (W/nf + 0.29)'"
nrd="'0.29 / W'" nrs="'0.29 / W'"
sa=0 sb=0 sd=0
model=nfet_01v8
spiceprefix=X
}
C {sky130_fd_pr/nfet_01v8.sym} 200 570 1 0 {name=M19
L=0.15
W=1
nf=1 
mult=1
ad="'int((nf+1)/2) * W/nf * 0.29'" 
pd="'2*int((nf+1)/2) * (W/nf + 0.29)'"
as="'int((nf+2)/2) * W/nf * 0.29'" 
ps="'2*int((nf+2)/2) * (W/nf + 0.29)'"
nrd="'0.29 / W'" nrs="'0.29 / W'"
sa=0 sb=0 sd=0
model=nfet_01v8
spiceprefix=X
}
C {sky130_fd_pr/nfet_01v8.sym} 280 570 1 0 {name=M20
L=0.15
W=1
nf=1 
mult=1
ad="'int((nf+1)/2) * W/nf * 0.29'" 
pd="'2*int((nf+1)/2) * (W/nf + 0.29)'"
as="'int((nf+2)/2) * W/nf * 0.29'" 
ps="'2*int((nf+2)/2) * (W/nf + 0.29)'"
nrd="'0.29 / W'" nrs="'0.29 / W'"
sa=0 sb=0 sd=0
model=nfet_01v8
spiceprefix=X
}
C {sky130_fd_pr/nfet_01v8.sym} 360 570 1 0 {name=M21
L=0.15
W=1
nf=1 
mult=1
ad="'int((nf+1)/2) * W/nf * 0.29'" 
pd="'2*int((nf+1)/2) * (W/nf + 0.29)'"
as="'int((nf+2)/2) * W/nf * 0.29'" 
ps="'2*int((nf+2)/2) * (W/nf + 0.29)'"
nrd="'0.29 / W'" nrs="'0.29 / W'"
sa=0 sb=0 sd=0
model=nfet_01v8
spiceprefix=X
}
C {sky130_fd_pr/nfet_01v8.sym} 440 570 1 0 {name=M22
L=0.15
W=1
nf=1 
mult=1
ad="'int((nf+1)/2) * W/nf * 0.29'" 
pd="'2*int((nf+1)/2) * (W/nf + 0.29)'"
as="'int((nf+2)/2) * W/nf * 0.29'" 
ps="'2*int((nf+2)/2) * (W/nf + 0.29)'"
nrd="'0.29 / W'" nrs="'0.29 / W'"
sa=0 sb=0 sd=0
model=nfet_01v8
spiceprefix=X
}
C {sky130_fd_pr/nfet_01v8.sym} 520 570 1 0 {name=M23
L=0.15
W=1
nf=1 
mult=1
ad="'int((nf+1)/2) * W/nf * 0.29'" 
pd="'2*int((nf+1)/2) * (W/nf + 0.29)'"
as="'int((nf+2)/2) * W/nf * 0.29'" 
ps="'2*int((nf+2)/2) * (W/nf + 0.29)'"
nrd="'0.29 / W'" nrs="'0.29 / W'"
sa=0 sb=0 sd=0
model=nfet_01v8
spiceprefix=X
}
C {sky130_fd_pr/nfet_01v8.sym} 600 570 1 0 {name=M24
L=0.15
W=1
nf=1 
mult=1
ad="'int((nf+1)/2) * W/nf * 0.29'" 
pd="'2*int((nf+1)/2) * (W/nf + 0.29)'"
as="'int((nf+2)/2) * W/nf * 0.29'" 
ps="'2*int((nf+2)/2) * (W/nf + 0.29)'"
nrd="'0.29 / W'" nrs="'0.29 / W'"
sa=0 sb=0 sd=0
model=nfet_01v8
spiceprefix=X
}
C {devices/ipin.sym} 0 610 0 0 {name=p33 lab=word10}
C {sky130_fd_pr/nfet_01v8.sym} 40 630 1 0 {name=M25
L=0.15
W=1
nf=1 
mult=1
ad="'int((nf+1)/2) * W/nf * 0.29'" 
pd="'2*int((nf+1)/2) * (W/nf + 0.29)'"
as="'int((nf+2)/2) * W/nf * 0.29'" 
ps="'2*int((nf+2)/2) * (W/nf + 0.29)'"
nrd="'0.29 / W'" nrs="'0.29 / W'"
sa=0 sb=0 sd=0
model=nfet_01v8
spiceprefix=X
}
C {sky130_fd_pr/nfet_01v8.sym} 120 630 1 0 {name=M26
L=0.15
W=1
nf=1 
mult=1
ad="'int((nf+1)/2) * W/nf * 0.29'" 
pd="'2*int((nf+1)/2) * (W/nf + 0.29)'"
as="'int((nf+2)/2) * W/nf * 0.29'" 
ps="'2*int((nf+2)/2) * (W/nf + 0.29)'"
nrd="'0.29 / W'" nrs="'0.29 / W'"
sa=0 sb=0 sd=0
model=nfet_01v8
spiceprefix=X
}
C {sky130_fd_pr/nfet_01v8.sym} 200 630 1 0 {name=M27
L=0.15
W=1
nf=1 
mult=1
ad="'int((nf+1)/2) * W/nf * 0.29'" 
pd="'2*int((nf+1)/2) * (W/nf + 0.29)'"
as="'int((nf+2)/2) * W/nf * 0.29'" 
ps="'2*int((nf+2)/2) * (W/nf + 0.29)'"
nrd="'0.29 / W'" nrs="'0.29 / W'"
sa=0 sb=0 sd=0
model=nfet_01v8
spiceprefix=X
}
C {sky130_fd_pr/nfet_01v8.sym} 280 630 1 0 {name=M28
L=0.15
W=1
nf=1 
mult=1
ad="'int((nf+1)/2) * W/nf * 0.29'" 
pd="'2*int((nf+1)/2) * (W/nf + 0.29)'"
as="'int((nf+2)/2) * W/nf * 0.29'" 
ps="'2*int((nf+2)/2) * (W/nf + 0.29)'"
nrd="'0.29 / W'" nrs="'0.29 / W'"
sa=0 sb=0 sd=0
model=nfet_01v8
spiceprefix=X
}
C {sky130_fd_pr/nfet_01v8.sym} 360 630 1 0 {name=M29
L=0.15
W=1
nf=1 
mult=1
ad="'int((nf+1)/2) * W/nf * 0.29'" 
pd="'2*int((nf+1)/2) * (W/nf + 0.29)'"
as="'int((nf+2)/2) * W/nf * 0.29'" 
ps="'2*int((nf+2)/2) * (W/nf + 0.29)'"
nrd="'0.29 / W'" nrs="'0.29 / W'"
sa=0 sb=0 sd=0
model=nfet_01v8
spiceprefix=X
}
C {sky130_fd_pr/nfet_01v8.sym} 440 630 1 0 {name=M30
L=0.15
W=1
nf=1 
mult=1
ad="'int((nf+1)/2) * W/nf * 0.29'" 
pd="'2*int((nf+1)/2) * (W/nf + 0.29)'"
as="'int((nf+2)/2) * W/nf * 0.29'" 
ps="'2*int((nf+2)/2) * (W/nf + 0.29)'"
nrd="'0.29 / W'" nrs="'0.29 / W'"
sa=0 sb=0 sd=0
model=nfet_01v8
spiceprefix=X
}
C {sky130_fd_pr/nfet_01v8.sym} 520 630 1 0 {name=M31
L=0.15
W=1
nf=1 
mult=1
ad="'int((nf+1)/2) * W/nf * 0.29'" 
pd="'2*int((nf+1)/2) * (W/nf + 0.29)'"
as="'int((nf+2)/2) * W/nf * 0.29'" 
ps="'2*int((nf+2)/2) * (W/nf + 0.29)'"
nrd="'0.29 / W'" nrs="'0.29 / W'"
sa=0 sb=0 sd=0
model=nfet_01v8
spiceprefix=X
}
C {sky130_fd_pr/nfet_01v8.sym} 600 630 1 0 {name=M32
L=0.15
W=1
nf=1 
mult=1
ad="'int((nf+1)/2) * W/nf * 0.29'" 
pd="'2*int((nf+1)/2) * (W/nf + 0.29)'"
as="'int((nf+2)/2) * W/nf * 0.29'" 
ps="'2*int((nf+2)/2) * (W/nf + 0.29)'"
nrd="'0.29 / W'" nrs="'0.29 / W'"
sa=0 sb=0 sd=0
model=nfet_01v8
spiceprefix=X
}
C {devices/ipin.sym} 0 670 0 0 {name=p34 lab=word11}
C {sky130_fd_pr/nfet_01v8.sym} 40 690 1 0 {name=M33
L=0.15
W=1
nf=1 
mult=1
ad="'int((nf+1)/2) * W/nf * 0.29'" 
pd="'2*int((nf+1)/2) * (W/nf + 0.29)'"
as="'int((nf+2)/2) * W/nf * 0.29'" 
ps="'2*int((nf+2)/2) * (W/nf + 0.29)'"
nrd="'0.29 / W'" nrs="'0.29 / W'"
sa=0 sb=0 sd=0
model=nfet_01v8
spiceprefix=X
}
C {sky130_fd_pr/nfet_01v8.sym} 120 690 1 0 {name=M34
L=0.15
W=1
nf=1 
mult=1
ad="'int((nf+1)/2) * W/nf * 0.29'" 
pd="'2*int((nf+1)/2) * (W/nf + 0.29)'"
as="'int((nf+2)/2) * W/nf * 0.29'" 
ps="'2*int((nf+2)/2) * (W/nf + 0.29)'"
nrd="'0.29 / W'" nrs="'0.29 / W'"
sa=0 sb=0 sd=0
model=nfet_01v8
spiceprefix=X
}
C {sky130_fd_pr/nfet_01v8.sym} 200 690 1 0 {name=M35
L=0.15
W=1
nf=1 
mult=1
ad="'int((nf+1)/2) * W/nf * 0.29'" 
pd="'2*int((nf+1)/2) * (W/nf + 0.29)'"
as="'int((nf+2)/2) * W/nf * 0.29'" 
ps="'2*int((nf+2)/2) * (W/nf + 0.29)'"
nrd="'0.29 / W'" nrs="'0.29 / W'"
sa=0 sb=0 sd=0
model=nfet_01v8
spiceprefix=X
}
C {sky130_fd_pr/nfet_01v8.sym} 280 690 1 0 {name=M36
L=0.15
W=1
nf=1 
mult=1
ad="'int((nf+1)/2) * W/nf * 0.29'" 
pd="'2*int((nf+1)/2) * (W/nf + 0.29)'"
as="'int((nf+2)/2) * W/nf * 0.29'" 
ps="'2*int((nf+2)/2) * (W/nf + 0.29)'"
nrd="'0.29 / W'" nrs="'0.29 / W'"
sa=0 sb=0 sd=0
model=nfet_01v8
spiceprefix=X
}
C {sky130_fd_pr/nfet_01v8.sym} 360 690 1 0 {name=M37
L=0.15
W=1
nf=1 
mult=1
ad="'int((nf+1)/2) * W/nf * 0.29'" 
pd="'2*int((nf+1)/2) * (W/nf + 0.29)'"
as="'int((nf+2)/2) * W/nf * 0.29'" 
ps="'2*int((nf+2)/2) * (W/nf + 0.29)'"
nrd="'0.29 / W'" nrs="'0.29 / W'"
sa=0 sb=0 sd=0
model=nfet_01v8
spiceprefix=X
}
C {sky130_fd_pr/nfet_01v8.sym} 440 690 1 0 {name=M38
L=0.15
W=1
nf=1 
mult=1
ad="'int((nf+1)/2) * W/nf * 0.29'" 
pd="'2*int((nf+1)/2) * (W/nf + 0.29)'"
as="'int((nf+2)/2) * W/nf * 0.29'" 
ps="'2*int((nf+2)/2) * (W/nf + 0.29)'"
nrd="'0.29 / W'" nrs="'0.29 / W'"
sa=0 sb=0 sd=0
model=nfet_01v8
spiceprefix=X
}
C {sky130_fd_pr/nfet_01v8.sym} 520 690 1 0 {name=M39
L=0.15
W=1
nf=1 
mult=1
ad="'int((nf+1)/2) * W/nf * 0.29'" 
pd="'2*int((nf+1)/2) * (W/nf + 0.29)'"
as="'int((nf+2)/2) * W/nf * 0.29'" 
ps="'2*int((nf+2)/2) * (W/nf + 0.29)'"
nrd="'0.29 / W'" nrs="'0.29 / W'"
sa=0 sb=0 sd=0
model=nfet_01v8
spiceprefix=X
}
C {sky130_fd_pr/nfet_01v8.sym} 600 690 1 0 {name=M40
L=0.15
W=1
nf=1 
mult=1
ad="'int((nf+1)/2) * W/nf * 0.29'" 
pd="'2*int((nf+1)/2) * (W/nf + 0.29)'"
as="'int((nf+2)/2) * W/nf * 0.29'" 
ps="'2*int((nf+2)/2) * (W/nf + 0.29)'"
nrd="'0.29 / W'" nrs="'0.29 / W'"
sa=0 sb=0 sd=0
model=nfet_01v8
spiceprefix=X
}
C {devices/ipin.sym} 0 730 0 0 {name=p35 lab=word12}
C {sky130_fd_pr/nfet_01v8.sym} 40 750 1 0 {name=M41
L=0.15
W=1
nf=1 
mult=1
ad="'int((nf+1)/2) * W/nf * 0.29'" 
pd="'2*int((nf+1)/2) * (W/nf + 0.29)'"
as="'int((nf+2)/2) * W/nf * 0.29'" 
ps="'2*int((nf+2)/2) * (W/nf + 0.29)'"
nrd="'0.29 / W'" nrs="'0.29 / W'"
sa=0 sb=0 sd=0
model=nfet_01v8
spiceprefix=X
}
C {sky130_fd_pr/nfet_01v8.sym} 120 750 1 0 {name=M42
L=0.15
W=1
nf=1 
mult=1
ad="'int((nf+1)/2) * W/nf * 0.29'" 
pd="'2*int((nf+1)/2) * (W/nf + 0.29)'"
as="'int((nf+2)/2) * W/nf * 0.29'" 
ps="'2*int((nf+2)/2) * (W/nf + 0.29)'"
nrd="'0.29 / W'" nrs="'0.29 / W'"
sa=0 sb=0 sd=0
model=nfet_01v8
spiceprefix=X
}
C {sky130_fd_pr/nfet_01v8.sym} 200 750 1 0 {name=M43
L=0.15
W=1
nf=1 
mult=1
ad="'int((nf+1)/2) * W/nf * 0.29'" 
pd="'2*int((nf+1)/2) * (W/nf + 0.29)'"
as="'int((nf+2)/2) * W/nf * 0.29'" 
ps="'2*int((nf+2)/2) * (W/nf + 0.29)'"
nrd="'0.29 / W'" nrs="'0.29 / W'"
sa=0 sb=0 sd=0
model=nfet_01v8
spiceprefix=X
}
C {sky130_fd_pr/nfet_01v8.sym} 280 750 1 0 {name=M44
L=0.15
W=1
nf=1 
mult=1
ad="'int((nf+1)/2) * W/nf * 0.29'" 
pd="'2*int((nf+1)/2) * (W/nf + 0.29)'"
as="'int((nf+2)/2) * W/nf * 0.29'" 
ps="'2*int((nf+2)/2) * (W/nf + 0.29)'"
nrd="'0.29 / W'" nrs="'0.29 / W'"
sa=0 sb=0 sd=0
model=nfet_01v8
spiceprefix=X
}
C {sky130_fd_pr/nfet_01v8.sym} 360 750 1 0 {name=M45
L=0.15
W=1
nf=1 
mult=1
ad="'int((nf+1)/2) * W/nf * 0.29'" 
pd="'2*int((nf+1)/2) * (W/nf + 0.29)'"
as="'int((nf+2)/2) * W/nf * 0.29'" 
ps="'2*int((nf+2)/2) * (W/nf + 0.29)'"
nrd="'0.29 / W'" nrs="'0.29 / W'"
sa=0 sb=0 sd=0
model=nfet_01v8
spiceprefix=X
}
C {sky130_fd_pr/nfet_01v8.sym} 440 750 1 0 {name=M46
L=0.15
W=1
nf=1 
mult=1
ad="'int((nf+1)/2) * W/nf * 0.29'" 
pd="'2*int((nf+1)/2) * (W/nf + 0.29)'"
as="'int((nf+2)/2) * W/nf * 0.29'" 
ps="'2*int((nf+2)/2) * (W/nf + 0.29)'"
nrd="'0.29 / W'" nrs="'0.29 / W'"
sa=0 sb=0 sd=0
model=nfet_01v8
spiceprefix=X
}
C {sky130_fd_pr/nfet_01v8.sym} 520 750 1 0 {name=M47
L=0.15
W=1
nf=1 
mult=1
ad="'int((nf+1)/2) * W/nf * 0.29'" 
pd="'2*int((nf+1)/2) * (W/nf + 0.29)'"
as="'int((nf+2)/2) * W/nf * 0.29'" 
ps="'2*int((nf+2)/2) * (W/nf + 0.29)'"
nrd="'0.29 / W'" nrs="'0.29 / W'"
sa=0 sb=0 sd=0
model=nfet_01v8
spiceprefix=X
}
C {sky130_fd_pr/nfet_01v8.sym} 600 750 1 0 {name=M48
L=0.15
W=1
nf=1 
mult=1
ad="'int((nf+1)/2) * W/nf * 0.29'" 
pd="'2*int((nf+1)/2) * (W/nf + 0.29)'"
as="'int((nf+2)/2) * W/nf * 0.29'" 
ps="'2*int((nf+2)/2) * (W/nf + 0.29)'"
nrd="'0.29 / W'" nrs="'0.29 / W'"
sa=0 sb=0 sd=0
model=nfet_01v8
spiceprefix=X
}
C {devices/ipin.sym} 0 790 0 0 {name=p36 lab=word13}
C {sky130_fd_pr/nfet_01v8.sym} 40 810 1 0 {name=M49
L=0.15
W=1
nf=1 
mult=1
ad="'int((nf+1)/2) * W/nf * 0.29'" 
pd="'2*int((nf+1)/2) * (W/nf + 0.29)'"
as="'int((nf+2)/2) * W/nf * 0.29'" 
ps="'2*int((nf+2)/2) * (W/nf + 0.29)'"
nrd="'0.29 / W'" nrs="'0.29 / W'"
sa=0 sb=0 sd=0
model=nfet_01v8
spiceprefix=X
}
C {sky130_fd_pr/nfet_01v8.sym} 120 810 1 0 {name=M50
L=0.15
W=1
nf=1 
mult=1
ad="'int((nf+1)/2) * W/nf * 0.29'" 
pd="'2*int((nf+1)/2) * (W/nf + 0.29)'"
as="'int((nf+2)/2) * W/nf * 0.29'" 
ps="'2*int((nf+2)/2) * (W/nf + 0.29)'"
nrd="'0.29 / W'" nrs="'0.29 / W'"
sa=0 sb=0 sd=0
model=nfet_01v8
spiceprefix=X
}
C {sky130_fd_pr/nfet_01v8.sym} 200 810 1 0 {name=M51
L=0.15
W=1
nf=1 
mult=1
ad="'int((nf+1)/2) * W/nf * 0.29'" 
pd="'2*int((nf+1)/2) * (W/nf + 0.29)'"
as="'int((nf+2)/2) * W/nf * 0.29'" 
ps="'2*int((nf+2)/2) * (W/nf + 0.29)'"
nrd="'0.29 / W'" nrs="'0.29 / W'"
sa=0 sb=0 sd=0
model=nfet_01v8
spiceprefix=X
}
C {sky130_fd_pr/nfet_01v8.sym} 280 810 1 0 {name=M52
L=0.15
W=1
nf=1 
mult=1
ad="'int((nf+1)/2) * W/nf * 0.29'" 
pd="'2*int((nf+1)/2) * (W/nf + 0.29)'"
as="'int((nf+2)/2) * W/nf * 0.29'" 
ps="'2*int((nf+2)/2) * (W/nf + 0.29)'"
nrd="'0.29 / W'" nrs="'0.29 / W'"
sa=0 sb=0 sd=0
model=nfet_01v8
spiceprefix=X
}
C {sky130_fd_pr/nfet_01v8.sym} 360 810 1 0 {name=M53
L=0.15
W=1
nf=1 
mult=1
ad="'int((nf+1)/2) * W/nf * 0.29'" 
pd="'2*int((nf+1)/2) * (W/nf + 0.29)'"
as="'int((nf+2)/2) * W/nf * 0.29'" 
ps="'2*int((nf+2)/2) * (W/nf + 0.29)'"
nrd="'0.29 / W'" nrs="'0.29 / W'"
sa=0 sb=0 sd=0
model=nfet_01v8
spiceprefix=X
}
C {sky130_fd_pr/nfet_01v8.sym} 440 810 1 0 {name=M54
L=0.15
W=1
nf=1 
mult=1
ad="'int((nf+1)/2) * W/nf * 0.29'" 
pd="'2*int((nf+1)/2) * (W/nf + 0.29)'"
as="'int((nf+2)/2) * W/nf * 0.29'" 
ps="'2*int((nf+2)/2) * (W/nf + 0.29)'"
nrd="'0.29 / W'" nrs="'0.29 / W'"
sa=0 sb=0 sd=0
model=nfet_01v8
spiceprefix=X
}
C {sky130_fd_pr/nfet_01v8.sym} 520 810 1 0 {name=M55
L=0.15
W=1
nf=1 
mult=1
ad="'int((nf+1)/2) * W/nf * 0.29'" 
pd="'2*int((nf+1)/2) * (W/nf + 0.29)'"
as="'int((nf+2)/2) * W/nf * 0.29'" 
ps="'2*int((nf+2)/2) * (W/nf + 0.29)'"
nrd="'0.29 / W'" nrs="'0.29 / W'"
sa=0 sb=0 sd=0
model=nfet_01v8
spiceprefix=X
}
C {sky130_fd_pr/nfet_01v8.sym} 600 810 1 0 {name=M56
L=0.15
W=1
nf=1 
mult=1
ad="'int((nf+1)/2) * W/nf * 0.29'" 
pd="'2*int((nf+1)/2) * (W/nf + 0.29)'"
as="'int((nf+2)/2) * W/nf * 0.29'" 
ps="'2*int((nf+2)/2) * (W/nf + 0.29)'"
nrd="'0.29 / W'" nrs="'0.29 / W'"
sa=0 sb=0 sd=0
model=nfet_01v8
spiceprefix=X
}
C {devices/ipin.sym} 0 850 0 0 {name=p37 lab=word14}
C {sky130_fd_pr/nfet_01v8.sym} 40 870 1 0 {name=M57
L=0.15
W=1
nf=1 
mult=1
ad="'int((nf+1)/2) * W/nf * 0.29'" 
pd="'2*int((nf+1)/2) * (W/nf + 0.29)'"
as="'int((nf+2)/2) * W/nf * 0.29'" 
ps="'2*int((nf+2)/2) * (W/nf + 0.29)'"
nrd="'0.29 / W'" nrs="'0.29 / W'"
sa=0 sb=0 sd=0
model=nfet_01v8
spiceprefix=X
}
C {sky130_fd_pr/nfet_01v8.sym} 120 870 1 0 {name=M58
L=0.15
W=1
nf=1 
mult=1
ad="'int((nf+1)/2) * W/nf * 0.29'" 
pd="'2*int((nf+1)/2) * (W/nf + 0.29)'"
as="'int((nf+2)/2) * W/nf * 0.29'" 
ps="'2*int((nf+2)/2) * (W/nf + 0.29)'"
nrd="'0.29 / W'" nrs="'0.29 / W'"
sa=0 sb=0 sd=0
model=nfet_01v8
spiceprefix=X
}
C {sky130_fd_pr/nfet_01v8.sym} 200 870 1 0 {name=M59
L=0.15
W=1
nf=1 
mult=1
ad="'int((nf+1)/2) * W/nf * 0.29'" 
pd="'2*int((nf+1)/2) * (W/nf + 0.29)'"
as="'int((nf+2)/2) * W/nf * 0.29'" 
ps="'2*int((nf+2)/2) * (W/nf + 0.29)'"
nrd="'0.29 / W'" nrs="'0.29 / W'"
sa=0 sb=0 sd=0
model=nfet_01v8
spiceprefix=X
}
C {sky130_fd_pr/nfet_01v8.sym} 280 870 1 0 {name=M60
L=0.15
W=1
nf=1 
mult=1
ad="'int((nf+1)/2) * W/nf * 0.29'" 
pd="'2*int((nf+1)/2) * (W/nf + 0.29)'"
as="'int((nf+2)/2) * W/nf * 0.29'" 
ps="'2*int((nf+2)/2) * (W/nf + 0.29)'"
nrd="'0.29 / W'" nrs="'0.29 / W'"
sa=0 sb=0 sd=0
model=nfet_01v8
spiceprefix=X
}
C {sky130_fd_pr/nfet_01v8.sym} 360 870 1 0 {name=M61
L=0.15
W=1
nf=1 
mult=1
ad="'int((nf+1)/2) * W/nf * 0.29'" 
pd="'2*int((nf+1)/2) * (W/nf + 0.29)'"
as="'int((nf+2)/2) * W/nf * 0.29'" 
ps="'2*int((nf+2)/2) * (W/nf + 0.29)'"
nrd="'0.29 / W'" nrs="'0.29 / W'"
sa=0 sb=0 sd=0
model=nfet_01v8
spiceprefix=X
}
C {sky130_fd_pr/nfet_01v8.sym} 440 870 1 0 {name=M62
L=0.15
W=1
nf=1 
mult=1
ad="'int((nf+1)/2) * W/nf * 0.29'" 
pd="'2*int((nf+1)/2) * (W/nf + 0.29)'"
as="'int((nf+2)/2) * W/nf * 0.29'" 
ps="'2*int((nf+2)/2) * (W/nf + 0.29)'"
nrd="'0.29 / W'" nrs="'0.29 / W'"
sa=0 sb=0 sd=0
model=nfet_01v8
spiceprefix=X
}
C {sky130_fd_pr/nfet_01v8.sym} 520 870 1 0 {name=M63
L=0.15
W=1
nf=1 
mult=1
ad="'int((nf+1)/2) * W/nf * 0.29'" 
pd="'2*int((nf+1)/2) * (W/nf + 0.29)'"
as="'int((nf+2)/2) * W/nf * 0.29'" 
ps="'2*int((nf+2)/2) * (W/nf + 0.29)'"
nrd="'0.29 / W'" nrs="'0.29 / W'"
sa=0 sb=0 sd=0
model=nfet_01v8
spiceprefix=X
}
C {sky130_fd_pr/nfet_01v8.sym} 600 870 1 0 {name=M64
L=0.15
W=1
nf=1 
mult=1
ad="'int((nf+1)/2) * W/nf * 0.29'" 
pd="'2*int((nf+1)/2) * (W/nf + 0.29)'"
as="'int((nf+2)/2) * W/nf * 0.29'" 
ps="'2*int((nf+2)/2) * (W/nf + 0.29)'"
nrd="'0.29 / W'" nrs="'0.29 / W'"
sa=0 sb=0 sd=0
model=nfet_01v8
spiceprefix=X
}
C {devices/ipin.sym} 0 910 0 0 {name=p38 lab=word15}
C {sky130_fd_pr/nfet_01v8.sym} 40 930 1 0 {name=M65
L=0.15
W=1
nf=1 
mult=1
ad="'int((nf+1)/2) * W/nf * 0.29'" 
pd="'2*int((nf+1)/2) * (W/nf + 0.29)'"
as="'int((nf+2)/2) * W/nf * 0.29'" 
ps="'2*int((nf+2)/2) * (W/nf + 0.29)'"
nrd="'0.29 / W'" nrs="'0.29 / W'"
sa=0 sb=0 sd=0
model=nfet_01v8
spiceprefix=X
}
C {sky130_fd_pr/nfet_01v8.sym} 120 930 1 0 {name=M66
L=0.15
W=1
nf=1 
mult=1
ad="'int((nf+1)/2) * W/nf * 0.29'" 
pd="'2*int((nf+1)/2) * (W/nf + 0.29)'"
as="'int((nf+2)/2) * W/nf * 0.29'" 
ps="'2*int((nf+2)/2) * (W/nf + 0.29)'"
nrd="'0.29 / W'" nrs="'0.29 / W'"
sa=0 sb=0 sd=0
model=nfet_01v8
spiceprefix=X
}
C {sky130_fd_pr/nfet_01v8.sym} 200 930 1 0 {name=M67
L=0.15
W=1
nf=1 
mult=1
ad="'int((nf+1)/2) * W/nf * 0.29'" 
pd="'2*int((nf+1)/2) * (W/nf + 0.29)'"
as="'int((nf+2)/2) * W/nf * 0.29'" 
ps="'2*int((nf+2)/2) * (W/nf + 0.29)'"
nrd="'0.29 / W'" nrs="'0.29 / W'"
sa=0 sb=0 sd=0
model=nfet_01v8
spiceprefix=X
}
C {sky130_fd_pr/nfet_01v8.sym} 280 930 1 0 {name=M68
L=0.15
W=1
nf=1 
mult=1
ad="'int((nf+1)/2) * W/nf * 0.29'" 
pd="'2*int((nf+1)/2) * (W/nf + 0.29)'"
as="'int((nf+2)/2) * W/nf * 0.29'" 
ps="'2*int((nf+2)/2) * (W/nf + 0.29)'"
nrd="'0.29 / W'" nrs="'0.29 / W'"
sa=0 sb=0 sd=0
model=nfet_01v8
spiceprefix=X
}
C {sky130_fd_pr/nfet_01v8.sym} 360 930 1 0 {name=M69
L=0.15
W=1
nf=1 
mult=1
ad="'int((nf+1)/2) * W/nf * 0.29'" 
pd="'2*int((nf+1)/2) * (W/nf + 0.29)'"
as="'int((nf+2)/2) * W/nf * 0.29'" 
ps="'2*int((nf+2)/2) * (W/nf + 0.29)'"
nrd="'0.29 / W'" nrs="'0.29 / W'"
sa=0 sb=0 sd=0
model=nfet_01v8
spiceprefix=X
}
C {sky130_fd_pr/nfet_01v8.sym} 440 930 1 0 {name=M70
L=0.15
W=1
nf=1 
mult=1
ad="'int((nf+1)/2) * W/nf * 0.29'" 
pd="'2*int((nf+1)/2) * (W/nf + 0.29)'"
as="'int((nf+2)/2) * W/nf * 0.29'" 
ps="'2*int((nf+2)/2) * (W/nf + 0.29)'"
nrd="'0.29 / W'" nrs="'0.29 / W'"
sa=0 sb=0 sd=0
model=nfet_01v8
spiceprefix=X
}
C {sky130_fd_pr/nfet_01v8.sym} 520 930 1 0 {name=M71
L=0.15
W=1
nf=1 
mult=1
ad="'int((nf+1)/2) * W/nf * 0.29'" 
pd="'2*int((nf+1)/2) * (W/nf + 0.29)'"
as="'int((nf+2)/2) * W/nf * 0.29'" 
ps="'2*int((nf+2)/2) * (W/nf + 0.29)'"
nrd="'0.29 / W'" nrs="'0.29 / W'"
sa=0 sb=0 sd=0
model=nfet_01v8
spiceprefix=X
}
C {sky130_fd_pr/nfet_01v8.sym} 600 930 1 0 {name=M72
L=0.15
W=1
nf=1 
mult=1
ad="'int((nf+1)/2) * W/nf * 0.29'" 
pd="'2*int((nf+1)/2) * (W/nf + 0.29)'"
as="'int((nf+2)/2) * W/nf * 0.29'" 
ps="'2*int((nf+2)/2) * (W/nf + 0.29)'"
nrd="'0.29 / W'" nrs="'0.29 / W'"
sa=0 sb=0 sd=0
model=nfet_01v8
spiceprefix=X
}
C {devices/ipin.sym} 0 970 0 0 {name=p39 lab=word16}
C {devices/ipin.sym} 0 1030 0 0 {name=p40 lab=word17}
C {sky130_fd_pr/nfet_01v8.sym} 280 1050 1 0 {name=M73
L=0.15
W=1
nf=1 
mult=1
ad="'int((nf+1)/2) * W/nf * 0.29'" 
pd="'2*int((nf+1)/2) * (W/nf + 0.29)'"
as="'int((nf+2)/2) * W/nf * 0.29'" 
ps="'2*int((nf+2)/2) * (W/nf + 0.29)'"
nrd="'0.29 / W'" nrs="'0.29 / W'"
sa=0 sb=0 sd=0
model=nfet_01v8
spiceprefix=X
}
C {sky130_fd_pr/nfet_01v8.sym} 360 1050 1 0 {name=M74
L=0.15
W=1
nf=1 
mult=1
ad="'int((nf+1)/2) * W/nf * 0.29'" 
pd="'2*int((nf+1)/2) * (W/nf + 0.29)'"
as="'int((nf+2)/2) * W/nf * 0.29'" 
ps="'2*int((nf+2)/2) * (W/nf + 0.29)'"
nrd="'0.29 / W'" nrs="'0.29 / W'"
sa=0 sb=0 sd=0
model=nfet_01v8
spiceprefix=X
}
C {sky130_fd_pr/nfet_01v8.sym} 440 1050 1 0 {name=M75
L=0.15
W=1
nf=1 
mult=1
ad="'int((nf+1)/2) * W/nf * 0.29'" 
pd="'2*int((nf+1)/2) * (W/nf + 0.29)'"
as="'int((nf+2)/2) * W/nf * 0.29'" 
ps="'2*int((nf+2)/2) * (W/nf + 0.29)'"
nrd="'0.29 / W'" nrs="'0.29 / W'"
sa=0 sb=0 sd=0
model=nfet_01v8
spiceprefix=X
}
C {sky130_fd_pr/nfet_01v8.sym} 520 1050 1 0 {name=M76
L=0.15
W=1
nf=1 
mult=1
ad="'int((nf+1)/2) * W/nf * 0.29'" 
pd="'2*int((nf+1)/2) * (W/nf + 0.29)'"
as="'int((nf+2)/2) * W/nf * 0.29'" 
ps="'2*int((nf+2)/2) * (W/nf + 0.29)'"
nrd="'0.29 / W'" nrs="'0.29 / W'"
sa=0 sb=0 sd=0
model=nfet_01v8
spiceprefix=X
}
C {sky130_fd_pr/nfet_01v8.sym} 600 1050 1 0 {name=M77
L=0.15
W=1
nf=1 
mult=1
ad="'int((nf+1)/2) * W/nf * 0.29'" 
pd="'2*int((nf+1)/2) * (W/nf + 0.29)'"
as="'int((nf+2)/2) * W/nf * 0.29'" 
ps="'2*int((nf+2)/2) * (W/nf + 0.29)'"
nrd="'0.29 / W'" nrs="'0.29 / W'"
sa=0 sb=0 sd=0
model=nfet_01v8
spiceprefix=X
}
C {devices/ipin.sym} 0 1090 0 0 {name=p41 lab=word18}
C {sky130_fd_pr/nfet_01v8.sym} 200 1110 1 0 {name=M78
L=0.15
W=1
nf=1 
mult=1
ad="'int((nf+1)/2) * W/nf * 0.29'" 
pd="'2*int((nf+1)/2) * (W/nf + 0.29)'"
as="'int((nf+2)/2) * W/nf * 0.29'" 
ps="'2*int((nf+2)/2) * (W/nf + 0.29)'"
nrd="'0.29 / W'" nrs="'0.29 / W'"
sa=0 sb=0 sd=0
model=nfet_01v8
spiceprefix=X
}
C {sky130_fd_pr/nfet_01v8.sym} 280 1110 1 0 {name=M79
L=0.15
W=1
nf=1 
mult=1
ad="'int((nf+1)/2) * W/nf * 0.29'" 
pd="'2*int((nf+1)/2) * (W/nf + 0.29)'"
as="'int((nf+2)/2) * W/nf * 0.29'" 
ps="'2*int((nf+2)/2) * (W/nf + 0.29)'"
nrd="'0.29 / W'" nrs="'0.29 / W'"
sa=0 sb=0 sd=0
model=nfet_01v8
spiceprefix=X
}
C {sky130_fd_pr/nfet_01v8.sym} 360 1110 1 0 {name=M80
L=0.15
W=1
nf=1 
mult=1
ad="'int((nf+1)/2) * W/nf * 0.29'" 
pd="'2*int((nf+1)/2) * (W/nf + 0.29)'"
as="'int((nf+2)/2) * W/nf * 0.29'" 
ps="'2*int((nf+2)/2) * (W/nf + 0.29)'"
nrd="'0.29 / W'" nrs="'0.29 / W'"
sa=0 sb=0 sd=0
model=nfet_01v8
spiceprefix=X
}
C {sky130_fd_pr/nfet_01v8.sym} 440 1110 1 0 {name=M81
L=0.15
W=1
nf=1 
mult=1
ad="'int((nf+1)/2) * W/nf * 0.29'" 
pd="'2*int((nf+1)/2) * (W/nf + 0.29)'"
as="'int((nf+2)/2) * W/nf * 0.29'" 
ps="'2*int((nf+2)/2) * (W/nf + 0.29)'"
nrd="'0.29 / W'" nrs="'0.29 / W'"
sa=0 sb=0 sd=0
model=nfet_01v8
spiceprefix=X
}
C {sky130_fd_pr/nfet_01v8.sym} 520 1110 1 0 {name=M82
L=0.15
W=1
nf=1 
mult=1
ad="'int((nf+1)/2) * W/nf * 0.29'" 
pd="'2*int((nf+1)/2) * (W/nf + 0.29)'"
as="'int((nf+2)/2) * W/nf * 0.29'" 
ps="'2*int((nf+2)/2) * (W/nf + 0.29)'"
nrd="'0.29 / W'" nrs="'0.29 / W'"
sa=0 sb=0 sd=0
model=nfet_01v8
spiceprefix=X
}
C {sky130_fd_pr/nfet_01v8.sym} 600 1110 1 0 {name=M83
L=0.15
W=1
nf=1 
mult=1
ad="'int((nf+1)/2) * W/nf * 0.29'" 
pd="'2*int((nf+1)/2) * (W/nf + 0.29)'"
as="'int((nf+2)/2) * W/nf * 0.29'" 
ps="'2*int((nf+2)/2) * (W/nf + 0.29)'"
nrd="'0.29 / W'" nrs="'0.29 / W'"
sa=0 sb=0 sd=0
model=nfet_01v8
spiceprefix=X
}
C {devices/ipin.sym} 0 1150 0 0 {name=p42 lab=word19}
C {sky130_fd_pr/nfet_01v8.sym} 120 1170 1 0 {name=M84
L=0.15
W=1
nf=1 
mult=1
ad="'int((nf+1)/2) * W/nf * 0.29'" 
pd="'2*int((nf+1)/2) * (W/nf + 0.29)'"
as="'int((nf+2)/2) * W/nf * 0.29'" 
ps="'2*int((nf+2)/2) * (W/nf + 0.29)'"
nrd="'0.29 / W'" nrs="'0.29 / W'"
sa=0 sb=0 sd=0
model=nfet_01v8
spiceprefix=X
}
C {sky130_fd_pr/nfet_01v8.sym} 280 1170 1 0 {name=M85
L=0.15
W=1
nf=1 
mult=1
ad="'int((nf+1)/2) * W/nf * 0.29'" 
pd="'2*int((nf+1)/2) * (W/nf + 0.29)'"
as="'int((nf+2)/2) * W/nf * 0.29'" 
ps="'2*int((nf+2)/2) * (W/nf + 0.29)'"
nrd="'0.29 / W'" nrs="'0.29 / W'"
sa=0 sb=0 sd=0
model=nfet_01v8
spiceprefix=X
}
C {sky130_fd_pr/nfet_01v8.sym} 360 1170 1 0 {name=M86
L=0.15
W=1
nf=1 
mult=1
ad="'int((nf+1)/2) * W/nf * 0.29'" 
pd="'2*int((nf+1)/2) * (W/nf + 0.29)'"
as="'int((nf+2)/2) * W/nf * 0.29'" 
ps="'2*int((nf+2)/2) * (W/nf + 0.29)'"
nrd="'0.29 / W'" nrs="'0.29 / W'"
sa=0 sb=0 sd=0
model=nfet_01v8
spiceprefix=X
}
C {sky130_fd_pr/nfet_01v8.sym} 440 1170 1 0 {name=M87
L=0.15
W=1
nf=1 
mult=1
ad="'int((nf+1)/2) * W/nf * 0.29'" 
pd="'2*int((nf+1)/2) * (W/nf + 0.29)'"
as="'int((nf+2)/2) * W/nf * 0.29'" 
ps="'2*int((nf+2)/2) * (W/nf + 0.29)'"
nrd="'0.29 / W'" nrs="'0.29 / W'"
sa=0 sb=0 sd=0
model=nfet_01v8
spiceprefix=X
}
C {sky130_fd_pr/nfet_01v8.sym} 520 1170 1 0 {name=M88
L=0.15
W=1
nf=1 
mult=1
ad="'int((nf+1)/2) * W/nf * 0.29'" 
pd="'2*int((nf+1)/2) * (W/nf + 0.29)'"
as="'int((nf+2)/2) * W/nf * 0.29'" 
ps="'2*int((nf+2)/2) * (W/nf + 0.29)'"
nrd="'0.29 / W'" nrs="'0.29 / W'"
sa=0 sb=0 sd=0
model=nfet_01v8
spiceprefix=X
}
C {sky130_fd_pr/nfet_01v8.sym} 600 1170 1 0 {name=M89
L=0.15
W=1
nf=1 
mult=1
ad="'int((nf+1)/2) * W/nf * 0.29'" 
pd="'2*int((nf+1)/2) * (W/nf + 0.29)'"
as="'int((nf+2)/2) * W/nf * 0.29'" 
ps="'2*int((nf+2)/2) * (W/nf + 0.29)'"
nrd="'0.29 / W'" nrs="'0.29 / W'"
sa=0 sb=0 sd=0
model=nfet_01v8
spiceprefix=X
}
C {devices/ipin.sym} 0 1210 0 0 {name=p43 lab=word20}
C {sky130_fd_pr/nfet_01v8.sym} 120 1230 1 0 {name=M90
L=0.15
W=1
nf=1 
mult=1
ad="'int((nf+1)/2) * W/nf * 0.29'" 
pd="'2*int((nf+1)/2) * (W/nf + 0.29)'"
as="'int((nf+2)/2) * W/nf * 0.29'" 
ps="'2*int((nf+2)/2) * (W/nf + 0.29)'"
nrd="'0.29 / W'" nrs="'0.29 / W'"
sa=0 sb=0 sd=0
model=nfet_01v8
spiceprefix=X
}
C {sky130_fd_pr/nfet_01v8.sym} 200 1230 1 0 {name=M91
L=0.15
W=1
nf=1 
mult=1
ad="'int((nf+1)/2) * W/nf * 0.29'" 
pd="'2*int((nf+1)/2) * (W/nf + 0.29)'"
as="'int((nf+2)/2) * W/nf * 0.29'" 
ps="'2*int((nf+2)/2) * (W/nf + 0.29)'"
nrd="'0.29 / W'" nrs="'0.29 / W'"
sa=0 sb=0 sd=0
model=nfet_01v8
spiceprefix=X
}
C {sky130_fd_pr/nfet_01v8.sym} 280 1230 1 0 {name=M92
L=0.15
W=1
nf=1 
mult=1
ad="'int((nf+1)/2) * W/nf * 0.29'" 
pd="'2*int((nf+1)/2) * (W/nf + 0.29)'"
as="'int((nf+2)/2) * W/nf * 0.29'" 
ps="'2*int((nf+2)/2) * (W/nf + 0.29)'"
nrd="'0.29 / W'" nrs="'0.29 / W'"
sa=0 sb=0 sd=0
model=nfet_01v8
spiceprefix=X
}
C {sky130_fd_pr/nfet_01v8.sym} 360 1230 1 0 {name=M93
L=0.15
W=1
nf=1 
mult=1
ad="'int((nf+1)/2) * W/nf * 0.29'" 
pd="'2*int((nf+1)/2) * (W/nf + 0.29)'"
as="'int((nf+2)/2) * W/nf * 0.29'" 
ps="'2*int((nf+2)/2) * (W/nf + 0.29)'"
nrd="'0.29 / W'" nrs="'0.29 / W'"
sa=0 sb=0 sd=0
model=nfet_01v8
spiceprefix=X
}
C {sky130_fd_pr/nfet_01v8.sym} 440 1230 1 0 {name=M94
L=0.15
W=1
nf=1 
mult=1
ad="'int((nf+1)/2) * W/nf * 0.29'" 
pd="'2*int((nf+1)/2) * (W/nf + 0.29)'"
as="'int((nf+2)/2) * W/nf * 0.29'" 
ps="'2*int((nf+2)/2) * (W/nf + 0.29)'"
nrd="'0.29 / W'" nrs="'0.29 / W'"
sa=0 sb=0 sd=0
model=nfet_01v8
spiceprefix=X
}
C {sky130_fd_pr/nfet_01v8.sym} 520 1230 1 0 {name=M95
L=0.15
W=1
nf=1 
mult=1
ad="'int((nf+1)/2) * W/nf * 0.29'" 
pd="'2*int((nf+1)/2) * (W/nf + 0.29)'"
as="'int((nf+2)/2) * W/nf * 0.29'" 
ps="'2*int((nf+2)/2) * (W/nf + 0.29)'"
nrd="'0.29 / W'" nrs="'0.29 / W'"
sa=0 sb=0 sd=0
model=nfet_01v8
spiceprefix=X
}
C {sky130_fd_pr/nfet_01v8.sym} 600 1230 1 0 {name=M96
L=0.15
W=1
nf=1 
mult=1
ad="'int((nf+1)/2) * W/nf * 0.29'" 
pd="'2*int((nf+1)/2) * (W/nf + 0.29)'"
as="'int((nf+2)/2) * W/nf * 0.29'" 
ps="'2*int((nf+2)/2) * (W/nf + 0.29)'"
nrd="'0.29 / W'" nrs="'0.29 / W'"
sa=0 sb=0 sd=0
model=nfet_01v8
spiceprefix=X
}
C {devices/ipin.sym} 0 1270 0 0 {name=p44 lab=word21}
C {sky130_fd_pr/nfet_01v8.sym} 40 1290 1 0 {name=M97
L=0.15
W=1
nf=1 
mult=1
ad="'int((nf+1)/2) * W/nf * 0.29'" 
pd="'2*int((nf+1)/2) * (W/nf + 0.29)'"
as="'int((nf+2)/2) * W/nf * 0.29'" 
ps="'2*int((nf+2)/2) * (W/nf + 0.29)'"
nrd="'0.29 / W'" nrs="'0.29 / W'"
sa=0 sb=0 sd=0
model=nfet_01v8
spiceprefix=X
}
C {sky130_fd_pr/nfet_01v8.sym} 280 1290 1 0 {name=M98
L=0.15
W=1
nf=1 
mult=1
ad="'int((nf+1)/2) * W/nf * 0.29'" 
pd="'2*int((nf+1)/2) * (W/nf + 0.29)'"
as="'int((nf+2)/2) * W/nf * 0.29'" 
ps="'2*int((nf+2)/2) * (W/nf + 0.29)'"
nrd="'0.29 / W'" nrs="'0.29 / W'"
sa=0 sb=0 sd=0
model=nfet_01v8
spiceprefix=X
}
C {sky130_fd_pr/nfet_01v8.sym} 360 1290 1 0 {name=M99
L=0.15
W=1
nf=1 
mult=1
ad="'int((nf+1)/2) * W/nf * 0.29'" 
pd="'2*int((nf+1)/2) * (W/nf + 0.29)'"
as="'int((nf+2)/2) * W/nf * 0.29'" 
ps="'2*int((nf+2)/2) * (W/nf + 0.29)'"
nrd="'0.29 / W'" nrs="'0.29 / W'"
sa=0 sb=0 sd=0
model=nfet_01v8
spiceprefix=X
}
C {sky130_fd_pr/nfet_01v8.sym} 440 1290 1 0 {name=M100
L=0.15
W=1
nf=1 
mult=1
ad="'int((nf+1)/2) * W/nf * 0.29'" 
pd="'2*int((nf+1)/2) * (W/nf + 0.29)'"
as="'int((nf+2)/2) * W/nf * 0.29'" 
ps="'2*int((nf+2)/2) * (W/nf + 0.29)'"
nrd="'0.29 / W'" nrs="'0.29 / W'"
sa=0 sb=0 sd=0
model=nfet_01v8
spiceprefix=X
}
C {sky130_fd_pr/nfet_01v8.sym} 520 1290 1 0 {name=M101
L=0.15
W=1
nf=1 
mult=1
ad="'int((nf+1)/2) * W/nf * 0.29'" 
pd="'2*int((nf+1)/2) * (W/nf + 0.29)'"
as="'int((nf+2)/2) * W/nf * 0.29'" 
ps="'2*int((nf+2)/2) * (W/nf + 0.29)'"
nrd="'0.29 / W'" nrs="'0.29 / W'"
sa=0 sb=0 sd=0
model=nfet_01v8
spiceprefix=X
}
C {sky130_fd_pr/nfet_01v8.sym} 600 1290 1 0 {name=M102
L=0.15
W=1
nf=1 
mult=1
ad="'int((nf+1)/2) * W/nf * 0.29'" 
pd="'2*int((nf+1)/2) * (W/nf + 0.29)'"
as="'int((nf+2)/2) * W/nf * 0.29'" 
ps="'2*int((nf+2)/2) * (W/nf + 0.29)'"
nrd="'0.29 / W'" nrs="'0.29 / W'"
sa=0 sb=0 sd=0
model=nfet_01v8
spiceprefix=X
}
C {devices/ipin.sym} 0 1330 0 0 {name=p45 lab=word22}
C {sky130_fd_pr/nfet_01v8.sym} 40 1350 1 0 {name=M103
L=0.15
W=1
nf=1 
mult=1
ad="'int((nf+1)/2) * W/nf * 0.29'" 
pd="'2*int((nf+1)/2) * (W/nf + 0.29)'"
as="'int((nf+2)/2) * W/nf * 0.29'" 
ps="'2*int((nf+2)/2) * (W/nf + 0.29)'"
nrd="'0.29 / W'" nrs="'0.29 / W'"
sa=0 sb=0 sd=0
model=nfet_01v8
spiceprefix=X
}
C {sky130_fd_pr/nfet_01v8.sym} 200 1350 1 0 {name=M104
L=0.15
W=1
nf=1 
mult=1
ad="'int((nf+1)/2) * W/nf * 0.29'" 
pd="'2*int((nf+1)/2) * (W/nf + 0.29)'"
as="'int((nf+2)/2) * W/nf * 0.29'" 
ps="'2*int((nf+2)/2) * (W/nf + 0.29)'"
nrd="'0.29 / W'" nrs="'0.29 / W'"
sa=0 sb=0 sd=0
model=nfet_01v8
spiceprefix=X
}
C {sky130_fd_pr/nfet_01v8.sym} 280 1350 1 0 {name=M105
L=0.15
W=1
nf=1 
mult=1
ad="'int((nf+1)/2) * W/nf * 0.29'" 
pd="'2*int((nf+1)/2) * (W/nf + 0.29)'"
as="'int((nf+2)/2) * W/nf * 0.29'" 
ps="'2*int((nf+2)/2) * (W/nf + 0.29)'"
nrd="'0.29 / W'" nrs="'0.29 / W'"
sa=0 sb=0 sd=0
model=nfet_01v8
spiceprefix=X
}
C {sky130_fd_pr/nfet_01v8.sym} 360 1350 1 0 {name=M106
L=0.15
W=1
nf=1 
mult=1
ad="'int((nf+1)/2) * W/nf * 0.29'" 
pd="'2*int((nf+1)/2) * (W/nf + 0.29)'"
as="'int((nf+2)/2) * W/nf * 0.29'" 
ps="'2*int((nf+2)/2) * (W/nf + 0.29)'"
nrd="'0.29 / W'" nrs="'0.29 / W'"
sa=0 sb=0 sd=0
model=nfet_01v8
spiceprefix=X
}
C {sky130_fd_pr/nfet_01v8.sym} 440 1350 1 0 {name=M107
L=0.15
W=1
nf=1 
mult=1
ad="'int((nf+1)/2) * W/nf * 0.29'" 
pd="'2*int((nf+1)/2) * (W/nf + 0.29)'"
as="'int((nf+2)/2) * W/nf * 0.29'" 
ps="'2*int((nf+2)/2) * (W/nf + 0.29)'"
nrd="'0.29 / W'" nrs="'0.29 / W'"
sa=0 sb=0 sd=0
model=nfet_01v8
spiceprefix=X
}
C {sky130_fd_pr/nfet_01v8.sym} 520 1350 1 0 {name=M108
L=0.15
W=1
nf=1 
mult=1
ad="'int((nf+1)/2) * W/nf * 0.29'" 
pd="'2*int((nf+1)/2) * (W/nf + 0.29)'"
as="'int((nf+2)/2) * W/nf * 0.29'" 
ps="'2*int((nf+2)/2) * (W/nf + 0.29)'"
nrd="'0.29 / W'" nrs="'0.29 / W'"
sa=0 sb=0 sd=0
model=nfet_01v8
spiceprefix=X
}
C {sky130_fd_pr/nfet_01v8.sym} 600 1350 1 0 {name=M109
L=0.15
W=1
nf=1 
mult=1
ad="'int((nf+1)/2) * W/nf * 0.29'" 
pd="'2*int((nf+1)/2) * (W/nf + 0.29)'"
as="'int((nf+2)/2) * W/nf * 0.29'" 
ps="'2*int((nf+2)/2) * (W/nf + 0.29)'"
nrd="'0.29 / W'" nrs="'0.29 / W'"
sa=0 sb=0 sd=0
model=nfet_01v8
spiceprefix=X
}
C {devices/ipin.sym} 0 1390 0 0 {name=p46 lab=word23}
C {sky130_fd_pr/nfet_01v8.sym} 40 1410 1 0 {name=M110
L=0.15
W=1
nf=1 
mult=1
ad="'int((nf+1)/2) * W/nf * 0.29'" 
pd="'2*int((nf+1)/2) * (W/nf + 0.29)'"
as="'int((nf+2)/2) * W/nf * 0.29'" 
ps="'2*int((nf+2)/2) * (W/nf + 0.29)'"
nrd="'0.29 / W'" nrs="'0.29 / W'"
sa=0 sb=0 sd=0
model=nfet_01v8
spiceprefix=X
}
C {sky130_fd_pr/nfet_01v8.sym} 120 1410 1 0 {name=M111
L=0.15
W=1
nf=1 
mult=1
ad="'int((nf+1)/2) * W/nf * 0.29'" 
pd="'2*int((nf+1)/2) * (W/nf + 0.29)'"
as="'int((nf+2)/2) * W/nf * 0.29'" 
ps="'2*int((nf+2)/2) * (W/nf + 0.29)'"
nrd="'0.29 / W'" nrs="'0.29 / W'"
sa=0 sb=0 sd=0
model=nfet_01v8
spiceprefix=X
}
C {sky130_fd_pr/nfet_01v8.sym} 280 1410 1 0 {name=M112
L=0.15
W=1
nf=1 
mult=1
ad="'int((nf+1)/2) * W/nf * 0.29'" 
pd="'2*int((nf+1)/2) * (W/nf + 0.29)'"
as="'int((nf+2)/2) * W/nf * 0.29'" 
ps="'2*int((nf+2)/2) * (W/nf + 0.29)'"
nrd="'0.29 / W'" nrs="'0.29 / W'"
sa=0 sb=0 sd=0
model=nfet_01v8
spiceprefix=X
}
C {sky130_fd_pr/nfet_01v8.sym} 360 1410 1 0 {name=M113
L=0.15
W=1
nf=1 
mult=1
ad="'int((nf+1)/2) * W/nf * 0.29'" 
pd="'2*int((nf+1)/2) * (W/nf + 0.29)'"
as="'int((nf+2)/2) * W/nf * 0.29'" 
ps="'2*int((nf+2)/2) * (W/nf + 0.29)'"
nrd="'0.29 / W'" nrs="'0.29 / W'"
sa=0 sb=0 sd=0
model=nfet_01v8
spiceprefix=X
}
C {sky130_fd_pr/nfet_01v8.sym} 440 1410 1 0 {name=M114
L=0.15
W=1
nf=1 
mult=1
ad="'int((nf+1)/2) * W/nf * 0.29'" 
pd="'2*int((nf+1)/2) * (W/nf + 0.29)'"
as="'int((nf+2)/2) * W/nf * 0.29'" 
ps="'2*int((nf+2)/2) * (W/nf + 0.29)'"
nrd="'0.29 / W'" nrs="'0.29 / W'"
sa=0 sb=0 sd=0
model=nfet_01v8
spiceprefix=X
}
C {sky130_fd_pr/nfet_01v8.sym} 520 1410 1 0 {name=M115
L=0.15
W=1
nf=1 
mult=1
ad="'int((nf+1)/2) * W/nf * 0.29'" 
pd="'2*int((nf+1)/2) * (W/nf + 0.29)'"
as="'int((nf+2)/2) * W/nf * 0.29'" 
ps="'2*int((nf+2)/2) * (W/nf + 0.29)'"
nrd="'0.29 / W'" nrs="'0.29 / W'"
sa=0 sb=0 sd=0
model=nfet_01v8
spiceprefix=X
}
C {sky130_fd_pr/nfet_01v8.sym} 600 1410 1 0 {name=M116
L=0.15
W=1
nf=1 
mult=1
ad="'int((nf+1)/2) * W/nf * 0.29'" 
pd="'2*int((nf+1)/2) * (W/nf + 0.29)'"
as="'int((nf+2)/2) * W/nf * 0.29'" 
ps="'2*int((nf+2)/2) * (W/nf + 0.29)'"
nrd="'0.29 / W'" nrs="'0.29 / W'"
sa=0 sb=0 sd=0
model=nfet_01v8
spiceprefix=X
}
C {devices/ipin.sym} 0 1450 0 0 {name=p47 lab=word24}
C {sky130_fd_pr/nfet_01v8.sym} 40 1470 1 0 {name=M117
L=0.15
W=1
nf=1 
mult=1
ad="'int((nf+1)/2) * W/nf * 0.29'" 
pd="'2*int((nf+1)/2) * (W/nf + 0.29)'"
as="'int((nf+2)/2) * W/nf * 0.29'" 
ps="'2*int((nf+2)/2) * (W/nf + 0.29)'"
nrd="'0.29 / W'" nrs="'0.29 / W'"
sa=0 sb=0 sd=0
model=nfet_01v8
spiceprefix=X
}
C {sky130_fd_pr/nfet_01v8.sym} 120 1470 1 0 {name=M118
L=0.15
W=1
nf=1 
mult=1
ad="'int((nf+1)/2) * W/nf * 0.29'" 
pd="'2*int((nf+1)/2) * (W/nf + 0.29)'"
as="'int((nf+2)/2) * W/nf * 0.29'" 
ps="'2*int((nf+2)/2) * (W/nf + 0.29)'"
nrd="'0.29 / W'" nrs="'0.29 / W'"
sa=0 sb=0 sd=0
model=nfet_01v8
spiceprefix=X
}
C {sky130_fd_pr/nfet_01v8.sym} 200 1470 1 0 {name=M119
L=0.15
W=1
nf=1 
mult=1
ad="'int((nf+1)/2) * W/nf * 0.29'" 
pd="'2*int((nf+1)/2) * (W/nf + 0.29)'"
as="'int((nf+2)/2) * W/nf * 0.29'" 
ps="'2*int((nf+2)/2) * (W/nf + 0.29)'"
nrd="'0.29 / W'" nrs="'0.29 / W'"
sa=0 sb=0 sd=0
model=nfet_01v8
spiceprefix=X
}
C {sky130_fd_pr/nfet_01v8.sym} 280 1470 1 0 {name=M120
L=0.15
W=1
nf=1 
mult=1
ad="'int((nf+1)/2) * W/nf * 0.29'" 
pd="'2*int((nf+1)/2) * (W/nf + 0.29)'"
as="'int((nf+2)/2) * W/nf * 0.29'" 
ps="'2*int((nf+2)/2) * (W/nf + 0.29)'"
nrd="'0.29 / W'" nrs="'0.29 / W'"
sa=0 sb=0 sd=0
model=nfet_01v8
spiceprefix=X
}
C {sky130_fd_pr/nfet_01v8.sym} 360 1470 1 0 {name=M121
L=0.15
W=1
nf=1 
mult=1
ad="'int((nf+1)/2) * W/nf * 0.29'" 
pd="'2*int((nf+1)/2) * (W/nf + 0.29)'"
as="'int((nf+2)/2) * W/nf * 0.29'" 
ps="'2*int((nf+2)/2) * (W/nf + 0.29)'"
nrd="'0.29 / W'" nrs="'0.29 / W'"
sa=0 sb=0 sd=0
model=nfet_01v8
spiceprefix=X
}
C {sky130_fd_pr/nfet_01v8.sym} 440 1470 1 0 {name=M122
L=0.15
W=1
nf=1 
mult=1
ad="'int((nf+1)/2) * W/nf * 0.29'" 
pd="'2*int((nf+1)/2) * (W/nf + 0.29)'"
as="'int((nf+2)/2) * W/nf * 0.29'" 
ps="'2*int((nf+2)/2) * (W/nf + 0.29)'"
nrd="'0.29 / W'" nrs="'0.29 / W'"
sa=0 sb=0 sd=0
model=nfet_01v8
spiceprefix=X
}
C {sky130_fd_pr/nfet_01v8.sym} 520 1470 1 0 {name=M123
L=0.15
W=1
nf=1 
mult=1
ad="'int((nf+1)/2) * W/nf * 0.29'" 
pd="'2*int((nf+1)/2) * (W/nf + 0.29)'"
as="'int((nf+2)/2) * W/nf * 0.29'" 
ps="'2*int((nf+2)/2) * (W/nf + 0.29)'"
nrd="'0.29 / W'" nrs="'0.29 / W'"
sa=0 sb=0 sd=0
model=nfet_01v8
spiceprefix=X
}
C {sky130_fd_pr/nfet_01v8.sym} 600 1470 1 0 {name=M124
L=0.15
W=1
nf=1 
mult=1
ad="'int((nf+1)/2) * W/nf * 0.29'" 
pd="'2*int((nf+1)/2) * (W/nf + 0.29)'"
as="'int((nf+2)/2) * W/nf * 0.29'" 
ps="'2*int((nf+2)/2) * (W/nf + 0.29)'"
nrd="'0.29 / W'" nrs="'0.29 / W'"
sa=0 sb=0 sd=0
model=nfet_01v8
spiceprefix=X
}
C {devices/ipin.sym} 0 1510 0 0 {name=p48 lab=word25}
C {sky130_fd_pr/nfet_01v8.sym} 40 1530 1 0 {name=M125
L=0.15
W=1
nf=1 
mult=1
ad="'int((nf+1)/2) * W/nf * 0.29'" 
pd="'2*int((nf+1)/2) * (W/nf + 0.29)'"
as="'int((nf+2)/2) * W/nf * 0.29'" 
ps="'2*int((nf+2)/2) * (W/nf + 0.29)'"
nrd="'0.29 / W'" nrs="'0.29 / W'"
sa=0 sb=0 sd=0
model=nfet_01v8
spiceprefix=X
}
C {sky130_fd_pr/nfet_01v8.sym} 120 1530 1 0 {name=M126
L=0.15
W=1
nf=1 
mult=1
ad="'int((nf+1)/2) * W/nf * 0.29'" 
pd="'2*int((nf+1)/2) * (W/nf + 0.29)'"
as="'int((nf+2)/2) * W/nf * 0.29'" 
ps="'2*int((nf+2)/2) * (W/nf + 0.29)'"
nrd="'0.29 / W'" nrs="'0.29 / W'"
sa=0 sb=0 sd=0
model=nfet_01v8
spiceprefix=X
}
C {sky130_fd_pr/nfet_01v8.sym} 280 1530 1 0 {name=M127
L=0.15
W=1
nf=1 
mult=1
ad="'int((nf+1)/2) * W/nf * 0.29'" 
pd="'2*int((nf+1)/2) * (W/nf + 0.29)'"
as="'int((nf+2)/2) * W/nf * 0.29'" 
ps="'2*int((nf+2)/2) * (W/nf + 0.29)'"
nrd="'0.29 / W'" nrs="'0.29 / W'"
sa=0 sb=0 sd=0
model=nfet_01v8
spiceprefix=X
}
C {sky130_fd_pr/nfet_01v8.sym} 360 1530 1 0 {name=M128
L=0.15
W=1
nf=1 
mult=1
ad="'int((nf+1)/2) * W/nf * 0.29'" 
pd="'2*int((nf+1)/2) * (W/nf + 0.29)'"
as="'int((nf+2)/2) * W/nf * 0.29'" 
ps="'2*int((nf+2)/2) * (W/nf + 0.29)'"
nrd="'0.29 / W'" nrs="'0.29 / W'"
sa=0 sb=0 sd=0
model=nfet_01v8
spiceprefix=X
}
C {sky130_fd_pr/nfet_01v8.sym} 440 1530 1 0 {name=M129
L=0.15
W=1
nf=1 
mult=1
ad="'int((nf+1)/2) * W/nf * 0.29'" 
pd="'2*int((nf+1)/2) * (W/nf + 0.29)'"
as="'int((nf+2)/2) * W/nf * 0.29'" 
ps="'2*int((nf+2)/2) * (W/nf + 0.29)'"
nrd="'0.29 / W'" nrs="'0.29 / W'"
sa=0 sb=0 sd=0
model=nfet_01v8
spiceprefix=X
}
C {sky130_fd_pr/nfet_01v8.sym} 520 1530 1 0 {name=M130
L=0.15
W=1
nf=1 
mult=1
ad="'int((nf+1)/2) * W/nf * 0.29'" 
pd="'2*int((nf+1)/2) * (W/nf + 0.29)'"
as="'int((nf+2)/2) * W/nf * 0.29'" 
ps="'2*int((nf+2)/2) * (W/nf + 0.29)'"
nrd="'0.29 / W'" nrs="'0.29 / W'"
sa=0 sb=0 sd=0
model=nfet_01v8
spiceprefix=X
}
C {sky130_fd_pr/nfet_01v8.sym} 600 1530 1 0 {name=M131
L=0.15
W=1
nf=1 
mult=1
ad="'int((nf+1)/2) * W/nf * 0.29'" 
pd="'2*int((nf+1)/2) * (W/nf + 0.29)'"
as="'int((nf+2)/2) * W/nf * 0.29'" 
ps="'2*int((nf+2)/2) * (W/nf + 0.29)'"
nrd="'0.29 / W'" nrs="'0.29 / W'"
sa=0 sb=0 sd=0
model=nfet_01v8
spiceprefix=X
}
C {devices/ipin.sym} 0 1570 0 0 {name=p49 lab=word26}
C {sky130_fd_pr/nfet_01v8.sym} 40 1590 1 0 {name=M132
L=0.15
W=1
nf=1 
mult=1
ad="'int((nf+1)/2) * W/nf * 0.29'" 
pd="'2*int((nf+1)/2) * (W/nf + 0.29)'"
as="'int((nf+2)/2) * W/nf * 0.29'" 
ps="'2*int((nf+2)/2) * (W/nf + 0.29)'"
nrd="'0.29 / W'" nrs="'0.29 / W'"
sa=0 sb=0 sd=0
model=nfet_01v8
spiceprefix=X
}
C {sky130_fd_pr/nfet_01v8.sym} 200 1590 1 0 {name=M133
L=0.15
W=1
nf=1 
mult=1
ad="'int((nf+1)/2) * W/nf * 0.29'" 
pd="'2*int((nf+1)/2) * (W/nf + 0.29)'"
as="'int((nf+2)/2) * W/nf * 0.29'" 
ps="'2*int((nf+2)/2) * (W/nf + 0.29)'"
nrd="'0.29 / W'" nrs="'0.29 / W'"
sa=0 sb=0 sd=0
model=nfet_01v8
spiceprefix=X
}
C {sky130_fd_pr/nfet_01v8.sym} 280 1590 1 0 {name=M134
L=0.15
W=1
nf=1 
mult=1
ad="'int((nf+1)/2) * W/nf * 0.29'" 
pd="'2*int((nf+1)/2) * (W/nf + 0.29)'"
as="'int((nf+2)/2) * W/nf * 0.29'" 
ps="'2*int((nf+2)/2) * (W/nf + 0.29)'"
nrd="'0.29 / W'" nrs="'0.29 / W'"
sa=0 sb=0 sd=0
model=nfet_01v8
spiceprefix=X
}
C {sky130_fd_pr/nfet_01v8.sym} 360 1590 1 0 {name=M135
L=0.15
W=1
nf=1 
mult=1
ad="'int((nf+1)/2) * W/nf * 0.29'" 
pd="'2*int((nf+1)/2) * (W/nf + 0.29)'"
as="'int((nf+2)/2) * W/nf * 0.29'" 
ps="'2*int((nf+2)/2) * (W/nf + 0.29)'"
nrd="'0.29 / W'" nrs="'0.29 / W'"
sa=0 sb=0 sd=0
model=nfet_01v8
spiceprefix=X
}
C {sky130_fd_pr/nfet_01v8.sym} 440 1590 1 0 {name=M136
L=0.15
W=1
nf=1 
mult=1
ad="'int((nf+1)/2) * W/nf * 0.29'" 
pd="'2*int((nf+1)/2) * (W/nf + 0.29)'"
as="'int((nf+2)/2) * W/nf * 0.29'" 
ps="'2*int((nf+2)/2) * (W/nf + 0.29)'"
nrd="'0.29 / W'" nrs="'0.29 / W'"
sa=0 sb=0 sd=0
model=nfet_01v8
spiceprefix=X
}
C {sky130_fd_pr/nfet_01v8.sym} 520 1590 1 0 {name=M137
L=0.15
W=1
nf=1 
mult=1
ad="'int((nf+1)/2) * W/nf * 0.29'" 
pd="'2*int((nf+1)/2) * (W/nf + 0.29)'"
as="'int((nf+2)/2) * W/nf * 0.29'" 
ps="'2*int((nf+2)/2) * (W/nf + 0.29)'"
nrd="'0.29 / W'" nrs="'0.29 / W'"
sa=0 sb=0 sd=0
model=nfet_01v8
spiceprefix=X
}
C {sky130_fd_pr/nfet_01v8.sym} 600 1590 1 0 {name=M138
L=0.15
W=1
nf=1 
mult=1
ad="'int((nf+1)/2) * W/nf * 0.29'" 
pd="'2*int((nf+1)/2) * (W/nf + 0.29)'"
as="'int((nf+2)/2) * W/nf * 0.29'" 
ps="'2*int((nf+2)/2) * (W/nf + 0.29)'"
nrd="'0.29 / W'" nrs="'0.29 / W'"
sa=0 sb=0 sd=0
model=nfet_01v8
spiceprefix=X
}
C {devices/ipin.sym} 0 1630 0 0 {name=p50 lab=word27}
C {sky130_fd_pr/nfet_01v8.sym} 40 1650 1 0 {name=M139
L=0.15
W=1
nf=1 
mult=1
ad="'int((nf+1)/2) * W/nf * 0.29'" 
pd="'2*int((nf+1)/2) * (W/nf + 0.29)'"
as="'int((nf+2)/2) * W/nf * 0.29'" 
ps="'2*int((nf+2)/2) * (W/nf + 0.29)'"
nrd="'0.29 / W'" nrs="'0.29 / W'"
sa=0 sb=0 sd=0
model=nfet_01v8
spiceprefix=X
}
C {sky130_fd_pr/nfet_01v8.sym} 280 1650 1 0 {name=M140
L=0.15
W=1
nf=1 
mult=1
ad="'int((nf+1)/2) * W/nf * 0.29'" 
pd="'2*int((nf+1)/2) * (W/nf + 0.29)'"
as="'int((nf+2)/2) * W/nf * 0.29'" 
ps="'2*int((nf+2)/2) * (W/nf + 0.29)'"
nrd="'0.29 / W'" nrs="'0.29 / W'"
sa=0 sb=0 sd=0
model=nfet_01v8
spiceprefix=X
}
C {sky130_fd_pr/nfet_01v8.sym} 360 1650 1 0 {name=M141
L=0.15
W=1
nf=1 
mult=1
ad="'int((nf+1)/2) * W/nf * 0.29'" 
pd="'2*int((nf+1)/2) * (W/nf + 0.29)'"
as="'int((nf+2)/2) * W/nf * 0.29'" 
ps="'2*int((nf+2)/2) * (W/nf + 0.29)'"
nrd="'0.29 / W'" nrs="'0.29 / W'"
sa=0 sb=0 sd=0
model=nfet_01v8
spiceprefix=X
}
C {sky130_fd_pr/nfet_01v8.sym} 440 1650 1 0 {name=M142
L=0.15
W=1
nf=1 
mult=1
ad="'int((nf+1)/2) * W/nf * 0.29'" 
pd="'2*int((nf+1)/2) * (W/nf + 0.29)'"
as="'int((nf+2)/2) * W/nf * 0.29'" 
ps="'2*int((nf+2)/2) * (W/nf + 0.29)'"
nrd="'0.29 / W'" nrs="'0.29 / W'"
sa=0 sb=0 sd=0
model=nfet_01v8
spiceprefix=X
}
C {sky130_fd_pr/nfet_01v8.sym} 520 1650 1 0 {name=M143
L=0.15
W=1
nf=1 
mult=1
ad="'int((nf+1)/2) * W/nf * 0.29'" 
pd="'2*int((nf+1)/2) * (W/nf + 0.29)'"
as="'int((nf+2)/2) * W/nf * 0.29'" 
ps="'2*int((nf+2)/2) * (W/nf + 0.29)'"
nrd="'0.29 / W'" nrs="'0.29 / W'"
sa=0 sb=0 sd=0
model=nfet_01v8
spiceprefix=X
}
C {sky130_fd_pr/nfet_01v8.sym} 600 1650 1 0 {name=M144
L=0.15
W=1
nf=1 
mult=1
ad="'int((nf+1)/2) * W/nf * 0.29'" 
pd="'2*int((nf+1)/2) * (W/nf + 0.29)'"
as="'int((nf+2)/2) * W/nf * 0.29'" 
ps="'2*int((nf+2)/2) * (W/nf + 0.29)'"
nrd="'0.29 / W'" nrs="'0.29 / W'"
sa=0 sb=0 sd=0
model=nfet_01v8
spiceprefix=X
}
C {devices/ipin.sym} 0 1690 0 0 {name=p51 lab=word28}
C {sky130_fd_pr/nfet_01v8.sym} 120 1710 1 0 {name=M145
L=0.15
W=1
nf=1 
mult=1
ad="'int((nf+1)/2) * W/nf * 0.29'" 
pd="'2*int((nf+1)/2) * (W/nf + 0.29)'"
as="'int((nf+2)/2) * W/nf * 0.29'" 
ps="'2*int((nf+2)/2) * (W/nf + 0.29)'"
nrd="'0.29 / W'" nrs="'0.29 / W'"
sa=0 sb=0 sd=0
model=nfet_01v8
spiceprefix=X
}
C {sky130_fd_pr/nfet_01v8.sym} 200 1710 1 0 {name=M146
L=0.15
W=1
nf=1 
mult=1
ad="'int((nf+1)/2) * W/nf * 0.29'" 
pd="'2*int((nf+1)/2) * (W/nf + 0.29)'"
as="'int((nf+2)/2) * W/nf * 0.29'" 
ps="'2*int((nf+2)/2) * (W/nf + 0.29)'"
nrd="'0.29 / W'" nrs="'0.29 / W'"
sa=0 sb=0 sd=0
model=nfet_01v8
spiceprefix=X
}
C {sky130_fd_pr/nfet_01v8.sym} 280 1710 1 0 {name=M147
L=0.15
W=1
nf=1 
mult=1
ad="'int((nf+1)/2) * W/nf * 0.29'" 
pd="'2*int((nf+1)/2) * (W/nf + 0.29)'"
as="'int((nf+2)/2) * W/nf * 0.29'" 
ps="'2*int((nf+2)/2) * (W/nf + 0.29)'"
nrd="'0.29 / W'" nrs="'0.29 / W'"
sa=0 sb=0 sd=0
model=nfet_01v8
spiceprefix=X
}
C {sky130_fd_pr/nfet_01v8.sym} 360 1710 1 0 {name=M148
L=0.15
W=1
nf=1 
mult=1
ad="'int((nf+1)/2) * W/nf * 0.29'" 
pd="'2*int((nf+1)/2) * (W/nf + 0.29)'"
as="'int((nf+2)/2) * W/nf * 0.29'" 
ps="'2*int((nf+2)/2) * (W/nf + 0.29)'"
nrd="'0.29 / W'" nrs="'0.29 / W'"
sa=0 sb=0 sd=0
model=nfet_01v8
spiceprefix=X
}
C {sky130_fd_pr/nfet_01v8.sym} 440 1710 1 0 {name=M149
L=0.15
W=1
nf=1 
mult=1
ad="'int((nf+1)/2) * W/nf * 0.29'" 
pd="'2*int((nf+1)/2) * (W/nf + 0.29)'"
as="'int((nf+2)/2) * W/nf * 0.29'" 
ps="'2*int((nf+2)/2) * (W/nf + 0.29)'"
nrd="'0.29 / W'" nrs="'0.29 / W'"
sa=0 sb=0 sd=0
model=nfet_01v8
spiceprefix=X
}
C {sky130_fd_pr/nfet_01v8.sym} 520 1710 1 0 {name=M150
L=0.15
W=1
nf=1 
mult=1
ad="'int((nf+1)/2) * W/nf * 0.29'" 
pd="'2*int((nf+1)/2) * (W/nf + 0.29)'"
as="'int((nf+2)/2) * W/nf * 0.29'" 
ps="'2*int((nf+2)/2) * (W/nf + 0.29)'"
nrd="'0.29 / W'" nrs="'0.29 / W'"
sa=0 sb=0 sd=0
model=nfet_01v8
spiceprefix=X
}
C {sky130_fd_pr/nfet_01v8.sym} 600 1710 1 0 {name=M151
L=0.15
W=1
nf=1 
mult=1
ad="'int((nf+1)/2) * W/nf * 0.29'" 
pd="'2*int((nf+1)/2) * (W/nf + 0.29)'"
as="'int((nf+2)/2) * W/nf * 0.29'" 
ps="'2*int((nf+2)/2) * (W/nf + 0.29)'"
nrd="'0.29 / W'" nrs="'0.29 / W'"
sa=0 sb=0 sd=0
model=nfet_01v8
spiceprefix=X
}
C {devices/ipin.sym} 0 1750 0 0 {name=p52 lab=word29}
C {sky130_fd_pr/nfet_01v8.sym} 120 1770 1 0 {name=M152
L=0.15
W=1
nf=1 
mult=1
ad="'int((nf+1)/2) * W/nf * 0.29'" 
pd="'2*int((nf+1)/2) * (W/nf + 0.29)'"
as="'int((nf+2)/2) * W/nf * 0.29'" 
ps="'2*int((nf+2)/2) * (W/nf + 0.29)'"
nrd="'0.29 / W'" nrs="'0.29 / W'"
sa=0 sb=0 sd=0
model=nfet_01v8
spiceprefix=X
}
C {sky130_fd_pr/nfet_01v8.sym} 280 1770 1 0 {name=M153
L=0.15
W=1
nf=1 
mult=1
ad="'int((nf+1)/2) * W/nf * 0.29'" 
pd="'2*int((nf+1)/2) * (W/nf + 0.29)'"
as="'int((nf+2)/2) * W/nf * 0.29'" 
ps="'2*int((nf+2)/2) * (W/nf + 0.29)'"
nrd="'0.29 / W'" nrs="'0.29 / W'"
sa=0 sb=0 sd=0
model=nfet_01v8
spiceprefix=X
}
C {sky130_fd_pr/nfet_01v8.sym} 360 1770 1 0 {name=M154
L=0.15
W=1
nf=1 
mult=1
ad="'int((nf+1)/2) * W/nf * 0.29'" 
pd="'2*int((nf+1)/2) * (W/nf + 0.29)'"
as="'int((nf+2)/2) * W/nf * 0.29'" 
ps="'2*int((nf+2)/2) * (W/nf + 0.29)'"
nrd="'0.29 / W'" nrs="'0.29 / W'"
sa=0 sb=0 sd=0
model=nfet_01v8
spiceprefix=X
}
C {sky130_fd_pr/nfet_01v8.sym} 440 1770 1 0 {name=M155
L=0.15
W=1
nf=1 
mult=1
ad="'int((nf+1)/2) * W/nf * 0.29'" 
pd="'2*int((nf+1)/2) * (W/nf + 0.29)'"
as="'int((nf+2)/2) * W/nf * 0.29'" 
ps="'2*int((nf+2)/2) * (W/nf + 0.29)'"
nrd="'0.29 / W'" nrs="'0.29 / W'"
sa=0 sb=0 sd=0
model=nfet_01v8
spiceprefix=X
}
C {sky130_fd_pr/nfet_01v8.sym} 520 1770 1 0 {name=M156
L=0.15
W=1
nf=1 
mult=1
ad="'int((nf+1)/2) * W/nf * 0.29'" 
pd="'2*int((nf+1)/2) * (W/nf + 0.29)'"
as="'int((nf+2)/2) * W/nf * 0.29'" 
ps="'2*int((nf+2)/2) * (W/nf + 0.29)'"
nrd="'0.29 / W'" nrs="'0.29 / W'"
sa=0 sb=0 sd=0
model=nfet_01v8
spiceprefix=X
}
C {sky130_fd_pr/nfet_01v8.sym} 600 1770 1 0 {name=M157
L=0.15
W=1
nf=1 
mult=1
ad="'int((nf+1)/2) * W/nf * 0.29'" 
pd="'2*int((nf+1)/2) * (W/nf + 0.29)'"
as="'int((nf+2)/2) * W/nf * 0.29'" 
ps="'2*int((nf+2)/2) * (W/nf + 0.29)'"
nrd="'0.29 / W'" nrs="'0.29 / W'"
sa=0 sb=0 sd=0
model=nfet_01v8
spiceprefix=X
}
C {devices/ipin.sym} 0 1810 0 0 {name=p53 lab=word30}
C {sky130_fd_pr/nfet_01v8.sym} 200 1830 1 0 {name=M158
L=0.15
W=1
nf=1 
mult=1
ad="'int((nf+1)/2) * W/nf * 0.29'" 
pd="'2*int((nf+1)/2) * (W/nf + 0.29)'"
as="'int((nf+2)/2) * W/nf * 0.29'" 
ps="'2*int((nf+2)/2) * (W/nf + 0.29)'"
nrd="'0.29 / W'" nrs="'0.29 / W'"
sa=0 sb=0 sd=0
model=nfet_01v8
spiceprefix=X
}
C {sky130_fd_pr/nfet_01v8.sym} 280 1830 1 0 {name=M159
L=0.15
W=1
nf=1 
mult=1
ad="'int((nf+1)/2) * W/nf * 0.29'" 
pd="'2*int((nf+1)/2) * (W/nf + 0.29)'"
as="'int((nf+2)/2) * W/nf * 0.29'" 
ps="'2*int((nf+2)/2) * (W/nf + 0.29)'"
nrd="'0.29 / W'" nrs="'0.29 / W'"
sa=0 sb=0 sd=0
model=nfet_01v8
spiceprefix=X
}
C {sky130_fd_pr/nfet_01v8.sym} 360 1830 1 0 {name=M160
L=0.15
W=1
nf=1 
mult=1
ad="'int((nf+1)/2) * W/nf * 0.29'" 
pd="'2*int((nf+1)/2) * (W/nf + 0.29)'"
as="'int((nf+2)/2) * W/nf * 0.29'" 
ps="'2*int((nf+2)/2) * (W/nf + 0.29)'"
nrd="'0.29 / W'" nrs="'0.29 / W'"
sa=0 sb=0 sd=0
model=nfet_01v8
spiceprefix=X
}
C {sky130_fd_pr/nfet_01v8.sym} 440 1830 1 0 {name=M161
L=0.15
W=1
nf=1 
mult=1
ad="'int((nf+1)/2) * W/nf * 0.29'" 
pd="'2*int((nf+1)/2) * (W/nf + 0.29)'"
as="'int((nf+2)/2) * W/nf * 0.29'" 
ps="'2*int((nf+2)/2) * (W/nf + 0.29)'"
nrd="'0.29 / W'" nrs="'0.29 / W'"
sa=0 sb=0 sd=0
model=nfet_01v8
spiceprefix=X
}
C {sky130_fd_pr/nfet_01v8.sym} 520 1830 1 0 {name=M162
L=0.15
W=1
nf=1 
mult=1
ad="'int((nf+1)/2) * W/nf * 0.29'" 
pd="'2*int((nf+1)/2) * (W/nf + 0.29)'"
as="'int((nf+2)/2) * W/nf * 0.29'" 
ps="'2*int((nf+2)/2) * (W/nf + 0.29)'"
nrd="'0.29 / W'" nrs="'0.29 / W'"
sa=0 sb=0 sd=0
model=nfet_01v8
spiceprefix=X
}
C {sky130_fd_pr/nfet_01v8.sym} 600 1830 1 0 {name=M163
L=0.15
W=1
nf=1 
mult=1
ad="'int((nf+1)/2) * W/nf * 0.29'" 
pd="'2*int((nf+1)/2) * (W/nf + 0.29)'"
as="'int((nf+2)/2) * W/nf * 0.29'" 
ps="'2*int((nf+2)/2) * (W/nf + 0.29)'"
nrd="'0.29 / W'" nrs="'0.29 / W'"
sa=0 sb=0 sd=0
model=nfet_01v8
spiceprefix=X
}
C {devices/ipin.sym} 0 1870 0 0 {name=p54 lab=word31}
C {sky130_fd_pr/nfet_01v8.sym} 280 1890 1 0 {name=M164
L=0.15
W=1
nf=1 
mult=1
ad="'int((nf+1)/2) * W/nf * 0.29'" 
pd="'2*int((nf+1)/2) * (W/nf + 0.29)'"
as="'int((nf+2)/2) * W/nf * 0.29'" 
ps="'2*int((nf+2)/2) * (W/nf + 0.29)'"
nrd="'0.29 / W'" nrs="'0.29 / W'"
sa=0 sb=0 sd=0
model=nfet_01v8
spiceprefix=X
}
C {sky130_fd_pr/nfet_01v8.sym} 360 1890 1 0 {name=M165
L=0.15
W=1
nf=1 
mult=1
ad="'int((nf+1)/2) * W/nf * 0.29'" 
pd="'2*int((nf+1)/2) * (W/nf + 0.29)'"
as="'int((nf+2)/2) * W/nf * 0.29'" 
ps="'2*int((nf+2)/2) * (W/nf + 0.29)'"
nrd="'0.29 / W'" nrs="'0.29 / W'"
sa=0 sb=0 sd=0
model=nfet_01v8
spiceprefix=X
}
C {sky130_fd_pr/nfet_01v8.sym} 440 1890 1 0 {name=M166
L=0.15
W=1
nf=1 
mult=1
ad="'int((nf+1)/2) * W/nf * 0.29'" 
pd="'2*int((nf+1)/2) * (W/nf + 0.29)'"
as="'int((nf+2)/2) * W/nf * 0.29'" 
ps="'2*int((nf+2)/2) * (W/nf + 0.29)'"
nrd="'0.29 / W'" nrs="'0.29 / W'"
sa=0 sb=0 sd=0
model=nfet_01v8
spiceprefix=X
}
C {sky130_fd_pr/nfet_01v8.sym} 520 1890 1 0 {name=M167
L=0.15
W=1
nf=1 
mult=1
ad="'int((nf+1)/2) * W/nf * 0.29'" 
pd="'2*int((nf+1)/2) * (W/nf + 0.29)'"
as="'int((nf+2)/2) * W/nf * 0.29'" 
ps="'2*int((nf+2)/2) * (W/nf + 0.29)'"
nrd="'0.29 / W'" nrs="'0.29 / W'"
sa=0 sb=0 sd=0
model=nfet_01v8
spiceprefix=X
}
C {sky130_fd_pr/nfet_01v8.sym} 600 1890 1 0 {name=M168
L=0.15
W=1
nf=1 
mult=1
ad="'int((nf+1)/2) * W/nf * 0.29'" 
pd="'2*int((nf+1)/2) * (W/nf + 0.29)'"
as="'int((nf+2)/2) * W/nf * 0.29'" 
ps="'2*int((nf+2)/2) * (W/nf + 0.29)'"
nrd="'0.29 / W'" nrs="'0.29 / W'"
sa=0 sb=0 sd=0
model=nfet_01v8
spiceprefix=X
}
C {devices/ipin.sym} 0 1930 0 0 {name=p55 lab=word32}
C {devices/ipin.sym} 0 1990 0 0 {name=p56 lab=word33}
C {sky130_fd_pr/nfet_01v8.sym} 360 2010 1 0 {name=M169
L=0.15
W=1
nf=1 
mult=1
ad="'int((nf+1)/2) * W/nf * 0.29'" 
pd="'2*int((nf+1)/2) * (W/nf + 0.29)'"
as="'int((nf+2)/2) * W/nf * 0.29'" 
ps="'2*int((nf+2)/2) * (W/nf + 0.29)'"
nrd="'0.29 / W'" nrs="'0.29 / W'"
sa=0 sb=0 sd=0
model=nfet_01v8
spiceprefix=X
}
C {sky130_fd_pr/nfet_01v8.sym} 440 2010 1 0 {name=M170
L=0.15
W=1
nf=1 
mult=1
ad="'int((nf+1)/2) * W/nf * 0.29'" 
pd="'2*int((nf+1)/2) * (W/nf + 0.29)'"
as="'int((nf+2)/2) * W/nf * 0.29'" 
ps="'2*int((nf+2)/2) * (W/nf + 0.29)'"
nrd="'0.29 / W'" nrs="'0.29 / W'"
sa=0 sb=0 sd=0
model=nfet_01v8
spiceprefix=X
}
C {sky130_fd_pr/nfet_01v8.sym} 520 2010 1 0 {name=M171
L=0.15
W=1
nf=1 
mult=1
ad="'int((nf+1)/2) * W/nf * 0.29'" 
pd="'2*int((nf+1)/2) * (W/nf + 0.29)'"
as="'int((nf+2)/2) * W/nf * 0.29'" 
ps="'2*int((nf+2)/2) * (W/nf + 0.29)'"
nrd="'0.29 / W'" nrs="'0.29 / W'"
sa=0 sb=0 sd=0
model=nfet_01v8
spiceprefix=X
}
C {sky130_fd_pr/nfet_01v8.sym} 600 2010 1 0 {name=M172
L=0.15
W=1
nf=1 
mult=1
ad="'int((nf+1)/2) * W/nf * 0.29'" 
pd="'2*int((nf+1)/2) * (W/nf + 0.29)'"
as="'int((nf+2)/2) * W/nf * 0.29'" 
ps="'2*int((nf+2)/2) * (W/nf + 0.29)'"
nrd="'0.29 / W'" nrs="'0.29 / W'"
sa=0 sb=0 sd=0
model=nfet_01v8
spiceprefix=X
}
C {devices/ipin.sym} 0 2050 0 0 {name=p57 lab=word34}
C {sky130_fd_pr/nfet_01v8.sym} 280 2070 1 0 {name=M173
L=0.15
W=1
nf=1 
mult=1
ad="'int((nf+1)/2) * W/nf * 0.29'" 
pd="'2*int((nf+1)/2) * (W/nf + 0.29)'"
as="'int((nf+2)/2) * W/nf * 0.29'" 
ps="'2*int((nf+2)/2) * (W/nf + 0.29)'"
nrd="'0.29 / W'" nrs="'0.29 / W'"
sa=0 sb=0 sd=0
model=nfet_01v8
spiceprefix=X
}
C {sky130_fd_pr/nfet_01v8.sym} 360 2070 1 0 {name=M174
L=0.15
W=1
nf=1 
mult=1
ad="'int((nf+1)/2) * W/nf * 0.29'" 
pd="'2*int((nf+1)/2) * (W/nf + 0.29)'"
as="'int((nf+2)/2) * W/nf * 0.29'" 
ps="'2*int((nf+2)/2) * (W/nf + 0.29)'"
nrd="'0.29 / W'" nrs="'0.29 / W'"
sa=0 sb=0 sd=0
model=nfet_01v8
spiceprefix=X
}
C {sky130_fd_pr/nfet_01v8.sym} 440 2070 1 0 {name=M175
L=0.15
W=1
nf=1 
mult=1
ad="'int((nf+1)/2) * W/nf * 0.29'" 
pd="'2*int((nf+1)/2) * (W/nf + 0.29)'"
as="'int((nf+2)/2) * W/nf * 0.29'" 
ps="'2*int((nf+2)/2) * (W/nf + 0.29)'"
nrd="'0.29 / W'" nrs="'0.29 / W'"
sa=0 sb=0 sd=0
model=nfet_01v8
spiceprefix=X
}
C {sky130_fd_pr/nfet_01v8.sym} 520 2070 1 0 {name=M176
L=0.15
W=1
nf=1 
mult=1
ad="'int((nf+1)/2) * W/nf * 0.29'" 
pd="'2*int((nf+1)/2) * (W/nf + 0.29)'"
as="'int((nf+2)/2) * W/nf * 0.29'" 
ps="'2*int((nf+2)/2) * (W/nf + 0.29)'"
nrd="'0.29 / W'" nrs="'0.29 / W'"
sa=0 sb=0 sd=0
model=nfet_01v8
spiceprefix=X
}
C {sky130_fd_pr/nfet_01v8.sym} 600 2070 1 0 {name=M177
L=0.15
W=1
nf=1 
mult=1
ad="'int((nf+1)/2) * W/nf * 0.29'" 
pd="'2*int((nf+1)/2) * (W/nf + 0.29)'"
as="'int((nf+2)/2) * W/nf * 0.29'" 
ps="'2*int((nf+2)/2) * (W/nf + 0.29)'"
nrd="'0.29 / W'" nrs="'0.29 / W'"
sa=0 sb=0 sd=0
model=nfet_01v8
spiceprefix=X
}
C {devices/ipin.sym} 0 2110 0 0 {name=p58 lab=word35}
C {sky130_fd_pr/nfet_01v8.sym} 200 2130 1 0 {name=M178
L=0.15
W=1
nf=1 
mult=1
ad="'int((nf+1)/2) * W/nf * 0.29'" 
pd="'2*int((nf+1)/2) * (W/nf + 0.29)'"
as="'int((nf+2)/2) * W/nf * 0.29'" 
ps="'2*int((nf+2)/2) * (W/nf + 0.29)'"
nrd="'0.29 / W'" nrs="'0.29 / W'"
sa=0 sb=0 sd=0
model=nfet_01v8
spiceprefix=X
}
C {sky130_fd_pr/nfet_01v8.sym} 360 2130 1 0 {name=M179
L=0.15
W=1
nf=1 
mult=1
ad="'int((nf+1)/2) * W/nf * 0.29'" 
pd="'2*int((nf+1)/2) * (W/nf + 0.29)'"
as="'int((nf+2)/2) * W/nf * 0.29'" 
ps="'2*int((nf+2)/2) * (W/nf + 0.29)'"
nrd="'0.29 / W'" nrs="'0.29 / W'"
sa=0 sb=0 sd=0
model=nfet_01v8
spiceprefix=X
}
C {sky130_fd_pr/nfet_01v8.sym} 440 2130 1 0 {name=M180
L=0.15
W=1
nf=1 
mult=1
ad="'int((nf+1)/2) * W/nf * 0.29'" 
pd="'2*int((nf+1)/2) * (W/nf + 0.29)'"
as="'int((nf+2)/2) * W/nf * 0.29'" 
ps="'2*int((nf+2)/2) * (W/nf + 0.29)'"
nrd="'0.29 / W'" nrs="'0.29 / W'"
sa=0 sb=0 sd=0
model=nfet_01v8
spiceprefix=X
}
C {sky130_fd_pr/nfet_01v8.sym} 520 2130 1 0 {name=M181
L=0.15
W=1
nf=1 
mult=1
ad="'int((nf+1)/2) * W/nf * 0.29'" 
pd="'2*int((nf+1)/2) * (W/nf + 0.29)'"
as="'int((nf+2)/2) * W/nf * 0.29'" 
ps="'2*int((nf+2)/2) * (W/nf + 0.29)'"
nrd="'0.29 / W'" nrs="'0.29 / W'"
sa=0 sb=0 sd=0
model=nfet_01v8
spiceprefix=X
}
C {sky130_fd_pr/nfet_01v8.sym} 600 2130 1 0 {name=M182
L=0.15
W=1
nf=1 
mult=1
ad="'int((nf+1)/2) * W/nf * 0.29'" 
pd="'2*int((nf+1)/2) * (W/nf + 0.29)'"
as="'int((nf+2)/2) * W/nf * 0.29'" 
ps="'2*int((nf+2)/2) * (W/nf + 0.29)'"
nrd="'0.29 / W'" nrs="'0.29 / W'"
sa=0 sb=0 sd=0
model=nfet_01v8
spiceprefix=X
}
C {devices/ipin.sym} 0 2170 0 0 {name=p59 lab=word36}
C {sky130_fd_pr/nfet_01v8.sym} 200 2190 1 0 {name=M183
L=0.15
W=1
nf=1 
mult=1
ad="'int((nf+1)/2) * W/nf * 0.29'" 
pd="'2*int((nf+1)/2) * (W/nf + 0.29)'"
as="'int((nf+2)/2) * W/nf * 0.29'" 
ps="'2*int((nf+2)/2) * (W/nf + 0.29)'"
nrd="'0.29 / W'" nrs="'0.29 / W'"
sa=0 sb=0 sd=0
model=nfet_01v8
spiceprefix=X
}
C {sky130_fd_pr/nfet_01v8.sym} 280 2190 1 0 {name=M184
L=0.15
W=1
nf=1 
mult=1
ad="'int((nf+1)/2) * W/nf * 0.29'" 
pd="'2*int((nf+1)/2) * (W/nf + 0.29)'"
as="'int((nf+2)/2) * W/nf * 0.29'" 
ps="'2*int((nf+2)/2) * (W/nf + 0.29)'"
nrd="'0.29 / W'" nrs="'0.29 / W'"
sa=0 sb=0 sd=0
model=nfet_01v8
spiceprefix=X
}
C {sky130_fd_pr/nfet_01v8.sym} 360 2190 1 0 {name=M185
L=0.15
W=1
nf=1 
mult=1
ad="'int((nf+1)/2) * W/nf * 0.29'" 
pd="'2*int((nf+1)/2) * (W/nf + 0.29)'"
as="'int((nf+2)/2) * W/nf * 0.29'" 
ps="'2*int((nf+2)/2) * (W/nf + 0.29)'"
nrd="'0.29 / W'" nrs="'0.29 / W'"
sa=0 sb=0 sd=0
model=nfet_01v8
spiceprefix=X
}
C {sky130_fd_pr/nfet_01v8.sym} 440 2190 1 0 {name=M186
L=0.15
W=1
nf=1 
mult=1
ad="'int((nf+1)/2) * W/nf * 0.29'" 
pd="'2*int((nf+1)/2) * (W/nf + 0.29)'"
as="'int((nf+2)/2) * W/nf * 0.29'" 
ps="'2*int((nf+2)/2) * (W/nf + 0.29)'"
nrd="'0.29 / W'" nrs="'0.29 / W'"
sa=0 sb=0 sd=0
model=nfet_01v8
spiceprefix=X
}
C {sky130_fd_pr/nfet_01v8.sym} 520 2190 1 0 {name=M187
L=0.15
W=1
nf=1 
mult=1
ad="'int((nf+1)/2) * W/nf * 0.29'" 
pd="'2*int((nf+1)/2) * (W/nf + 0.29)'"
as="'int((nf+2)/2) * W/nf * 0.29'" 
ps="'2*int((nf+2)/2) * (W/nf + 0.29)'"
nrd="'0.29 / W'" nrs="'0.29 / W'"
sa=0 sb=0 sd=0
model=nfet_01v8
spiceprefix=X
}
C {sky130_fd_pr/nfet_01v8.sym} 600 2190 1 0 {name=M188
L=0.15
W=1
nf=1 
mult=1
ad="'int((nf+1)/2) * W/nf * 0.29'" 
pd="'2*int((nf+1)/2) * (W/nf + 0.29)'"
as="'int((nf+2)/2) * W/nf * 0.29'" 
ps="'2*int((nf+2)/2) * (W/nf + 0.29)'"
nrd="'0.29 / W'" nrs="'0.29 / W'"
sa=0 sb=0 sd=0
model=nfet_01v8
spiceprefix=X
}
C {devices/ipin.sym} 0 2230 0 0 {name=p60 lab=word37}
C {sky130_fd_pr/nfet_01v8.sym} 120 2250 1 0 {name=M189
L=0.15
W=1
nf=1 
mult=1
ad="'int((nf+1)/2) * W/nf * 0.29'" 
pd="'2*int((nf+1)/2) * (W/nf + 0.29)'"
as="'int((nf+2)/2) * W/nf * 0.29'" 
ps="'2*int((nf+2)/2) * (W/nf + 0.29)'"
nrd="'0.29 / W'" nrs="'0.29 / W'"
sa=0 sb=0 sd=0
model=nfet_01v8
spiceprefix=X
}
C {sky130_fd_pr/nfet_01v8.sym} 360 2250 1 0 {name=M190
L=0.15
W=1
nf=1 
mult=1
ad="'int((nf+1)/2) * W/nf * 0.29'" 
pd="'2*int((nf+1)/2) * (W/nf + 0.29)'"
as="'int((nf+2)/2) * W/nf * 0.29'" 
ps="'2*int((nf+2)/2) * (W/nf + 0.29)'"
nrd="'0.29 / W'" nrs="'0.29 / W'"
sa=0 sb=0 sd=0
model=nfet_01v8
spiceprefix=X
}
C {sky130_fd_pr/nfet_01v8.sym} 440 2250 1 0 {name=M191
L=0.15
W=1
nf=1 
mult=1
ad="'int((nf+1)/2) * W/nf * 0.29'" 
pd="'2*int((nf+1)/2) * (W/nf + 0.29)'"
as="'int((nf+2)/2) * W/nf * 0.29'" 
ps="'2*int((nf+2)/2) * (W/nf + 0.29)'"
nrd="'0.29 / W'" nrs="'0.29 / W'"
sa=0 sb=0 sd=0
model=nfet_01v8
spiceprefix=X
}
C {sky130_fd_pr/nfet_01v8.sym} 520 2250 1 0 {name=M192
L=0.15
W=1
nf=1 
mult=1
ad="'int((nf+1)/2) * W/nf * 0.29'" 
pd="'2*int((nf+1)/2) * (W/nf + 0.29)'"
as="'int((nf+2)/2) * W/nf * 0.29'" 
ps="'2*int((nf+2)/2) * (W/nf + 0.29)'"
nrd="'0.29 / W'" nrs="'0.29 / W'"
sa=0 sb=0 sd=0
model=nfet_01v8
spiceprefix=X
}
C {sky130_fd_pr/nfet_01v8.sym} 600 2250 1 0 {name=M193
L=0.15
W=1
nf=1 
mult=1
ad="'int((nf+1)/2) * W/nf * 0.29'" 
pd="'2*int((nf+1)/2) * (W/nf + 0.29)'"
as="'int((nf+2)/2) * W/nf * 0.29'" 
ps="'2*int((nf+2)/2) * (W/nf + 0.29)'"
nrd="'0.29 / W'" nrs="'0.29 / W'"
sa=0 sb=0 sd=0
model=nfet_01v8
spiceprefix=X
}
C {devices/ipin.sym} 0 2290 0 0 {name=p61 lab=word38}
C {sky130_fd_pr/nfet_01v8.sym} 120 2310 1 0 {name=M194
L=0.15
W=1
nf=1 
mult=1
ad="'int((nf+1)/2) * W/nf * 0.29'" 
pd="'2*int((nf+1)/2) * (W/nf + 0.29)'"
as="'int((nf+2)/2) * W/nf * 0.29'" 
ps="'2*int((nf+2)/2) * (W/nf + 0.29)'"
nrd="'0.29 / W'" nrs="'0.29 / W'"
sa=0 sb=0 sd=0
model=nfet_01v8
spiceprefix=X
}
C {sky130_fd_pr/nfet_01v8.sym} 280 2310 1 0 {name=M195
L=0.15
W=1
nf=1 
mult=1
ad="'int((nf+1)/2) * W/nf * 0.29'" 
pd="'2*int((nf+1)/2) * (W/nf + 0.29)'"
as="'int((nf+2)/2) * W/nf * 0.29'" 
ps="'2*int((nf+2)/2) * (W/nf + 0.29)'"
nrd="'0.29 / W'" nrs="'0.29 / W'"
sa=0 sb=0 sd=0
model=nfet_01v8
spiceprefix=X
}
C {sky130_fd_pr/nfet_01v8.sym} 360 2310 1 0 {name=M196
L=0.15
W=1
nf=1 
mult=1
ad="'int((nf+1)/2) * W/nf * 0.29'" 
pd="'2*int((nf+1)/2) * (W/nf + 0.29)'"
as="'int((nf+2)/2) * W/nf * 0.29'" 
ps="'2*int((nf+2)/2) * (W/nf + 0.29)'"
nrd="'0.29 / W'" nrs="'0.29 / W'"
sa=0 sb=0 sd=0
model=nfet_01v8
spiceprefix=X
}
C {sky130_fd_pr/nfet_01v8.sym} 440 2310 1 0 {name=M197
L=0.15
W=1
nf=1 
mult=1
ad="'int((nf+1)/2) * W/nf * 0.29'" 
pd="'2*int((nf+1)/2) * (W/nf + 0.29)'"
as="'int((nf+2)/2) * W/nf * 0.29'" 
ps="'2*int((nf+2)/2) * (W/nf + 0.29)'"
nrd="'0.29 / W'" nrs="'0.29 / W'"
sa=0 sb=0 sd=0
model=nfet_01v8
spiceprefix=X
}
C {sky130_fd_pr/nfet_01v8.sym} 520 2310 1 0 {name=M198
L=0.15
W=1
nf=1 
mult=1
ad="'int((nf+1)/2) * W/nf * 0.29'" 
pd="'2*int((nf+1)/2) * (W/nf + 0.29)'"
as="'int((nf+2)/2) * W/nf * 0.29'" 
ps="'2*int((nf+2)/2) * (W/nf + 0.29)'"
nrd="'0.29 / W'" nrs="'0.29 / W'"
sa=0 sb=0 sd=0
model=nfet_01v8
spiceprefix=X
}
C {sky130_fd_pr/nfet_01v8.sym} 600 2310 1 0 {name=M199
L=0.15
W=1
nf=1 
mult=1
ad="'int((nf+1)/2) * W/nf * 0.29'" 
pd="'2*int((nf+1)/2) * (W/nf + 0.29)'"
as="'int((nf+2)/2) * W/nf * 0.29'" 
ps="'2*int((nf+2)/2) * (W/nf + 0.29)'"
nrd="'0.29 / W'" nrs="'0.29 / W'"
sa=0 sb=0 sd=0
model=nfet_01v8
spiceprefix=X
}
C {devices/ipin.sym} 0 2350 0 0 {name=p62 lab=word39}
C {sky130_fd_pr/nfet_01v8.sym} 120 2370 1 0 {name=M200
L=0.15
W=1
nf=1 
mult=1
ad="'int((nf+1)/2) * W/nf * 0.29'" 
pd="'2*int((nf+1)/2) * (W/nf + 0.29)'"
as="'int((nf+2)/2) * W/nf * 0.29'" 
ps="'2*int((nf+2)/2) * (W/nf + 0.29)'"
nrd="'0.29 / W'" nrs="'0.29 / W'"
sa=0 sb=0 sd=0
model=nfet_01v8
spiceprefix=X
}
C {sky130_fd_pr/nfet_01v8.sym} 200 2370 1 0 {name=M201
L=0.15
W=1
nf=1 
mult=1
ad="'int((nf+1)/2) * W/nf * 0.29'" 
pd="'2*int((nf+1)/2) * (W/nf + 0.29)'"
as="'int((nf+2)/2) * W/nf * 0.29'" 
ps="'2*int((nf+2)/2) * (W/nf + 0.29)'"
nrd="'0.29 / W'" nrs="'0.29 / W'"
sa=0 sb=0 sd=0
model=nfet_01v8
spiceprefix=X
}
C {sky130_fd_pr/nfet_01v8.sym} 360 2370 1 0 {name=M202
L=0.15
W=1
nf=1 
mult=1
ad="'int((nf+1)/2) * W/nf * 0.29'" 
pd="'2*int((nf+1)/2) * (W/nf + 0.29)'"
as="'int((nf+2)/2) * W/nf * 0.29'" 
ps="'2*int((nf+2)/2) * (W/nf + 0.29)'"
nrd="'0.29 / W'" nrs="'0.29 / W'"
sa=0 sb=0 sd=0
model=nfet_01v8
spiceprefix=X
}
C {sky130_fd_pr/nfet_01v8.sym} 440 2370 1 0 {name=M203
L=0.15
W=1
nf=1 
mult=1
ad="'int((nf+1)/2) * W/nf * 0.29'" 
pd="'2*int((nf+1)/2) * (W/nf + 0.29)'"
as="'int((nf+2)/2) * W/nf * 0.29'" 
ps="'2*int((nf+2)/2) * (W/nf + 0.29)'"
nrd="'0.29 / W'" nrs="'0.29 / W'"
sa=0 sb=0 sd=0
model=nfet_01v8
spiceprefix=X
}
C {sky130_fd_pr/nfet_01v8.sym} 520 2370 1 0 {name=M204
L=0.15
W=1
nf=1 
mult=1
ad="'int((nf+1)/2) * W/nf * 0.29'" 
pd="'2*int((nf+1)/2) * (W/nf + 0.29)'"
as="'int((nf+2)/2) * W/nf * 0.29'" 
ps="'2*int((nf+2)/2) * (W/nf + 0.29)'"
nrd="'0.29 / W'" nrs="'0.29 / W'"
sa=0 sb=0 sd=0
model=nfet_01v8
spiceprefix=X
}
C {sky130_fd_pr/nfet_01v8.sym} 600 2370 1 0 {name=M205
L=0.15
W=1
nf=1 
mult=1
ad="'int((nf+1)/2) * W/nf * 0.29'" 
pd="'2*int((nf+1)/2) * (W/nf + 0.29)'"
as="'int((nf+2)/2) * W/nf * 0.29'" 
ps="'2*int((nf+2)/2) * (W/nf + 0.29)'"
nrd="'0.29 / W'" nrs="'0.29 / W'"
sa=0 sb=0 sd=0
model=nfet_01v8
spiceprefix=X
}
C {devices/ipin.sym} 0 2410 0 0 {name=p63 lab=word40}
C {sky130_fd_pr/nfet_01v8.sym} 120 2430 1 0 {name=M206
L=0.15
W=1
nf=1 
mult=1
ad="'int((nf+1)/2) * W/nf * 0.29'" 
pd="'2*int((nf+1)/2) * (W/nf + 0.29)'"
as="'int((nf+2)/2) * W/nf * 0.29'" 
ps="'2*int((nf+2)/2) * (W/nf + 0.29)'"
nrd="'0.29 / W'" nrs="'0.29 / W'"
sa=0 sb=0 sd=0
model=nfet_01v8
spiceprefix=X
}
C {sky130_fd_pr/nfet_01v8.sym} 200 2430 1 0 {name=M207
L=0.15
W=1
nf=1 
mult=1
ad="'int((nf+1)/2) * W/nf * 0.29'" 
pd="'2*int((nf+1)/2) * (W/nf + 0.29)'"
as="'int((nf+2)/2) * W/nf * 0.29'" 
ps="'2*int((nf+2)/2) * (W/nf + 0.29)'"
nrd="'0.29 / W'" nrs="'0.29 / W'"
sa=0 sb=0 sd=0
model=nfet_01v8
spiceprefix=X
}
C {sky130_fd_pr/nfet_01v8.sym} 280 2430 1 0 {name=M208
L=0.15
W=1
nf=1 
mult=1
ad="'int((nf+1)/2) * W/nf * 0.29'" 
pd="'2*int((nf+1)/2) * (W/nf + 0.29)'"
as="'int((nf+2)/2) * W/nf * 0.29'" 
ps="'2*int((nf+2)/2) * (W/nf + 0.29)'"
nrd="'0.29 / W'" nrs="'0.29 / W'"
sa=0 sb=0 sd=0
model=nfet_01v8
spiceprefix=X
}
C {sky130_fd_pr/nfet_01v8.sym} 360 2430 1 0 {name=M209
L=0.15
W=1
nf=1 
mult=1
ad="'int((nf+1)/2) * W/nf * 0.29'" 
pd="'2*int((nf+1)/2) * (W/nf + 0.29)'"
as="'int((nf+2)/2) * W/nf * 0.29'" 
ps="'2*int((nf+2)/2) * (W/nf + 0.29)'"
nrd="'0.29 / W'" nrs="'0.29 / W'"
sa=0 sb=0 sd=0
model=nfet_01v8
spiceprefix=X
}
C {sky130_fd_pr/nfet_01v8.sym} 440 2430 1 0 {name=M210
L=0.15
W=1
nf=1 
mult=1
ad="'int((nf+1)/2) * W/nf * 0.29'" 
pd="'2*int((nf+1)/2) * (W/nf + 0.29)'"
as="'int((nf+2)/2) * W/nf * 0.29'" 
ps="'2*int((nf+2)/2) * (W/nf + 0.29)'"
nrd="'0.29 / W'" nrs="'0.29 / W'"
sa=0 sb=0 sd=0
model=nfet_01v8
spiceprefix=X
}
C {sky130_fd_pr/nfet_01v8.sym} 520 2430 1 0 {name=M211
L=0.15
W=1
nf=1 
mult=1
ad="'int((nf+1)/2) * W/nf * 0.29'" 
pd="'2*int((nf+1)/2) * (W/nf + 0.29)'"
as="'int((nf+2)/2) * W/nf * 0.29'" 
ps="'2*int((nf+2)/2) * (W/nf + 0.29)'"
nrd="'0.29 / W'" nrs="'0.29 / W'"
sa=0 sb=0 sd=0
model=nfet_01v8
spiceprefix=X
}
C {sky130_fd_pr/nfet_01v8.sym} 600 2430 1 0 {name=M212
L=0.15
W=1
nf=1 
mult=1
ad="'int((nf+1)/2) * W/nf * 0.29'" 
pd="'2*int((nf+1)/2) * (W/nf + 0.29)'"
as="'int((nf+2)/2) * W/nf * 0.29'" 
ps="'2*int((nf+2)/2) * (W/nf + 0.29)'"
nrd="'0.29 / W'" nrs="'0.29 / W'"
sa=0 sb=0 sd=0
model=nfet_01v8
spiceprefix=X
}
C {devices/ipin.sym} 0 2470 0 0 {name=p64 lab=word41}
C {sky130_fd_pr/nfet_01v8.sym} 40 2490 1 0 {name=M213
L=0.15
W=1
nf=1 
mult=1
ad="'int((nf+1)/2) * W/nf * 0.29'" 
pd="'2*int((nf+1)/2) * (W/nf + 0.29)'"
as="'int((nf+2)/2) * W/nf * 0.29'" 
ps="'2*int((nf+2)/2) * (W/nf + 0.29)'"
nrd="'0.29 / W'" nrs="'0.29 / W'"
sa=0 sb=0 sd=0
model=nfet_01v8
spiceprefix=X
}
C {sky130_fd_pr/nfet_01v8.sym} 360 2490 1 0 {name=M214
L=0.15
W=1
nf=1 
mult=1
ad="'int((nf+1)/2) * W/nf * 0.29'" 
pd="'2*int((nf+1)/2) * (W/nf + 0.29)'"
as="'int((nf+2)/2) * W/nf * 0.29'" 
ps="'2*int((nf+2)/2) * (W/nf + 0.29)'"
nrd="'0.29 / W'" nrs="'0.29 / W'"
sa=0 sb=0 sd=0
model=nfet_01v8
spiceprefix=X
}
C {sky130_fd_pr/nfet_01v8.sym} 440 2490 1 0 {name=M215
L=0.15
W=1
nf=1 
mult=1
ad="'int((nf+1)/2) * W/nf * 0.29'" 
pd="'2*int((nf+1)/2) * (W/nf + 0.29)'"
as="'int((nf+2)/2) * W/nf * 0.29'" 
ps="'2*int((nf+2)/2) * (W/nf + 0.29)'"
nrd="'0.29 / W'" nrs="'0.29 / W'"
sa=0 sb=0 sd=0
model=nfet_01v8
spiceprefix=X
}
C {sky130_fd_pr/nfet_01v8.sym} 520 2490 1 0 {name=M216
L=0.15
W=1
nf=1 
mult=1
ad="'int((nf+1)/2) * W/nf * 0.29'" 
pd="'2*int((nf+1)/2) * (W/nf + 0.29)'"
as="'int((nf+2)/2) * W/nf * 0.29'" 
ps="'2*int((nf+2)/2) * (W/nf + 0.29)'"
nrd="'0.29 / W'" nrs="'0.29 / W'"
sa=0 sb=0 sd=0
model=nfet_01v8
spiceprefix=X
}
C {sky130_fd_pr/nfet_01v8.sym} 600 2490 1 0 {name=M217
L=0.15
W=1
nf=1 
mult=1
ad="'int((nf+1)/2) * W/nf * 0.29'" 
pd="'2*int((nf+1)/2) * (W/nf + 0.29)'"
as="'int((nf+2)/2) * W/nf * 0.29'" 
ps="'2*int((nf+2)/2) * (W/nf + 0.29)'"
nrd="'0.29 / W'" nrs="'0.29 / W'"
sa=0 sb=0 sd=0
model=nfet_01v8
spiceprefix=X
}
C {devices/ipin.sym} 0 2530 0 0 {name=p65 lab=word42}
C {sky130_fd_pr/nfet_01v8.sym} 40 2550 1 0 {name=M218
L=0.15
W=1
nf=1 
mult=1
ad="'int((nf+1)/2) * W/nf * 0.29'" 
pd="'2*int((nf+1)/2) * (W/nf + 0.29)'"
as="'int((nf+2)/2) * W/nf * 0.29'" 
ps="'2*int((nf+2)/2) * (W/nf + 0.29)'"
nrd="'0.29 / W'" nrs="'0.29 / W'"
sa=0 sb=0 sd=0
model=nfet_01v8
spiceprefix=X
}
C {sky130_fd_pr/nfet_01v8.sym} 280 2550 1 0 {name=M219
L=0.15
W=1
nf=1 
mult=1
ad="'int((nf+1)/2) * W/nf * 0.29'" 
pd="'2*int((nf+1)/2) * (W/nf + 0.29)'"
as="'int((nf+2)/2) * W/nf * 0.29'" 
ps="'2*int((nf+2)/2) * (W/nf + 0.29)'"
nrd="'0.29 / W'" nrs="'0.29 / W'"
sa=0 sb=0 sd=0
model=nfet_01v8
spiceprefix=X
}
C {sky130_fd_pr/nfet_01v8.sym} 360 2550 1 0 {name=M220
L=0.15
W=1
nf=1 
mult=1
ad="'int((nf+1)/2) * W/nf * 0.29'" 
pd="'2*int((nf+1)/2) * (W/nf + 0.29)'"
as="'int((nf+2)/2) * W/nf * 0.29'" 
ps="'2*int((nf+2)/2) * (W/nf + 0.29)'"
nrd="'0.29 / W'" nrs="'0.29 / W'"
sa=0 sb=0 sd=0
model=nfet_01v8
spiceprefix=X
}
C {sky130_fd_pr/nfet_01v8.sym} 440 2550 1 0 {name=M221
L=0.15
W=1
nf=1 
mult=1
ad="'int((nf+1)/2) * W/nf * 0.29'" 
pd="'2*int((nf+1)/2) * (W/nf + 0.29)'"
as="'int((nf+2)/2) * W/nf * 0.29'" 
ps="'2*int((nf+2)/2) * (W/nf + 0.29)'"
nrd="'0.29 / W'" nrs="'0.29 / W'"
sa=0 sb=0 sd=0
model=nfet_01v8
spiceprefix=X
}
C {sky130_fd_pr/nfet_01v8.sym} 520 2550 1 0 {name=M222
L=0.15
W=1
nf=1 
mult=1
ad="'int((nf+1)/2) * W/nf * 0.29'" 
pd="'2*int((nf+1)/2) * (W/nf + 0.29)'"
as="'int((nf+2)/2) * W/nf * 0.29'" 
ps="'2*int((nf+2)/2) * (W/nf + 0.29)'"
nrd="'0.29 / W'" nrs="'0.29 / W'"
sa=0 sb=0 sd=0
model=nfet_01v8
spiceprefix=X
}
C {sky130_fd_pr/nfet_01v8.sym} 600 2550 1 0 {name=M223
L=0.15
W=1
nf=1 
mult=1
ad="'int((nf+1)/2) * W/nf * 0.29'" 
pd="'2*int((nf+1)/2) * (W/nf + 0.29)'"
as="'int((nf+2)/2) * W/nf * 0.29'" 
ps="'2*int((nf+2)/2) * (W/nf + 0.29)'"
nrd="'0.29 / W'" nrs="'0.29 / W'"
sa=0 sb=0 sd=0
model=nfet_01v8
spiceprefix=X
}
C {devices/ipin.sym} 0 2590 0 0 {name=p66 lab=word43}
C {sky130_fd_pr/nfet_01v8.sym} 40 2610 1 0 {name=M224
L=0.15
W=1
nf=1 
mult=1
ad="'int((nf+1)/2) * W/nf * 0.29'" 
pd="'2*int((nf+1)/2) * (W/nf + 0.29)'"
as="'int((nf+2)/2) * W/nf * 0.29'" 
ps="'2*int((nf+2)/2) * (W/nf + 0.29)'"
nrd="'0.29 / W'" nrs="'0.29 / W'"
sa=0 sb=0 sd=0
model=nfet_01v8
spiceprefix=X
}
C {sky130_fd_pr/nfet_01v8.sym} 200 2610 1 0 {name=M225
L=0.15
W=1
nf=1 
mult=1
ad="'int((nf+1)/2) * W/nf * 0.29'" 
pd="'2*int((nf+1)/2) * (W/nf + 0.29)'"
as="'int((nf+2)/2) * W/nf * 0.29'" 
ps="'2*int((nf+2)/2) * (W/nf + 0.29)'"
nrd="'0.29 / W'" nrs="'0.29 / W'"
sa=0 sb=0 sd=0
model=nfet_01v8
spiceprefix=X
}
C {sky130_fd_pr/nfet_01v8.sym} 360 2610 1 0 {name=M226
L=0.15
W=1
nf=1 
mult=1
ad="'int((nf+1)/2) * W/nf * 0.29'" 
pd="'2*int((nf+1)/2) * (W/nf + 0.29)'"
as="'int((nf+2)/2) * W/nf * 0.29'" 
ps="'2*int((nf+2)/2) * (W/nf + 0.29)'"
nrd="'0.29 / W'" nrs="'0.29 / W'"
sa=0 sb=0 sd=0
model=nfet_01v8
spiceprefix=X
}
C {sky130_fd_pr/nfet_01v8.sym} 440 2610 1 0 {name=M227
L=0.15
W=1
nf=1 
mult=1
ad="'int((nf+1)/2) * W/nf * 0.29'" 
pd="'2*int((nf+1)/2) * (W/nf + 0.29)'"
as="'int((nf+2)/2) * W/nf * 0.29'" 
ps="'2*int((nf+2)/2) * (W/nf + 0.29)'"
nrd="'0.29 / W'" nrs="'0.29 / W'"
sa=0 sb=0 sd=0
model=nfet_01v8
spiceprefix=X
}
C {sky130_fd_pr/nfet_01v8.sym} 520 2610 1 0 {name=M228
L=0.15
W=1
nf=1 
mult=1
ad="'int((nf+1)/2) * W/nf * 0.29'" 
pd="'2*int((nf+1)/2) * (W/nf + 0.29)'"
as="'int((nf+2)/2) * W/nf * 0.29'" 
ps="'2*int((nf+2)/2) * (W/nf + 0.29)'"
nrd="'0.29 / W'" nrs="'0.29 / W'"
sa=0 sb=0 sd=0
model=nfet_01v8
spiceprefix=X
}
C {sky130_fd_pr/nfet_01v8.sym} 600 2610 1 0 {name=M229
L=0.15
W=1
nf=1 
mult=1
ad="'int((nf+1)/2) * W/nf * 0.29'" 
pd="'2*int((nf+1)/2) * (W/nf + 0.29)'"
as="'int((nf+2)/2) * W/nf * 0.29'" 
ps="'2*int((nf+2)/2) * (W/nf + 0.29)'"
nrd="'0.29 / W'" nrs="'0.29 / W'"
sa=0 sb=0 sd=0
model=nfet_01v8
spiceprefix=X
}
C {devices/ipin.sym} 0 2650 0 0 {name=p67 lab=word44}
C {sky130_fd_pr/nfet_01v8.sym} 40 2670 1 0 {name=M230
L=0.15
W=1
nf=1 
mult=1
ad="'int((nf+1)/2) * W/nf * 0.29'" 
pd="'2*int((nf+1)/2) * (W/nf + 0.29)'"
as="'int((nf+2)/2) * W/nf * 0.29'" 
ps="'2*int((nf+2)/2) * (W/nf + 0.29)'"
nrd="'0.29 / W'" nrs="'0.29 / W'"
sa=0 sb=0 sd=0
model=nfet_01v8
spiceprefix=X
}
C {sky130_fd_pr/nfet_01v8.sym} 200 2670 1 0 {name=M231
L=0.15
W=1
nf=1 
mult=1
ad="'int((nf+1)/2) * W/nf * 0.29'" 
pd="'2*int((nf+1)/2) * (W/nf + 0.29)'"
as="'int((nf+2)/2) * W/nf * 0.29'" 
ps="'2*int((nf+2)/2) * (W/nf + 0.29)'"
nrd="'0.29 / W'" nrs="'0.29 / W'"
sa=0 sb=0 sd=0
model=nfet_01v8
spiceprefix=X
}
C {sky130_fd_pr/nfet_01v8.sym} 280 2670 1 0 {name=M232
L=0.15
W=1
nf=1 
mult=1
ad="'int((nf+1)/2) * W/nf * 0.29'" 
pd="'2*int((nf+1)/2) * (W/nf + 0.29)'"
as="'int((nf+2)/2) * W/nf * 0.29'" 
ps="'2*int((nf+2)/2) * (W/nf + 0.29)'"
nrd="'0.29 / W'" nrs="'0.29 / W'"
sa=0 sb=0 sd=0
model=nfet_01v8
spiceprefix=X
}
C {sky130_fd_pr/nfet_01v8.sym} 360 2670 1 0 {name=M233
L=0.15
W=1
nf=1 
mult=1
ad="'int((nf+1)/2) * W/nf * 0.29'" 
pd="'2*int((nf+1)/2) * (W/nf + 0.29)'"
as="'int((nf+2)/2) * W/nf * 0.29'" 
ps="'2*int((nf+2)/2) * (W/nf + 0.29)'"
nrd="'0.29 / W'" nrs="'0.29 / W'"
sa=0 sb=0 sd=0
model=nfet_01v8
spiceprefix=X
}
C {sky130_fd_pr/nfet_01v8.sym} 440 2670 1 0 {name=M234
L=0.15
W=1
nf=1 
mult=1
ad="'int((nf+1)/2) * W/nf * 0.29'" 
pd="'2*int((nf+1)/2) * (W/nf + 0.29)'"
as="'int((nf+2)/2) * W/nf * 0.29'" 
ps="'2*int((nf+2)/2) * (W/nf + 0.29)'"
nrd="'0.29 / W'" nrs="'0.29 / W'"
sa=0 sb=0 sd=0
model=nfet_01v8
spiceprefix=X
}
C {sky130_fd_pr/nfet_01v8.sym} 520 2670 1 0 {name=M235
L=0.15
W=1
nf=1 
mult=1
ad="'int((nf+1)/2) * W/nf * 0.29'" 
pd="'2*int((nf+1)/2) * (W/nf + 0.29)'"
as="'int((nf+2)/2) * W/nf * 0.29'" 
ps="'2*int((nf+2)/2) * (W/nf + 0.29)'"
nrd="'0.29 / W'" nrs="'0.29 / W'"
sa=0 sb=0 sd=0
model=nfet_01v8
spiceprefix=X
}
C {sky130_fd_pr/nfet_01v8.sym} 600 2670 1 0 {name=M236
L=0.15
W=1
nf=1 
mult=1
ad="'int((nf+1)/2) * W/nf * 0.29'" 
pd="'2*int((nf+1)/2) * (W/nf + 0.29)'"
as="'int((nf+2)/2) * W/nf * 0.29'" 
ps="'2*int((nf+2)/2) * (W/nf + 0.29)'"
nrd="'0.29 / W'" nrs="'0.29 / W'"
sa=0 sb=0 sd=0
model=nfet_01v8
spiceprefix=X
}
C {devices/ipin.sym} 0 2710 0 0 {name=p68 lab=word45}
C {sky130_fd_pr/nfet_01v8.sym} 40 2730 1 0 {name=M237
L=0.15
W=1
nf=1 
mult=1
ad="'int((nf+1)/2) * W/nf * 0.29'" 
pd="'2*int((nf+1)/2) * (W/nf + 0.29)'"
as="'int((nf+2)/2) * W/nf * 0.29'" 
ps="'2*int((nf+2)/2) * (W/nf + 0.29)'"
nrd="'0.29 / W'" nrs="'0.29 / W'"
sa=0 sb=0 sd=0
model=nfet_01v8
spiceprefix=X
}
C {sky130_fd_pr/nfet_01v8.sym} 120 2730 1 0 {name=M238
L=0.15
W=1
nf=1 
mult=1
ad="'int((nf+1)/2) * W/nf * 0.29'" 
pd="'2*int((nf+1)/2) * (W/nf + 0.29)'"
as="'int((nf+2)/2) * W/nf * 0.29'" 
ps="'2*int((nf+2)/2) * (W/nf + 0.29)'"
nrd="'0.29 / W'" nrs="'0.29 / W'"
sa=0 sb=0 sd=0
model=nfet_01v8
spiceprefix=X
}
C {sky130_fd_pr/nfet_01v8.sym} 360 2730 1 0 {name=M239
L=0.15
W=1
nf=1 
mult=1
ad="'int((nf+1)/2) * W/nf * 0.29'" 
pd="'2*int((nf+1)/2) * (W/nf + 0.29)'"
as="'int((nf+2)/2) * W/nf * 0.29'" 
ps="'2*int((nf+2)/2) * (W/nf + 0.29)'"
nrd="'0.29 / W'" nrs="'0.29 / W'"
sa=0 sb=0 sd=0
model=nfet_01v8
spiceprefix=X
}
C {sky130_fd_pr/nfet_01v8.sym} 440 2730 1 0 {name=M240
L=0.15
W=1
nf=1 
mult=1
ad="'int((nf+1)/2) * W/nf * 0.29'" 
pd="'2*int((nf+1)/2) * (W/nf + 0.29)'"
as="'int((nf+2)/2) * W/nf * 0.29'" 
ps="'2*int((nf+2)/2) * (W/nf + 0.29)'"
nrd="'0.29 / W'" nrs="'0.29 / W'"
sa=0 sb=0 sd=0
model=nfet_01v8
spiceprefix=X
}
C {sky130_fd_pr/nfet_01v8.sym} 520 2730 1 0 {name=M241
L=0.15
W=1
nf=1 
mult=1
ad="'int((nf+1)/2) * W/nf * 0.29'" 
pd="'2*int((nf+1)/2) * (W/nf + 0.29)'"
as="'int((nf+2)/2) * W/nf * 0.29'" 
ps="'2*int((nf+2)/2) * (W/nf + 0.29)'"
nrd="'0.29 / W'" nrs="'0.29 / W'"
sa=0 sb=0 sd=0
model=nfet_01v8
spiceprefix=X
}
C {sky130_fd_pr/nfet_01v8.sym} 600 2730 1 0 {name=M242
L=0.15
W=1
nf=1 
mult=1
ad="'int((nf+1)/2) * W/nf * 0.29'" 
pd="'2*int((nf+1)/2) * (W/nf + 0.29)'"
as="'int((nf+2)/2) * W/nf * 0.29'" 
ps="'2*int((nf+2)/2) * (W/nf + 0.29)'"
nrd="'0.29 / W'" nrs="'0.29 / W'"
sa=0 sb=0 sd=0
model=nfet_01v8
spiceprefix=X
}
C {devices/ipin.sym} 0 2770 0 0 {name=p69 lab=word46}
C {sky130_fd_pr/nfet_01v8.sym} 40 2790 1 0 {name=M243
L=0.15
W=1
nf=1 
mult=1
ad="'int((nf+1)/2) * W/nf * 0.29'" 
pd="'2*int((nf+1)/2) * (W/nf + 0.29)'"
as="'int((nf+2)/2) * W/nf * 0.29'" 
ps="'2*int((nf+2)/2) * (W/nf + 0.29)'"
nrd="'0.29 / W'" nrs="'0.29 / W'"
sa=0 sb=0 sd=0
model=nfet_01v8
spiceprefix=X
}
C {sky130_fd_pr/nfet_01v8.sym} 120 2790 1 0 {name=M244
L=0.15
W=1
nf=1 
mult=1
ad="'int((nf+1)/2) * W/nf * 0.29'" 
pd="'2*int((nf+1)/2) * (W/nf + 0.29)'"
as="'int((nf+2)/2) * W/nf * 0.29'" 
ps="'2*int((nf+2)/2) * (W/nf + 0.29)'"
nrd="'0.29 / W'" nrs="'0.29 / W'"
sa=0 sb=0 sd=0
model=nfet_01v8
spiceprefix=X
}
C {sky130_fd_pr/nfet_01v8.sym} 280 2790 1 0 {name=M245
L=0.15
W=1
nf=1 
mult=1
ad="'int((nf+1)/2) * W/nf * 0.29'" 
pd="'2*int((nf+1)/2) * (W/nf + 0.29)'"
as="'int((nf+2)/2) * W/nf * 0.29'" 
ps="'2*int((nf+2)/2) * (W/nf + 0.29)'"
nrd="'0.29 / W'" nrs="'0.29 / W'"
sa=0 sb=0 sd=0
model=nfet_01v8
spiceprefix=X
}
C {sky130_fd_pr/nfet_01v8.sym} 360 2790 1 0 {name=M246
L=0.15
W=1
nf=1 
mult=1
ad="'int((nf+1)/2) * W/nf * 0.29'" 
pd="'2*int((nf+1)/2) * (W/nf + 0.29)'"
as="'int((nf+2)/2) * W/nf * 0.29'" 
ps="'2*int((nf+2)/2) * (W/nf + 0.29)'"
nrd="'0.29 / W'" nrs="'0.29 / W'"
sa=0 sb=0 sd=0
model=nfet_01v8
spiceprefix=X
}
C {sky130_fd_pr/nfet_01v8.sym} 440 2790 1 0 {name=M247
L=0.15
W=1
nf=1 
mult=1
ad="'int((nf+1)/2) * W/nf * 0.29'" 
pd="'2*int((nf+1)/2) * (W/nf + 0.29)'"
as="'int((nf+2)/2) * W/nf * 0.29'" 
ps="'2*int((nf+2)/2) * (W/nf + 0.29)'"
nrd="'0.29 / W'" nrs="'0.29 / W'"
sa=0 sb=0 sd=0
model=nfet_01v8
spiceprefix=X
}
C {sky130_fd_pr/nfet_01v8.sym} 520 2790 1 0 {name=M248
L=0.15
W=1
nf=1 
mult=1
ad="'int((nf+1)/2) * W/nf * 0.29'" 
pd="'2*int((nf+1)/2) * (W/nf + 0.29)'"
as="'int((nf+2)/2) * W/nf * 0.29'" 
ps="'2*int((nf+2)/2) * (W/nf + 0.29)'"
nrd="'0.29 / W'" nrs="'0.29 / W'"
sa=0 sb=0 sd=0
model=nfet_01v8
spiceprefix=X
}
C {sky130_fd_pr/nfet_01v8.sym} 600 2790 1 0 {name=M249
L=0.15
W=1
nf=1 
mult=1
ad="'int((nf+1)/2) * W/nf * 0.29'" 
pd="'2*int((nf+1)/2) * (W/nf + 0.29)'"
as="'int((nf+2)/2) * W/nf * 0.29'" 
ps="'2*int((nf+2)/2) * (W/nf + 0.29)'"
nrd="'0.29 / W'" nrs="'0.29 / W'"
sa=0 sb=0 sd=0
model=nfet_01v8
spiceprefix=X
}
C {devices/ipin.sym} 0 2830 0 0 {name=p70 lab=word47}
C {sky130_fd_pr/nfet_01v8.sym} 40 2850 1 0 {name=M250
L=0.15
W=1
nf=1 
mult=1
ad="'int((nf+1)/2) * W/nf * 0.29'" 
pd="'2*int((nf+1)/2) * (W/nf + 0.29)'"
as="'int((nf+2)/2) * W/nf * 0.29'" 
ps="'2*int((nf+2)/2) * (W/nf + 0.29)'"
nrd="'0.29 / W'" nrs="'0.29 / W'"
sa=0 sb=0 sd=0
model=nfet_01v8
spiceprefix=X
}
C {sky130_fd_pr/nfet_01v8.sym} 120 2850 1 0 {name=M251
L=0.15
W=1
nf=1 
mult=1
ad="'int((nf+1)/2) * W/nf * 0.29'" 
pd="'2*int((nf+1)/2) * (W/nf + 0.29)'"
as="'int((nf+2)/2) * W/nf * 0.29'" 
ps="'2*int((nf+2)/2) * (W/nf + 0.29)'"
nrd="'0.29 / W'" nrs="'0.29 / W'"
sa=0 sb=0 sd=0
model=nfet_01v8
spiceprefix=X
}
C {sky130_fd_pr/nfet_01v8.sym} 200 2850 1 0 {name=M252
L=0.15
W=1
nf=1 
mult=1
ad="'int((nf+1)/2) * W/nf * 0.29'" 
pd="'2*int((nf+1)/2) * (W/nf + 0.29)'"
as="'int((nf+2)/2) * W/nf * 0.29'" 
ps="'2*int((nf+2)/2) * (W/nf + 0.29)'"
nrd="'0.29 / W'" nrs="'0.29 / W'"
sa=0 sb=0 sd=0
model=nfet_01v8
spiceprefix=X
}
C {sky130_fd_pr/nfet_01v8.sym} 360 2850 1 0 {name=M253
L=0.15
W=1
nf=1 
mult=1
ad="'int((nf+1)/2) * W/nf * 0.29'" 
pd="'2*int((nf+1)/2) * (W/nf + 0.29)'"
as="'int((nf+2)/2) * W/nf * 0.29'" 
ps="'2*int((nf+2)/2) * (W/nf + 0.29)'"
nrd="'0.29 / W'" nrs="'0.29 / W'"
sa=0 sb=0 sd=0
model=nfet_01v8
spiceprefix=X
}
C {sky130_fd_pr/nfet_01v8.sym} 440 2850 1 0 {name=M254
L=0.15
W=1
nf=1 
mult=1
ad="'int((nf+1)/2) * W/nf * 0.29'" 
pd="'2*int((nf+1)/2) * (W/nf + 0.29)'"
as="'int((nf+2)/2) * W/nf * 0.29'" 
ps="'2*int((nf+2)/2) * (W/nf + 0.29)'"
nrd="'0.29 / W'" nrs="'0.29 / W'"
sa=0 sb=0 sd=0
model=nfet_01v8
spiceprefix=X
}
C {sky130_fd_pr/nfet_01v8.sym} 520 2850 1 0 {name=M255
L=0.15
W=1
nf=1 
mult=1
ad="'int((nf+1)/2) * W/nf * 0.29'" 
pd="'2*int((nf+1)/2) * (W/nf + 0.29)'"
as="'int((nf+2)/2) * W/nf * 0.29'" 
ps="'2*int((nf+2)/2) * (W/nf + 0.29)'"
nrd="'0.29 / W'" nrs="'0.29 / W'"
sa=0 sb=0 sd=0
model=nfet_01v8
spiceprefix=X
}
C {sky130_fd_pr/nfet_01v8.sym} 600 2850 1 0 {name=M256
L=0.15
W=1
nf=1 
mult=1
ad="'int((nf+1)/2) * W/nf * 0.29'" 
pd="'2*int((nf+1)/2) * (W/nf + 0.29)'"
as="'int((nf+2)/2) * W/nf * 0.29'" 
ps="'2*int((nf+2)/2) * (W/nf + 0.29)'"
nrd="'0.29 / W'" nrs="'0.29 / W'"
sa=0 sb=0 sd=0
model=nfet_01v8
spiceprefix=X
}
C {devices/ipin.sym} 0 2890 0 0 {name=p71 lab=word48}
C {devices/ipin.sym} 0 2950 0 0 {name=p72 lab=word49}
C {sky130_fd_pr/nfet_01v8.sym} 360 2970 1 0 {name=M257
L=0.15
W=1
nf=1 
mult=1
ad="'int((nf+1)/2) * W/nf * 0.29'" 
pd="'2*int((nf+1)/2) * (W/nf + 0.29)'"
as="'int((nf+2)/2) * W/nf * 0.29'" 
ps="'2*int((nf+2)/2) * (W/nf + 0.29)'"
nrd="'0.29 / W'" nrs="'0.29 / W'"
sa=0 sb=0 sd=0
model=nfet_01v8
spiceprefix=X
}
C {sky130_fd_pr/nfet_01v8.sym} 520 2970 1 0 {name=M258
L=0.15
W=1
nf=1 
mult=1
ad="'int((nf+1)/2) * W/nf * 0.29'" 
pd="'2*int((nf+1)/2) * (W/nf + 0.29)'"
as="'int((nf+2)/2) * W/nf * 0.29'" 
ps="'2*int((nf+2)/2) * (W/nf + 0.29)'"
nrd="'0.29 / W'" nrs="'0.29 / W'"
sa=0 sb=0 sd=0
model=nfet_01v8
spiceprefix=X
}
C {devices/ipin.sym} 0 3010 0 0 {name=p73 lab=word50}
C {sky130_fd_pr/nfet_01v8.sym} 200 3030 1 0 {name=M259
L=0.15
W=1
nf=1 
mult=1
ad="'int((nf+1)/2) * W/nf * 0.29'" 
pd="'2*int((nf+1)/2) * (W/nf + 0.29)'"
as="'int((nf+2)/2) * W/nf * 0.29'" 
ps="'2*int((nf+2)/2) * (W/nf + 0.29)'"
nrd="'0.29 / W'" nrs="'0.29 / W'"
sa=0 sb=0 sd=0
model=nfet_01v8
spiceprefix=X
}
C {sky130_fd_pr/nfet_01v8.sym} 440 3030 1 0 {name=M260
L=0.15
W=1
nf=1 
mult=1
ad="'int((nf+1)/2) * W/nf * 0.29'" 
pd="'2*int((nf+1)/2) * (W/nf + 0.29)'"
as="'int((nf+2)/2) * W/nf * 0.29'" 
ps="'2*int((nf+2)/2) * (W/nf + 0.29)'"
nrd="'0.29 / W'" nrs="'0.29 / W'"
sa=0 sb=0 sd=0
model=nfet_01v8
spiceprefix=X
}
C {sky130_fd_pr/nfet_01v8.sym} 600 3030 1 0 {name=M261
L=0.15
W=1
nf=1 
mult=1
ad="'int((nf+1)/2) * W/nf * 0.29'" 
pd="'2*int((nf+1)/2) * (W/nf + 0.29)'"
as="'int((nf+2)/2) * W/nf * 0.29'" 
ps="'2*int((nf+2)/2) * (W/nf + 0.29)'"
nrd="'0.29 / W'" nrs="'0.29 / W'"
sa=0 sb=0 sd=0
model=nfet_01v8
spiceprefix=X
}
C {devices/ipin.sym} 0 3070 0 0 {name=p74 lab=word51}
C {sky130_fd_pr/nfet_01v8.sym} 120 3090 1 0 {name=M262
L=0.15
W=1
nf=1 
mult=1
ad="'int((nf+1)/2) * W/nf * 0.29'" 
pd="'2*int((nf+1)/2) * (W/nf + 0.29)'"
as="'int((nf+2)/2) * W/nf * 0.29'" 
ps="'2*int((nf+2)/2) * (W/nf + 0.29)'"
nrd="'0.29 / W'" nrs="'0.29 / W'"
sa=0 sb=0 sd=0
model=nfet_01v8
spiceprefix=X
}
C {sky130_fd_pr/nfet_01v8.sym} 360 3090 1 0 {name=M263
L=0.15
W=1
nf=1 
mult=1
ad="'int((nf+1)/2) * W/nf * 0.29'" 
pd="'2*int((nf+1)/2) * (W/nf + 0.29)'"
as="'int((nf+2)/2) * W/nf * 0.29'" 
ps="'2*int((nf+2)/2) * (W/nf + 0.29)'"
nrd="'0.29 / W'" nrs="'0.29 / W'"
sa=0 sb=0 sd=0
model=nfet_01v8
spiceprefix=X
}
C {sky130_fd_pr/nfet_01v8.sym} 440 3090 1 0 {name=M264
L=0.15
W=1
nf=1 
mult=1
ad="'int((nf+1)/2) * W/nf * 0.29'" 
pd="'2*int((nf+1)/2) * (W/nf + 0.29)'"
as="'int((nf+2)/2) * W/nf * 0.29'" 
ps="'2*int((nf+2)/2) * (W/nf + 0.29)'"
nrd="'0.29 / W'" nrs="'0.29 / W'"
sa=0 sb=0 sd=0
model=nfet_01v8
spiceprefix=X
}
C {sky130_fd_pr/nfet_01v8.sym} 520 3090 1 0 {name=M265
L=0.15
W=1
nf=1 
mult=1
ad="'int((nf+1)/2) * W/nf * 0.29'" 
pd="'2*int((nf+1)/2) * (W/nf + 0.29)'"
as="'int((nf+2)/2) * W/nf * 0.29'" 
ps="'2*int((nf+2)/2) * (W/nf + 0.29)'"
nrd="'0.29 / W'" nrs="'0.29 / W'"
sa=0 sb=0 sd=0
model=nfet_01v8
spiceprefix=X
}
C {sky130_fd_pr/nfet_01v8.sym} 600 3090 1 0 {name=M266
L=0.15
W=1
nf=1 
mult=1
ad="'int((nf+1)/2) * W/nf * 0.29'" 
pd="'2*int((nf+1)/2) * (W/nf + 0.29)'"
as="'int((nf+2)/2) * W/nf * 0.29'" 
ps="'2*int((nf+2)/2) * (W/nf + 0.29)'"
nrd="'0.29 / W'" nrs="'0.29 / W'"
sa=0 sb=0 sd=0
model=nfet_01v8
spiceprefix=X
}
C {devices/ipin.sym} 0 3130 0 0 {name=p75 lab=word52}
C {sky130_fd_pr/nfet_01v8.sym} 40 3150 1 0 {name=M267
L=0.15
W=1
nf=1 
mult=1
ad="'int((nf+1)/2) * W/nf * 0.29'" 
pd="'2*int((nf+1)/2) * (W/nf + 0.29)'"
as="'int((nf+2)/2) * W/nf * 0.29'" 
ps="'2*int((nf+2)/2) * (W/nf + 0.29)'"
nrd="'0.29 / W'" nrs="'0.29 / W'"
sa=0 sb=0 sd=0
model=nfet_01v8
spiceprefix=X
}
C {devices/ipin.sym} 0 3190 0 0 {name=p76 lab=word53}
C {sky130_fd_pr/nfet_01v8.sym} 40 3210 1 0 {name=M268
L=0.15
W=1
nf=1 
mult=1
ad="'int((nf+1)/2) * W/nf * 0.29'" 
pd="'2*int((nf+1)/2) * (W/nf + 0.29)'"
as="'int((nf+2)/2) * W/nf * 0.29'" 
ps="'2*int((nf+2)/2) * (W/nf + 0.29)'"
nrd="'0.29 / W'" nrs="'0.29 / W'"
sa=0 sb=0 sd=0
model=nfet_01v8
spiceprefix=X
}
C {sky130_fd_pr/nfet_01v8.sym} 200 3210 1 0 {name=M269
L=0.15
W=1
nf=1 
mult=1
ad="'int((nf+1)/2) * W/nf * 0.29'" 
pd="'2*int((nf+1)/2) * (W/nf + 0.29)'"
as="'int((nf+2)/2) * W/nf * 0.29'" 
ps="'2*int((nf+2)/2) * (W/nf + 0.29)'"
nrd="'0.29 / W'" nrs="'0.29 / W'"
sa=0 sb=0 sd=0
model=nfet_01v8
spiceprefix=X
}
C {sky130_fd_pr/nfet_01v8.sym} 280 3210 1 0 {name=M270
L=0.15
W=1
nf=1 
mult=1
ad="'int((nf+1)/2) * W/nf * 0.29'" 
pd="'2*int((nf+1)/2) * (W/nf + 0.29)'"
as="'int((nf+2)/2) * W/nf * 0.29'" 
ps="'2*int((nf+2)/2) * (W/nf + 0.29)'"
nrd="'0.29 / W'" nrs="'0.29 / W'"
sa=0 sb=0 sd=0
model=nfet_01v8
spiceprefix=X
}
C {devices/ipin.sym} 0 3250 0 0 {name=p77 lab=word54}
C {sky130_fd_pr/nfet_01v8.sym} 40 3270 1 0 {name=M271
L=0.15
W=1
nf=1 
mult=1
ad="'int((nf+1)/2) * W/nf * 0.29'" 
pd="'2*int((nf+1)/2) * (W/nf + 0.29)'"
as="'int((nf+2)/2) * W/nf * 0.29'" 
ps="'2*int((nf+2)/2) * (W/nf + 0.29)'"
nrd="'0.29 / W'" nrs="'0.29 / W'"
sa=0 sb=0 sd=0
model=nfet_01v8
spiceprefix=X
}
C {sky130_fd_pr/nfet_01v8.sym} 120 3270 1 0 {name=M272
L=0.15
W=1
nf=1 
mult=1
ad="'int((nf+1)/2) * W/nf * 0.29'" 
pd="'2*int((nf+1)/2) * (W/nf + 0.29)'"
as="'int((nf+2)/2) * W/nf * 0.29'" 
ps="'2*int((nf+2)/2) * (W/nf + 0.29)'"
nrd="'0.29 / W'" nrs="'0.29 / W'"
sa=0 sb=0 sd=0
model=nfet_01v8
spiceprefix=X
}
C {sky130_fd_pr/nfet_01v8.sym} 280 3270 1 0 {name=M273
L=0.15
W=1
nf=1 
mult=1
ad="'int((nf+1)/2) * W/nf * 0.29'" 
pd="'2*int((nf+1)/2) * (W/nf + 0.29)'"
as="'int((nf+2)/2) * W/nf * 0.29'" 
ps="'2*int((nf+2)/2) * (W/nf + 0.29)'"
nrd="'0.29 / W'" nrs="'0.29 / W'"
sa=0 sb=0 sd=0
model=nfet_01v8
spiceprefix=X
}
C {sky130_fd_pr/nfet_01v8.sym} 360 3270 1 0 {name=M274
L=0.15
W=1
nf=1 
mult=1
ad="'int((nf+1)/2) * W/nf * 0.29'" 
pd="'2*int((nf+1)/2) * (W/nf + 0.29)'"
as="'int((nf+2)/2) * W/nf * 0.29'" 
ps="'2*int((nf+2)/2) * (W/nf + 0.29)'"
nrd="'0.29 / W'" nrs="'0.29 / W'"
sa=0 sb=0 sd=0
model=nfet_01v8
spiceprefix=X
}
C {sky130_fd_pr/nfet_01v8.sym} 520 3270 1 0 {name=M275
L=0.15
W=1
nf=1 
mult=1
ad="'int((nf+1)/2) * W/nf * 0.29'" 
pd="'2*int((nf+1)/2) * (W/nf + 0.29)'"
as="'int((nf+2)/2) * W/nf * 0.29'" 
ps="'2*int((nf+2)/2) * (W/nf + 0.29)'"
nrd="'0.29 / W'" nrs="'0.29 / W'"
sa=0 sb=0 sd=0
model=nfet_01v8
spiceprefix=X
}
C {devices/ipin.sym} 0 3310 0 0 {name=p78 lab=word55}
C {sky130_fd_pr/nfet_01v8.sym} 40 3330 1 0 {name=M276
L=0.15
W=1
nf=1 
mult=1
ad="'int((nf+1)/2) * W/nf * 0.29'" 
pd="'2*int((nf+1)/2) * (W/nf + 0.29)'"
as="'int((nf+2)/2) * W/nf * 0.29'" 
ps="'2*int((nf+2)/2) * (W/nf + 0.29)'"
nrd="'0.29 / W'" nrs="'0.29 / W'"
sa=0 sb=0 sd=0
model=nfet_01v8
spiceprefix=X
}
C {sky130_fd_pr/nfet_01v8.sym} 120 3330 1 0 {name=M277
L=0.15
W=1
nf=1 
mult=1
ad="'int((nf+1)/2) * W/nf * 0.29'" 
pd="'2*int((nf+1)/2) * (W/nf + 0.29)'"
as="'int((nf+2)/2) * W/nf * 0.29'" 
ps="'2*int((nf+2)/2) * (W/nf + 0.29)'"
nrd="'0.29 / W'" nrs="'0.29 / W'"
sa=0 sb=0 sd=0
model=nfet_01v8
spiceprefix=X
}
C {sky130_fd_pr/nfet_01v8.sym} 200 3330 1 0 {name=M278
L=0.15
W=1
nf=1 
mult=1
ad="'int((nf+1)/2) * W/nf * 0.29'" 
pd="'2*int((nf+1)/2) * (W/nf + 0.29)'"
as="'int((nf+2)/2) * W/nf * 0.29'" 
ps="'2*int((nf+2)/2) * (W/nf + 0.29)'"
nrd="'0.29 / W'" nrs="'0.29 / W'"
sa=0 sb=0 sd=0
model=nfet_01v8
spiceprefix=X
}
C {sky130_fd_pr/nfet_01v8.sym} 280 3330 1 0 {name=M279
L=0.15
W=1
nf=1 
mult=1
ad="'int((nf+1)/2) * W/nf * 0.29'" 
pd="'2*int((nf+1)/2) * (W/nf + 0.29)'"
as="'int((nf+2)/2) * W/nf * 0.29'" 
ps="'2*int((nf+2)/2) * (W/nf + 0.29)'"
nrd="'0.29 / W'" nrs="'0.29 / W'"
sa=0 sb=0 sd=0
model=nfet_01v8
spiceprefix=X
}
C {sky130_fd_pr/nfet_01v8.sym} 440 3330 1 0 {name=M280
L=0.15
W=1
nf=1 
mult=1
ad="'int((nf+1)/2) * W/nf * 0.29'" 
pd="'2*int((nf+1)/2) * (W/nf + 0.29)'"
as="'int((nf+2)/2) * W/nf * 0.29'" 
ps="'2*int((nf+2)/2) * (W/nf + 0.29)'"
nrd="'0.29 / W'" nrs="'0.29 / W'"
sa=0 sb=0 sd=0
model=nfet_01v8
spiceprefix=X
}
C {sky130_fd_pr/nfet_01v8.sym} 600 3330 1 0 {name=M281
L=0.15
W=1
nf=1 
mult=1
ad="'int((nf+1)/2) * W/nf * 0.29'" 
pd="'2*int((nf+1)/2) * (W/nf + 0.29)'"
as="'int((nf+2)/2) * W/nf * 0.29'" 
ps="'2*int((nf+2)/2) * (W/nf + 0.29)'"
nrd="'0.29 / W'" nrs="'0.29 / W'"
sa=0 sb=0 sd=0
model=nfet_01v8
spiceprefix=X
}
C {devices/ipin.sym} 0 3370 0 0 {name=p79 lab=word56}
C {sky130_fd_pr/nfet_01v8.sym} 40 3390 1 0 {name=M282
L=0.15
W=1
nf=1 
mult=1
ad="'int((nf+1)/2) * W/nf * 0.29'" 
pd="'2*int((nf+1)/2) * (W/nf + 0.29)'"
as="'int((nf+2)/2) * W/nf * 0.29'" 
ps="'2*int((nf+2)/2) * (W/nf + 0.29)'"
nrd="'0.29 / W'" nrs="'0.29 / W'"
sa=0 sb=0 sd=0
model=nfet_01v8
spiceprefix=X
}
C {sky130_fd_pr/nfet_01v8.sym} 120 3390 1 0 {name=M283
L=0.15
W=1
nf=1 
mult=1
ad="'int((nf+1)/2) * W/nf * 0.29'" 
pd="'2*int((nf+1)/2) * (W/nf + 0.29)'"
as="'int((nf+2)/2) * W/nf * 0.29'" 
ps="'2*int((nf+2)/2) * (W/nf + 0.29)'"
nrd="'0.29 / W'" nrs="'0.29 / W'"
sa=0 sb=0 sd=0
model=nfet_01v8
spiceprefix=X
}
C {sky130_fd_pr/nfet_01v8.sym} 200 3390 1 0 {name=M284
L=0.15
W=1
nf=1 
mult=1
ad="'int((nf+1)/2) * W/nf * 0.29'" 
pd="'2*int((nf+1)/2) * (W/nf + 0.29)'"
as="'int((nf+2)/2) * W/nf * 0.29'" 
ps="'2*int((nf+2)/2) * (W/nf + 0.29)'"
nrd="'0.29 / W'" nrs="'0.29 / W'"
sa=0 sb=0 sd=0
model=nfet_01v8
spiceprefix=X
}
C {sky130_fd_pr/nfet_01v8.sym} 280 3390 1 0 {name=M285
L=0.15
W=1
nf=1 
mult=1
ad="'int((nf+1)/2) * W/nf * 0.29'" 
pd="'2*int((nf+1)/2) * (W/nf + 0.29)'"
as="'int((nf+2)/2) * W/nf * 0.29'" 
ps="'2*int((nf+2)/2) * (W/nf + 0.29)'"
nrd="'0.29 / W'" nrs="'0.29 / W'"
sa=0 sb=0 sd=0
model=nfet_01v8
spiceprefix=X
}
C {sky130_fd_pr/nfet_01v8.sym} 360 3390 1 0 {name=M286
L=0.15
W=1
nf=1 
mult=1
ad="'int((nf+1)/2) * W/nf * 0.29'" 
pd="'2*int((nf+1)/2) * (W/nf + 0.29)'"
as="'int((nf+2)/2) * W/nf * 0.29'" 
ps="'2*int((nf+2)/2) * (W/nf + 0.29)'"
nrd="'0.29 / W'" nrs="'0.29 / W'"
sa=0 sb=0 sd=0
model=nfet_01v8
spiceprefix=X
}
C {sky130_fd_pr/nfet_01v8.sym} 440 3390 1 0 {name=M287
L=0.15
W=1
nf=1 
mult=1
ad="'int((nf+1)/2) * W/nf * 0.29'" 
pd="'2*int((nf+1)/2) * (W/nf + 0.29)'"
as="'int((nf+2)/2) * W/nf * 0.29'" 
ps="'2*int((nf+2)/2) * (W/nf + 0.29)'"
nrd="'0.29 / W'" nrs="'0.29 / W'"
sa=0 sb=0 sd=0
model=nfet_01v8
spiceprefix=X
}
C {sky130_fd_pr/nfet_01v8.sym} 520 3390 1 0 {name=M288
L=0.15
W=1
nf=1 
mult=1
ad="'int((nf+1)/2) * W/nf * 0.29'" 
pd="'2*int((nf+1)/2) * (W/nf + 0.29)'"
as="'int((nf+2)/2) * W/nf * 0.29'" 
ps="'2*int((nf+2)/2) * (W/nf + 0.29)'"
nrd="'0.29 / W'" nrs="'0.29 / W'"
sa=0 sb=0 sd=0
model=nfet_01v8
spiceprefix=X
}
C {sky130_fd_pr/nfet_01v8.sym} 600 3390 1 0 {name=M289
L=0.15
W=1
nf=1 
mult=1
ad="'int((nf+1)/2) * W/nf * 0.29'" 
pd="'2*int((nf+1)/2) * (W/nf + 0.29)'"
as="'int((nf+2)/2) * W/nf * 0.29'" 
ps="'2*int((nf+2)/2) * (W/nf + 0.29)'"
nrd="'0.29 / W'" nrs="'0.29 / W'"
sa=0 sb=0 sd=0
model=nfet_01v8
spiceprefix=X
}
C {devices/ipin.sym} 0 3430 0 0 {name=p80 lab=word57}
C {sky130_fd_pr/nfet_01v8.sym} 40 3450 1 0 {name=M290
L=0.15
W=1
nf=1 
mult=1
ad="'int((nf+1)/2) * W/nf * 0.29'" 
pd="'2*int((nf+1)/2) * (W/nf + 0.29)'"
as="'int((nf+2)/2) * W/nf * 0.29'" 
ps="'2*int((nf+2)/2) * (W/nf + 0.29)'"
nrd="'0.29 / W'" nrs="'0.29 / W'"
sa=0 sb=0 sd=0
model=nfet_01v8
spiceprefix=X
}
C {sky130_fd_pr/nfet_01v8.sym} 120 3450 1 0 {name=M291
L=0.15
W=1
nf=1 
mult=1
ad="'int((nf+1)/2) * W/nf * 0.29'" 
pd="'2*int((nf+1)/2) * (W/nf + 0.29)'"
as="'int((nf+2)/2) * W/nf * 0.29'" 
ps="'2*int((nf+2)/2) * (W/nf + 0.29)'"
nrd="'0.29 / W'" nrs="'0.29 / W'"
sa=0 sb=0 sd=0
model=nfet_01v8
spiceprefix=X
}
C {sky130_fd_pr/nfet_01v8.sym} 200 3450 1 0 {name=M292
L=0.15
W=1
nf=1 
mult=1
ad="'int((nf+1)/2) * W/nf * 0.29'" 
pd="'2*int((nf+1)/2) * (W/nf + 0.29)'"
as="'int((nf+2)/2) * W/nf * 0.29'" 
ps="'2*int((nf+2)/2) * (W/nf + 0.29)'"
nrd="'0.29 / W'" nrs="'0.29 / W'"
sa=0 sb=0 sd=0
model=nfet_01v8
spiceprefix=X
}
C {sky130_fd_pr/nfet_01v8.sym} 280 3450 1 0 {name=M293
L=0.15
W=1
nf=1 
mult=1
ad="'int((nf+1)/2) * W/nf * 0.29'" 
pd="'2*int((nf+1)/2) * (W/nf + 0.29)'"
as="'int((nf+2)/2) * W/nf * 0.29'" 
ps="'2*int((nf+2)/2) * (W/nf + 0.29)'"
nrd="'0.29 / W'" nrs="'0.29 / W'"
sa=0 sb=0 sd=0
model=nfet_01v8
spiceprefix=X
}
C {sky130_fd_pr/nfet_01v8.sym} 440 3450 1 0 {name=M294
L=0.15
W=1
nf=1 
mult=1
ad="'int((nf+1)/2) * W/nf * 0.29'" 
pd="'2*int((nf+1)/2) * (W/nf + 0.29)'"
as="'int((nf+2)/2) * W/nf * 0.29'" 
ps="'2*int((nf+2)/2) * (W/nf + 0.29)'"
nrd="'0.29 / W'" nrs="'0.29 / W'"
sa=0 sb=0 sd=0
model=nfet_01v8
spiceprefix=X
}
C {sky130_fd_pr/nfet_01v8.sym} 600 3450 1 0 {name=M295
L=0.15
W=1
nf=1 
mult=1
ad="'int((nf+1)/2) * W/nf * 0.29'" 
pd="'2*int((nf+1)/2) * (W/nf + 0.29)'"
as="'int((nf+2)/2) * W/nf * 0.29'" 
ps="'2*int((nf+2)/2) * (W/nf + 0.29)'"
nrd="'0.29 / W'" nrs="'0.29 / W'"
sa=0 sb=0 sd=0
model=nfet_01v8
spiceprefix=X
}
C {devices/ipin.sym} 0 3490 0 0 {name=p81 lab=word58}
C {sky130_fd_pr/nfet_01v8.sym} 40 3510 1 0 {name=M296
L=0.15
W=1
nf=1 
mult=1
ad="'int((nf+1)/2) * W/nf * 0.29'" 
pd="'2*int((nf+1)/2) * (W/nf + 0.29)'"
as="'int((nf+2)/2) * W/nf * 0.29'" 
ps="'2*int((nf+2)/2) * (W/nf + 0.29)'"
nrd="'0.29 / W'" nrs="'0.29 / W'"
sa=0 sb=0 sd=0
model=nfet_01v8
spiceprefix=X
}
C {sky130_fd_pr/nfet_01v8.sym} 120 3510 1 0 {name=M297
L=0.15
W=1
nf=1 
mult=1
ad="'int((nf+1)/2) * W/nf * 0.29'" 
pd="'2*int((nf+1)/2) * (W/nf + 0.29)'"
as="'int((nf+2)/2) * W/nf * 0.29'" 
ps="'2*int((nf+2)/2) * (W/nf + 0.29)'"
nrd="'0.29 / W'" nrs="'0.29 / W'"
sa=0 sb=0 sd=0
model=nfet_01v8
spiceprefix=X
}
C {sky130_fd_pr/nfet_01v8.sym} 280 3510 1 0 {name=M298
L=0.15
W=1
nf=1 
mult=1
ad="'int((nf+1)/2) * W/nf * 0.29'" 
pd="'2*int((nf+1)/2) * (W/nf + 0.29)'"
as="'int((nf+2)/2) * W/nf * 0.29'" 
ps="'2*int((nf+2)/2) * (W/nf + 0.29)'"
nrd="'0.29 / W'" nrs="'0.29 / W'"
sa=0 sb=0 sd=0
model=nfet_01v8
spiceprefix=X
}
C {sky130_fd_pr/nfet_01v8.sym} 360 3510 1 0 {name=M299
L=0.15
W=1
nf=1 
mult=1
ad="'int((nf+1)/2) * W/nf * 0.29'" 
pd="'2*int((nf+1)/2) * (W/nf + 0.29)'"
as="'int((nf+2)/2) * W/nf * 0.29'" 
ps="'2*int((nf+2)/2) * (W/nf + 0.29)'"
nrd="'0.29 / W'" nrs="'0.29 / W'"
sa=0 sb=0 sd=0
model=nfet_01v8
spiceprefix=X
}
C {sky130_fd_pr/nfet_01v8.sym} 520 3510 1 0 {name=M300
L=0.15
W=1
nf=1 
mult=1
ad="'int((nf+1)/2) * W/nf * 0.29'" 
pd="'2*int((nf+1)/2) * (W/nf + 0.29)'"
as="'int((nf+2)/2) * W/nf * 0.29'" 
ps="'2*int((nf+2)/2) * (W/nf + 0.29)'"
nrd="'0.29 / W'" nrs="'0.29 / W'"
sa=0 sb=0 sd=0
model=nfet_01v8
spiceprefix=X
}
C {devices/ipin.sym} 0 3550 0 0 {name=p82 lab=word59}
C {sky130_fd_pr/nfet_01v8.sym} 40 3570 1 0 {name=M301
L=0.15
W=1
nf=1 
mult=1
ad="'int((nf+1)/2) * W/nf * 0.29'" 
pd="'2*int((nf+1)/2) * (W/nf + 0.29)'"
as="'int((nf+2)/2) * W/nf * 0.29'" 
ps="'2*int((nf+2)/2) * (W/nf + 0.29)'"
nrd="'0.29 / W'" nrs="'0.29 / W'"
sa=0 sb=0 sd=0
model=nfet_01v8
spiceprefix=X
}
C {sky130_fd_pr/nfet_01v8.sym} 200 3570 1 0 {name=M302
L=0.15
W=1
nf=1 
mult=1
ad="'int((nf+1)/2) * W/nf * 0.29'" 
pd="'2*int((nf+1)/2) * (W/nf + 0.29)'"
as="'int((nf+2)/2) * W/nf * 0.29'" 
ps="'2*int((nf+2)/2) * (W/nf + 0.29)'"
nrd="'0.29 / W'" nrs="'0.29 / W'"
sa=0 sb=0 sd=0
model=nfet_01v8
spiceprefix=X
}
C {sky130_fd_pr/nfet_01v8.sym} 280 3570 1 0 {name=M303
L=0.15
W=1
nf=1 
mult=1
ad="'int((nf+1)/2) * W/nf * 0.29'" 
pd="'2*int((nf+1)/2) * (W/nf + 0.29)'"
as="'int((nf+2)/2) * W/nf * 0.29'" 
ps="'2*int((nf+2)/2) * (W/nf + 0.29)'"
nrd="'0.29 / W'" nrs="'0.29 / W'"
sa=0 sb=0 sd=0
model=nfet_01v8
spiceprefix=X
}
C {devices/ipin.sym} 0 3610 0 0 {name=p83 lab=word60}
C {sky130_fd_pr/nfet_01v8.sym} 40 3630 1 0 {name=M304
L=0.15
W=1
nf=1 
mult=1
ad="'int((nf+1)/2) * W/nf * 0.29'" 
pd="'2*int((nf+1)/2) * (W/nf + 0.29)'"
as="'int((nf+2)/2) * W/nf * 0.29'" 
ps="'2*int((nf+2)/2) * (W/nf + 0.29)'"
nrd="'0.29 / W'" nrs="'0.29 / W'"
sa=0 sb=0 sd=0
model=nfet_01v8
spiceprefix=X
}
C {devices/ipin.sym} 0 3670 0 0 {name=p84 lab=word61}
C {sky130_fd_pr/nfet_01v8.sym} 120 3690 1 0 {name=M305
L=0.15
W=1
nf=1 
mult=1
ad="'int((nf+1)/2) * W/nf * 0.29'" 
pd="'2*int((nf+1)/2) * (W/nf + 0.29)'"
as="'int((nf+2)/2) * W/nf * 0.29'" 
ps="'2*int((nf+2)/2) * (W/nf + 0.29)'"
nrd="'0.29 / W'" nrs="'0.29 / W'"
sa=0 sb=0 sd=0
model=nfet_01v8
spiceprefix=X
}
C {sky130_fd_pr/nfet_01v8.sym} 360 3690 1 0 {name=M306
L=0.15
W=1
nf=1 
mult=1
ad="'int((nf+1)/2) * W/nf * 0.29'" 
pd="'2*int((nf+1)/2) * (W/nf + 0.29)'"
as="'int((nf+2)/2) * W/nf * 0.29'" 
ps="'2*int((nf+2)/2) * (W/nf + 0.29)'"
nrd="'0.29 / W'" nrs="'0.29 / W'"
sa=0 sb=0 sd=0
model=nfet_01v8
spiceprefix=X
}
C {sky130_fd_pr/nfet_01v8.sym} 440 3690 1 0 {name=M307
L=0.15
W=1
nf=1 
mult=1
ad="'int((nf+1)/2) * W/nf * 0.29'" 
pd="'2*int((nf+1)/2) * (W/nf + 0.29)'"
as="'int((nf+2)/2) * W/nf * 0.29'" 
ps="'2*int((nf+2)/2) * (W/nf + 0.29)'"
nrd="'0.29 / W'" nrs="'0.29 / W'"
sa=0 sb=0 sd=0
model=nfet_01v8
spiceprefix=X
}
C {sky130_fd_pr/nfet_01v8.sym} 520 3690 1 0 {name=M308
L=0.15
W=1
nf=1 
mult=1
ad="'int((nf+1)/2) * W/nf * 0.29'" 
pd="'2*int((nf+1)/2) * (W/nf + 0.29)'"
as="'int((nf+2)/2) * W/nf * 0.29'" 
ps="'2*int((nf+2)/2) * (W/nf + 0.29)'"
nrd="'0.29 / W'" nrs="'0.29 / W'"
sa=0 sb=0 sd=0
model=nfet_01v8
spiceprefix=X
}
C {sky130_fd_pr/nfet_01v8.sym} 600 3690 1 0 {name=M309
L=0.15
W=1
nf=1 
mult=1
ad="'int((nf+1)/2) * W/nf * 0.29'" 
pd="'2*int((nf+1)/2) * (W/nf + 0.29)'"
as="'int((nf+2)/2) * W/nf * 0.29'" 
ps="'2*int((nf+2)/2) * (W/nf + 0.29)'"
nrd="'0.29 / W'" nrs="'0.29 / W'"
sa=0 sb=0 sd=0
model=nfet_01v8
spiceprefix=X
}
C {devices/ipin.sym} 0 3730 0 0 {name=p85 lab=word62}
C {sky130_fd_pr/nfet_01v8.sym} 200 3750 1 0 {name=M310
L=0.15
W=1
nf=1 
mult=1
ad="'int((nf+1)/2) * W/nf * 0.29'" 
pd="'2*int((nf+1)/2) * (W/nf + 0.29)'"
as="'int((nf+2)/2) * W/nf * 0.29'" 
ps="'2*int((nf+2)/2) * (W/nf + 0.29)'"
nrd="'0.29 / W'" nrs="'0.29 / W'"
sa=0 sb=0 sd=0
model=nfet_01v8
spiceprefix=X
}
C {sky130_fd_pr/nfet_01v8.sym} 440 3750 1 0 {name=M311
L=0.15
W=1
nf=1 
mult=1
ad="'int((nf+1)/2) * W/nf * 0.29'" 
pd="'2*int((nf+1)/2) * (W/nf + 0.29)'"
as="'int((nf+2)/2) * W/nf * 0.29'" 
ps="'2*int((nf+2)/2) * (W/nf + 0.29)'"
nrd="'0.29 / W'" nrs="'0.29 / W'"
sa=0 sb=0 sd=0
model=nfet_01v8
spiceprefix=X
}
C {sky130_fd_pr/nfet_01v8.sym} 600 3750 1 0 {name=M312
L=0.15
W=1
nf=1 
mult=1
ad="'int((nf+1)/2) * W/nf * 0.29'" 
pd="'2*int((nf+1)/2) * (W/nf + 0.29)'"
as="'int((nf+2)/2) * W/nf * 0.29'" 
ps="'2*int((nf+2)/2) * (W/nf + 0.29)'"
nrd="'0.29 / W'" nrs="'0.29 / W'"
sa=0 sb=0 sd=0
model=nfet_01v8
spiceprefix=X
}
C {devices/ipin.sym} 0 3790 0 0 {name=p86 lab=word63}
C {sky130_fd_pr/nfet_01v8.sym} 360 3810 1 0 {name=M313
L=0.15
W=1
nf=1 
mult=1
ad="'int((nf+1)/2) * W/nf * 0.29'" 
pd="'2*int((nf+1)/2) * (W/nf + 0.29)'"
as="'int((nf+2)/2) * W/nf * 0.29'" 
ps="'2*int((nf+2)/2) * (W/nf + 0.29)'"
nrd="'0.29 / W'" nrs="'0.29 / W'"
sa=0 sb=0 sd=0
model=nfet_01v8
spiceprefix=X
}
C {sky130_fd_pr/nfet_01v8.sym} 520 3810 1 0 {name=M314
L=0.15
W=1
nf=1 
mult=1
ad="'int((nf+1)/2) * W/nf * 0.29'" 
pd="'2*int((nf+1)/2) * (W/nf + 0.29)'"
as="'int((nf+2)/2) * W/nf * 0.29'" 
ps="'2*int((nf+2)/2) * (W/nf + 0.29)'"
nrd="'0.29 / W'" nrs="'0.29 / W'"
sa=0 sb=0 sd=0
model=nfet_01v8
spiceprefix=X
}
C {devices/opin.sym} 70 3840 1 0 {name=p87 lab=Y7}
C {devices/opin.sym} 150 3840 1 0 {name=p88 lab=Y6}
C {devices/opin.sym} 230 3840 1 0 {name=p89 lab=Y5}
C {devices/opin.sym} 310 3840 1 0 {name=p90 lab=Y4}
C {devices/opin.sym} 390 3840 1 0 {name=p91 lab=Y3}
C {devices/opin.sym} 470 3840 1 0 {name=p92 lab=Y2}
C {devices/opin.sym} 550 3840 1 0 {name=p93 lab=Y1}
C {devices/opin.sym} 630 3840 1 0 {name=p94 lab=Y0}
